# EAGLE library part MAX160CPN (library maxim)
ANALOG/DIGITAL CONVERTER

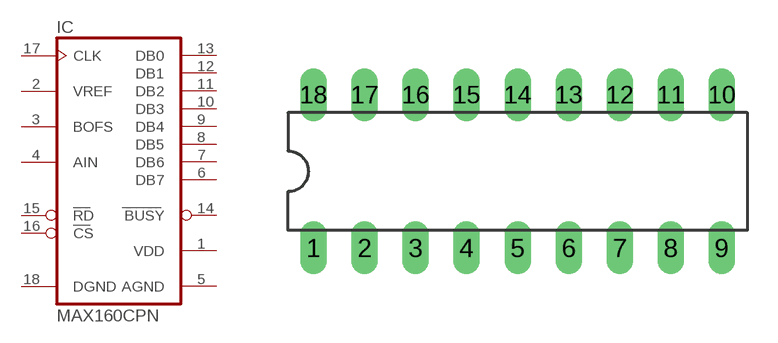
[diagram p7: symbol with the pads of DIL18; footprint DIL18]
Designator prefix IC

## MAX160CPN (MPN: MAX160CPN+; OC_FARNELL: unknown; OC_NEWARK: 99K3001)  [DIL18]
1  VDD  pwr
2  VREF  in
3  BOFS  in
4  AIN  in
5  AGND  pwr
6  DB7  hiz
7  DB6  hiz
8  DB5  hiz
9  DB4  hiz
10  DB3  hiz
11  DB2  hiz
12  DB1  hiz
13  DB0  hiz
14  BUSY  out
15  RD  in
16  CS  in
17  CLK  in
18  DGND  pwr

## Footprint DIL18 (pad centres in mm)
Dual In Line Package
drill 0.813 long: 1 -10.16,-3.81; 2 -7.62,-3.81; 3 -5.08,-3.81; 4 -2.54,-3.81; 5 0,-3.81; 6 2.54,-3.81; 7 5.08,-3.81; 8 7.62,-3.81; 9 10.16,-3.81; 10 10.16,3.81; 11 7.62,3.81; 12 5.08,3.81; 13 2.54,3.81; 14 0,3.81; 15 -2.54,3.81; 16 -5.08,3.81; 17 -7.62,3.81; 18 -10.16,3.81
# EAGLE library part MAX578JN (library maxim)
ANALOG/DIGITAL CONVERTER

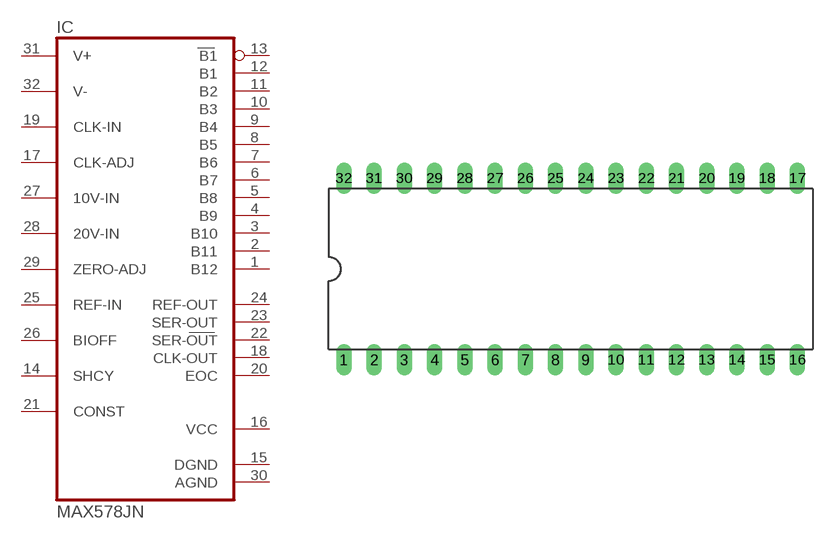
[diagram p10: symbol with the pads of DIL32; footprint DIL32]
Designator prefix IC

## MAX578JN (OC_FARNELL: unknown; OC_NEWARK: unknown)  [DIL32]
1  B12  hiz
2  B11  hiz
3  B10  hiz
4  B9  hiz
5  B8  hiz
6  B7  hiz
7  B6  hiz
8  B5  hiz
9  B4  hiz
10  B3  hiz
11  B2  hiz
12  B1  hiz
13  B1  hiz
14  SHCY  in
15  DGND  out
16  VCC  pwr
17  CLK-ADJ  in
18  CLK-OUT  out
19  CLK-IN  in
20  EOC  out
21  CONST  in
22  SER-OUT  out
23  SER-OUT  out
24  REF-OUT  out
25  REF-IN  in
26  BIOFF  in
27  10V-IN  in
28  20V-IN  in
29  ZERO-ADJ  in
30  AGND  pwr
31  V+  in
32  V-  in

## Footprint DIL32 (pad centres in mm)
Dual In Line Package
drill 0.813 long: 1 -19.05,-7.62; 2 -16.51,-7.62; 3 -13.97,-7.62; 4 -11.43,-7.62; 5 -8.89,-7.62; 6 -6.35,-7.62; 7 -3.81,-7.62; 8 -1.27,-7.62; 9 1.27,-7.62; 10 3.81,-7.62; 11 6.35,-7.62; 12 8.89,-7.62; 13 11.43,-7.62; 14 13.97,-7.62; 15 16.51,-7.62; 16 19.05,-7.62; 17 19.05,7.62; 18 16.51,7.62; 19 13.97,7.62; 20 11.43,7.62; 21 8.89,7.62; 22 6.35,7.62; 23 3.81,7.62; 24 1.27,7.62; 25 -1.27,7.62; 26 -3.81,7.62; 27 -6.35,7.62; 28 -8.89,7.62; 29 -11.43,7.62; 30 -13.97,7.62; 31 -16.51,7.62; 32 -19.05,7.62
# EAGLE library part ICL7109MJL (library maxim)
ANALOG/DIGITAL CONVERTER

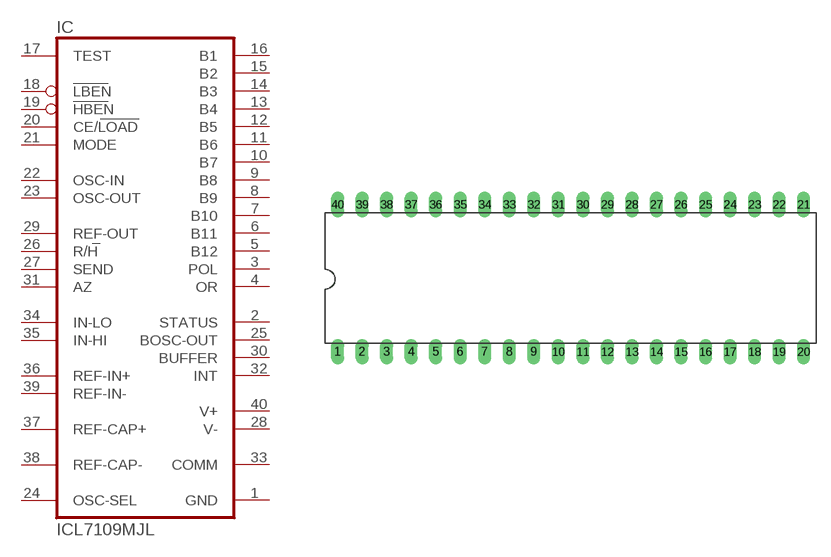
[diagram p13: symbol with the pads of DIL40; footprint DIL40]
Designator prefix IC

## ICL7109MJL (OC_FARNELL: unknown; OC_NEWARK: unknown)  [DIL40]
1  GND  pwr
2  STATUS  out
3  POL  out
4  OR  out
5  B12  hiz
6  B11  hiz
7  B10  hiz
8  B9  hiz
9  B8  hiz
10  B7  hiz
11  B6  hiz
12  B5  hiz
13  B4  hiz
14  B3  hiz
15  B2  hiz
16  B1  hiz
17  TEST  in
18  LBEN
19  HBEN
20  CE/LOAD
21  MODE  in
22  OSC-IN  in
23  OSC-OUT  out
24  OSC-SEL  in
25  BOSC-OUT  out
26  R/H  in
27  SEND  in
28  V-  pwr
29  REF-OUT  in
30  BUFFER  out
31  AZ  pas
32  INT  out
33  COMM  pwr
34  IN-LO  in
35  IN-HI  in
36  REF-IN+  in
37  REF-CAP+  pas
38  REF-CAP-  pas
39  REF-IN-  in
40  V+  pwr

## Footprint DIL40 (pad centres in mm)
Dual In Line Package
drill 0.813 long: 1 -24.13,-7.62; 2 -21.59,-7.62; 3 -19.05,-7.62; 4 -16.51,-7.62; 5 -13.97,-7.62; 6 -11.43,-7.62; 7 -8.89,-7.62; 8 -6.35,-7.62; 9 -3.81,-7.62; 10 -1.27,-7.62; 11 1.27,-7.62; 12 3.81,-7.62; 13 6.35,-7.62; 14 8.89,-7.62; 15 11.43,-7.62; 16 13.97,-7.62; 17 16.51,-7.62; 18 19.05,-7.62; 19 21.59,-7.62; 20 24.13,-7.62; 21 24.13,7.62; 22 21.59,7.62; 23 19.05,7.62; 24 16.51,7.62; 25 13.97,7.62; 26 11.43,7.62; 27 8.89,7.62; 28 6.35,7.62; 29 3.81,7.62; 30 1.27,7.62; 31 -1.27,7.62; 32 -3.81,7.62; 33 -6.35,7.62; 34 -8.89,7.62; 35 -11.43,7.62; 36 -13.97,7.62; 37 -16.51,7.62; 38 -19.05,7.62; 39 -21.59,7.62; 40 -24.13,7.62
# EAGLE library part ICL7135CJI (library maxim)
ANALOG/DIGITAL CONVERTER

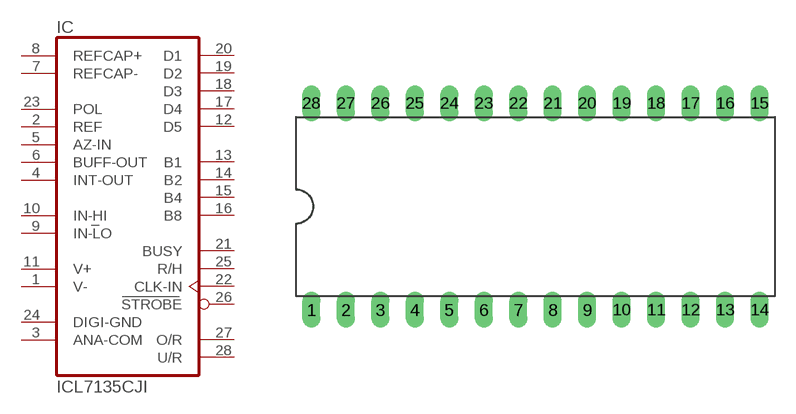
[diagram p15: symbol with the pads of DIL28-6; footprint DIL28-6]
Designator prefix IC

## ICL7135CJI (OC_FARNELL: unknown; OC_NEWARK: unknown)  [DIL28-6]
1  V-  pwr
2  REF  in
3  ANA-COM  pwr
4  INT-OUT  out
5  AZ-IN  in
6  BUFF-OUT  out
7  REFCAP-  pas
8  REFCAP+  pas
9  IN-LO  in
10  IN-HI  in
11  V+  pwr
12  D5  hiz
13  B1  out
14  B2  out
15  B4  out
16  B8  out
17  D4  hiz
18  D3  hiz
19  D2  hiz
20  D1  hiz
21  BUSY  out
22  CLK-IN  in
23  POL  in
24  DIGI-GND  pwr
25  R/H  in
26  STROBE  out
27  O/R  out
28  U/R  out

## Footprint DIL28-6 (pad centres in mm)
Dual In Line Package 0.6 inch
drill 0.813 long: 1 -16.51,-7.62; 2 -13.97,-7.62; 3 -11.43,-7.62; 4 -8.89,-7.62; 5 -6.35,-7.62; 6 -3.81,-7.62; 7 -1.27,-7.62; 8 1.27,-7.62; 9 3.81,-7.62; 10 6.35,-7.62; 11 8.89,-7.62; 12 11.43,-7.62; 13 13.97,-7.62; 14 16.51,-7.62; 15 16.51,7.62; 16 13.97,7.62; 17 11.43,7.62; 18 8.89,7.62; 19 6.35,7.62; 20 3.81,7.62; 21 1.27,7.62; 22 -1.27,7.62; 23 -3.81,7.62; 24 -6.35,7.62; 25 -8.89,7.62; 26 -11.43,7.62; 27 -13.97,7.62; 28 -16.51,7.62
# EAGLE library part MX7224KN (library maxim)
DIGITAL/ANALOG CONVERTER

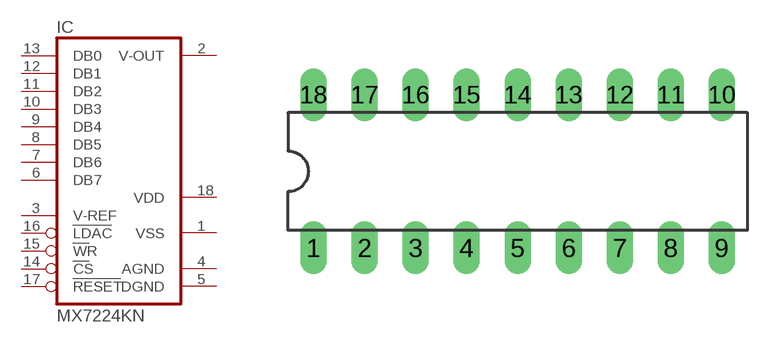
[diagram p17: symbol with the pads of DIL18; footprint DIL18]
Designator prefix IC

## MX7224KN (MPN: MX7224KN; OC_FARNELL: unknown; OC_NEWARK: 91C3202)  [DIL18]
1  VSS  pwr
2  V-OUT  out
3  V-REF  in
4  AGND  pwr
5  DGND  pwr
6  DB7  in
7  DB6  in
8  DB5  in
9  DB4  in
10  DB3  in
11  DB2  in
12  DB1  in
13  DB0  in
14  CS  in
15  WR  in
16  LDAC  in
17  RESET  in
18  VDD  pwr

## Footprint DIL18 (pad centres in mm)
Dual In Line Package
drill 0.813 long: 1 -10.16,-3.81; 2 -7.62,-3.81; 3 -5.08,-3.81; 4 -2.54,-3.81; 5 0,-3.81; 6 2.54,-3.81; 7 5.08,-3.81; 8 7.62,-3.81; 9 10.16,-3.81; 10 10.16,3.81; 11 7.62,3.81; 12 5.08,3.81; 13 2.54,3.81; 14 0,3.81; 15 -2.54,3.81; 16 -5.08,3.81; 17 -7.62,3.81; 18 -10.16,3.81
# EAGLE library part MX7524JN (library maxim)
DIGITAL/ANALOG CONVERTER

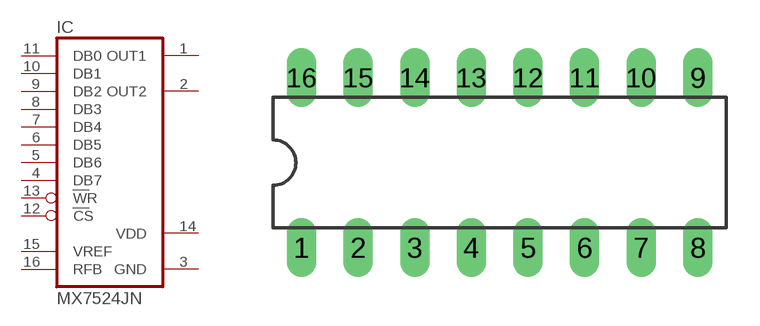
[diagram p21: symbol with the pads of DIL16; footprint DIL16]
Designator prefix IC

## MX7524JN (MPN: MX7524JN; OC_FARNELL: unknown; OC_NEWARK: 91C3294)  [DIL16]
1  OUT1  out
2  OUT2  out
3  GND  pwr
4  DB7  in
5  DB6  in
6  DB5  in
7  DB4  in
8  DB3  in
9  DB2  in
10  DB1  in
11  DB0  in
12  CS  in
13  WR  in
14  VDD  pwr
15  VREF  in
16  RFB  in

## Footprint DIL16 (pad centres in mm)
Dual In Line Package
drill 0.813 long: 1 -8.89,-3.81; 2 -6.35,-3.81; 3 -3.81,-3.81; 4 -1.27,-3.81; 5 1.27,-3.81; 6 3.81,-3.81; 7 6.35,-3.81; 8 8.89,-3.81; 9 8.89,3.81; 10 6.35,3.81; 11 3.81,3.81; 12 1.27,3.81; 13 -1.27,3.81; 14 -3.81,3.81; 15 -6.35,3.81; 16 -8.89,3.81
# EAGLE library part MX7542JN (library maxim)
DIGITAL/ANALOG CONVERTER

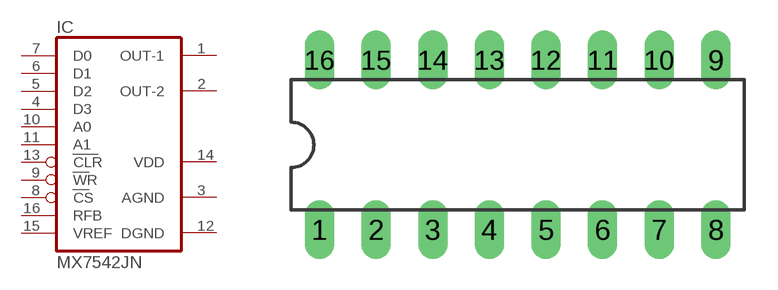
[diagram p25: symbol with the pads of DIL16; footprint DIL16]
Designator prefix IC

## MX7542JN (MPN: MX7542JN; OC_FARNELL: unknown; OC_NEWARK: 91C3501)  [DIL16]
1  OUT-1  out
2  OUT-2  out
3  AGND  pwr
4  D3  in
5  D2  in
6  D1  in
7  D0  in
8  CS  in
9  WR  in
10  A0  in
11  A1  in
12  DGND  in
13  CLR  in
14  VDD  pwr
15  VREF  in
16  RFB  in

## Footprint DIL16 (pad centres in mm)
Dual In Line Package
drill 0.813 long: 1 -8.89,-3.81; 2 -6.35,-3.81; 3 -3.81,-3.81; 4 -1.27,-3.81; 5 1.27,-3.81; 6 3.81,-3.81; 7 6.35,-3.81; 8 8.89,-3.81; 9 8.89,3.81; 10 6.35,3.81; 11 3.81,3.81; 12 1.27,3.81; 13 -1.27,3.81; 14 -3.81,3.81; 15 -6.35,3.81; 16 -8.89,3.81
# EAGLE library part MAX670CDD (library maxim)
VOLATAGE REFERENCE

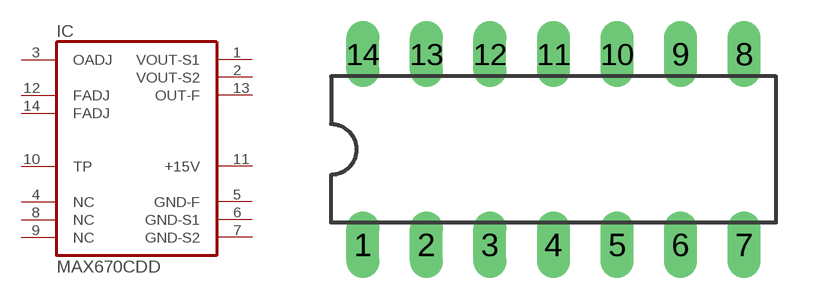
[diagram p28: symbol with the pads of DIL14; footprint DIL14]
Designator prefix IC

## MAX670CDD (OC_FARNELL: unknown; OC_NEWARK: unknown)  [DIL14]
1  VOUT-S1  out
2  VOUT-S2  out
3  OADJ  in
4  NC  nc
5  GND-F  pwr
6  GND-S1  pwr
7  GND-S2  pwr
8  NC  nc
9  NC  nc
10  TP  pas
11  +15V  pwr
12  FADJ  in
13  OUT-F  out
14  FADJ  in

## Footprint DIL14 (pad centres in mm)
Dual In Line Package
drill 0.813 long: 1 -7.62,-3.81; 2 -5.08,-3.81; 3 -2.54,-3.81; 4 0,-3.81; 5 2.54,-3.81; 6 5.08,-3.81; 7 7.62,-3.81; 8 7.62,3.81; 9 5.08,3.81; 10 2.54,3.81; 11 0,3.81; 12 -2.54,3.81; 13 -5.08,3.81; 14 -7.62,3.81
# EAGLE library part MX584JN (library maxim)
VOLTAGE REFERENCE

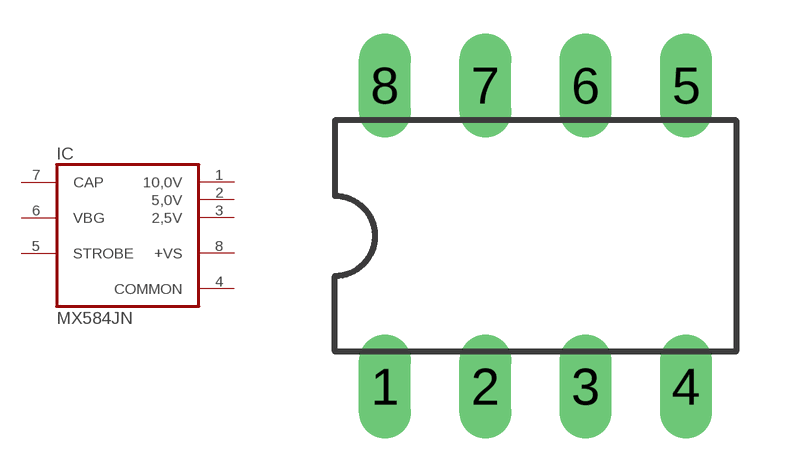
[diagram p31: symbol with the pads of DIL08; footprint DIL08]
Designator prefix IC

## MX584JN (OC_FARNELL: unknown; OC_NEWARK: unknown)  [DIL08]
1  10,0V  out
2  5,0V  out
3  2,5V  out
4  COMMON  pwr
5  STROBE  in
6  VBG  pas
7  CAP  pas
8  +VS  pwr

## Footprint DIL08 (pad centres in mm)
Dual In Line Package
drill 0.813 long: 1 -3.81,-3.81; 2 -1.27,-3.81; 3 1.27,-3.81; 4 3.81,-3.81; 5 3.81,3.81; 6 1.27,3.81; 7 -1.27,3.81; 8 -3.81,3.81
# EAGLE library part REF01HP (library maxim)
VOLTAGE REFERENCE

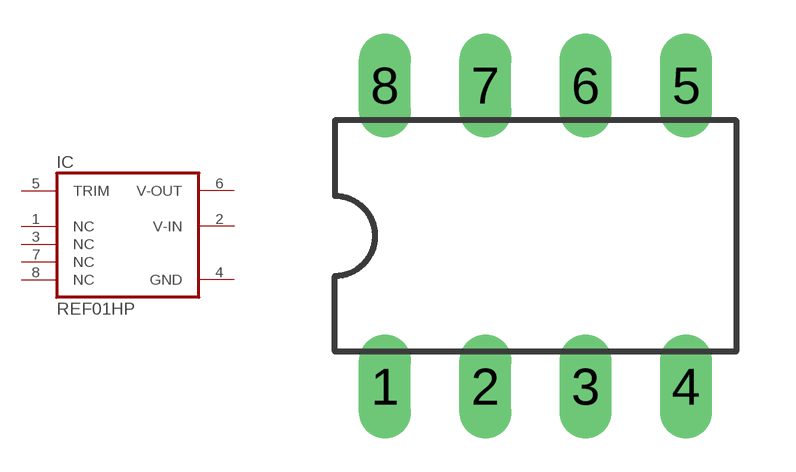
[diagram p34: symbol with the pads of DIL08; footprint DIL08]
Designator prefix IC

## REF01HP (MF: ALTERA CORPORATION; MPN: REF01HP; OC_FARNELL: 9605150; OC_NEWARK: 05F8981)  [DIL08]
1  NC  nc
2  V-IN  pwr
3  NC  nc
4  GND  pwr
5  TRIM  in
6  V-OUT  out
7  NC  nc
8  NC  nc

## Footprint DIL08 (pad centres in mm)
Dual In Line Package
drill 0.813 long: 1 -3.81,-3.81; 2 -1.27,-3.81; 3 1.27,-3.81; 4 3.81,-3.81; 5 3.81,3.81; 6 1.27,3.81; 7 -1.27,3.81; 8 -3.81,3.81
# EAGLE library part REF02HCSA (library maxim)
VOLTAGE REFERENCE

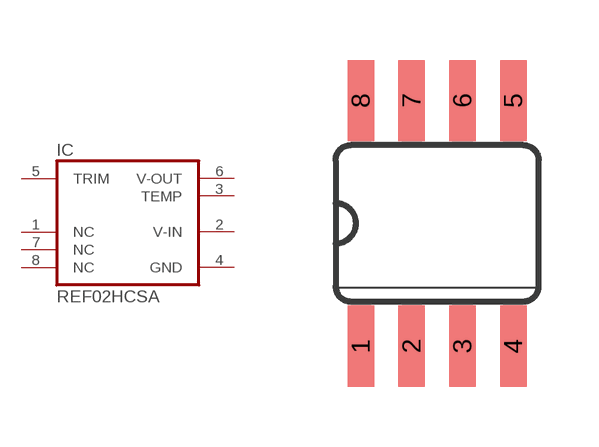
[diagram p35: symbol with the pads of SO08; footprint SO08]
Designator prefix IC

## REF02HCSA (OC_FARNELL: unknown; OC_NEWARK: unknown)  [SO08]
1  NC  nc
2  V-IN  pwr
3  TEMP  out
4  GND  pwr
5  TRIM  in
6  V-OUT  out
7  NC  nc
8  NC  nc

## Footprint SO08 (pad centres in mm)
Small Outline Package SOIC 150 mil
smd 0.66 x 2.032: 1 -1.905,-3.073; 2 -0.635,-3.073; 3 0.635,-3.073; 4 1.905,-3.073; 5 1.905,3.073; 6 0.635,3.073; 7 -0.635,3.073; 8 -1.905,3.073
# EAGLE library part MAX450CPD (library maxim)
VIDEO AMPLIFIER

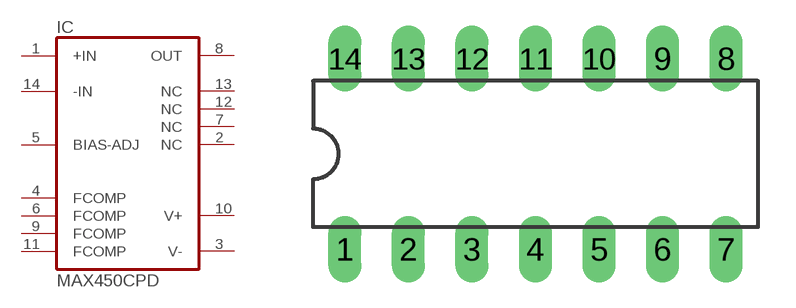
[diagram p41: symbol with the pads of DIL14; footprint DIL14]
Designator prefix IC

## MAX450CPD (OC_FARNELL: unknown; OC_NEWARK: unknown)  [DIL14]
1  +IN  in
2  NC  nc
3  V-  pwr
4  FCOMP  pas
5  BIAS-ADJ  in
6  FCOMP  pas
7  NC  nc
8  OUT  out
9  FCOMP  pas
10  V+  pwr
11  FCOMP  pas
12  NC  nc
13  NC  nc
14  -IN  in

## Footprint DIL14 (pad centres in mm)
Dual In Line Package
drill 0.813 long: 1 -7.62,-3.81; 2 -5.08,-3.81; 3 -2.54,-3.81; 4 0,-3.81; 5 2.54,-3.81; 6 5.08,-3.81; 7 7.62,-3.81; 8 7.62,3.81; 9 5.08,3.81; 10 2.54,3.81; 11 0,3.81; 12 -2.54,3.81; 13 -5.08,3.81; 14 -7.62,3.81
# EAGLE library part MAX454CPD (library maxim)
MULTIPLEXER

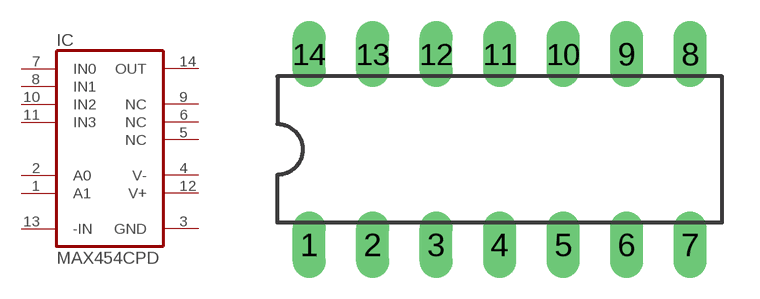
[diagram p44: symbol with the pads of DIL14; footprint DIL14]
Designator prefix IC

## MAX454CPD (MF: MAXIM; MPN: MAX454CPD+; OC_FARNELL: unknown; OC_NEWARK: 67K5326)  [DIL14]
1  A1  in
2  A0  in
3  GND  pwr
4  V-  pwr
5  NC  nc
6  NC  nc
7  IN0  in
8  IN1  in
9  NC  nc
10  IN2  in
11  IN3  in
12  V+  pwr
13  -IN  in
14  OUT  out

## Footprint DIL14 (pad centres in mm)
Dual In Line Package
drill 0.813 long: 1 -7.62,-3.81; 2 -5.08,-3.81; 3 -2.54,-3.81; 4 0,-3.81; 5 2.54,-3.81; 6 5.08,-3.81; 7 7.62,-3.81; 8 7.62,3.81; 9 5.08,3.81; 10 2.54,3.81; 11 0,3.81; 12 -2.54,3.81; 13 -5.08,3.81; 14 -7.62,3.81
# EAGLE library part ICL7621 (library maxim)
Dual Operational Amplifiers Source: http://datasheets.maxim-ic.com/en/ds/ICL7612-ICL764X.pdf

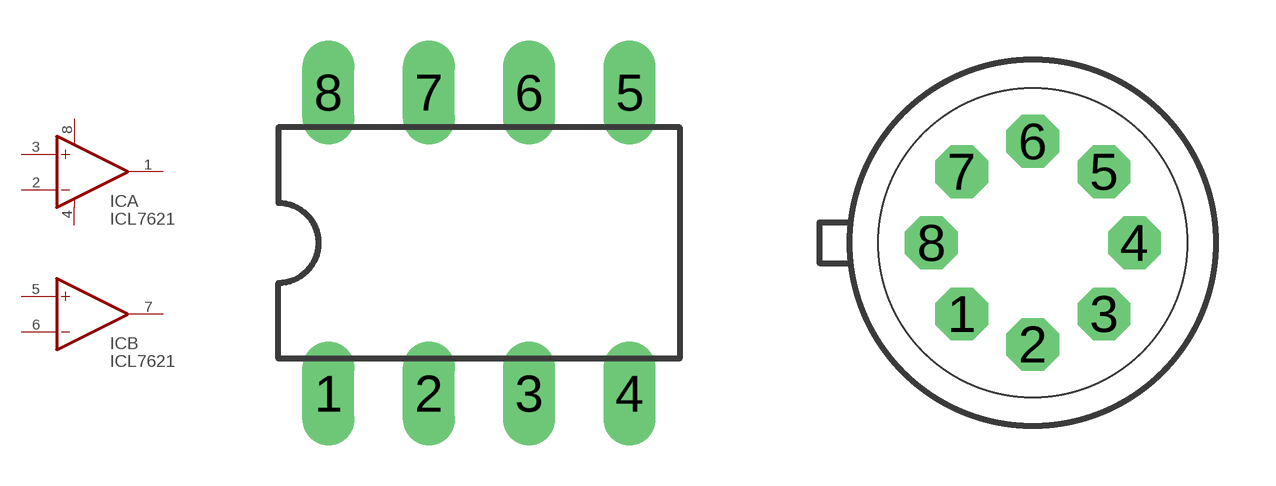
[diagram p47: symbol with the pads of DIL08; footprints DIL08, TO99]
Designator prefix IC; gates A=OPAMP+- B=OPAMP

## ICL7621PA (OC_FARNELL: unknown; OC_NEWARK: unknown)  [DIL08]
1  A:OUT  out
2  A:-IN  in
3  A:+IN  in
4  A:V-  pwr
5  B:+IN  in
6  B:-IN  in
7  B:OUT  out
8  A:V+  pwr

## ICL7621TV (OC_FARNELL: unknown; OC_NEWARK: unknown)  [TO99]
Pads as for DIL08

## ICL7621SA (OC_FARNELL: unknown; OC_NEWARK: unknown)  [SO08]
Pads as for DIL08

## Footprint DIL08 (pad centres in mm)
Dual In Line Package
drill 0.813 long: 1 -3.81,-3.81; 2 -1.27,-3.81; 3 1.27,-3.81; 4 3.81,-3.81; 5 3.81,3.81; 6 1.27,3.81; 7 -1.27,3.81; 8 -3.81,3.81

## Footprint TO99 (pad centres in mm)
TO-99
drill 0.813 octagon: 1 -1.778,-1.778; 2 0,-2.54; 3 1.778,-1.778; 4 2.54,0; 5 1.778,1.778; 6 0,2.54; 7 -1.778,1.778; 8 -2.54,0

## Footprint SO08 (pad centres in mm)
Small Outline Package SOIC 150 mil
smd 0.66 x 2.032: 1 -1.905,-3.073; 2 -0.635,-3.073; 3 0.635,-3.073; 4 1.905,-3.073; 5 1.905,3.073; 6 0.635,3.073; 7 -0.635,3.073; 8 -1.905,3.073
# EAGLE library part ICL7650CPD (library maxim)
OP AMP

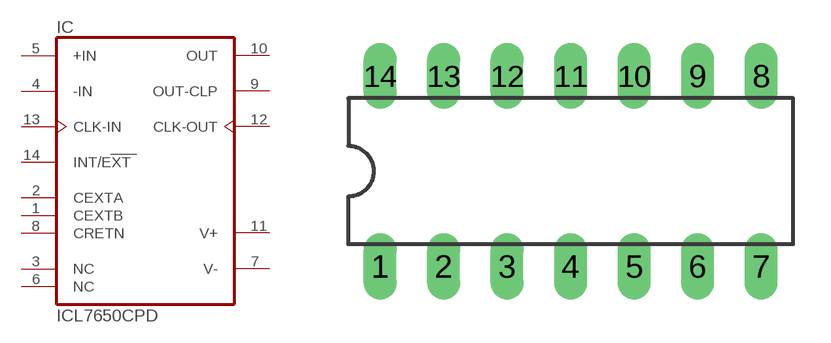
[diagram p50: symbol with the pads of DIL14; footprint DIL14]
Designator prefix IC

## ICL7650CPD (MPN: ICL7650CPD; OC_FARNELL: unknown; OC_NEWARK: 06F7425)  [DIL14]
1  CEXTB  pas
2  CEXTA  pas
3  NC  nc
4  -IN  in
5  +IN  in
6  NC  nc
7  V-  pwr
8  CRETN  pas
9  OUT-CLP  out
10  OUT  out
11  V+  pwr
12  CLK-OUT  out
13  CLK-IN  in
14  INT/EXT  in

## Footprint DIL14 (pad centres in mm)
Dual In Line Package
drill 0.813 long: 1 -7.62,-3.81; 2 -5.08,-3.81; 3 -2.54,-3.81; 4 0,-3.81; 5 2.54,-3.81; 6 5.08,-3.81; 7 7.62,-3.81; 8 7.62,3.81; 9 5.08,3.81; 10 2.54,3.81; 11 0,3.81; 12 -2.54,3.81; 13 -5.08,3.81; 14 -7.62,3.81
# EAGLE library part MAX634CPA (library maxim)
SWITCHING REGULATOR

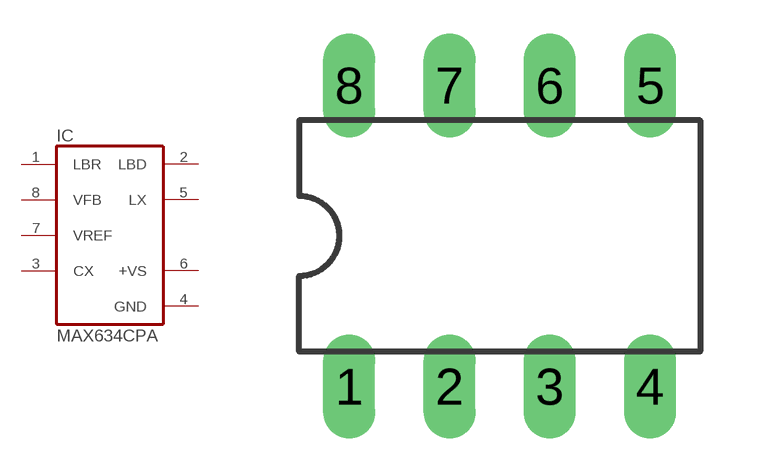
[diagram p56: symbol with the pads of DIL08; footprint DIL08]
Designator prefix IC

## MAX634CPA (MPN: MAX634CPA; OC_FARNELL: unknown; OC_NEWARK: 78C4814)  [DIL08]
1  LBR  in
2  LBD  out
3  CX  pas
4  GND  pwr
5  LX  out
6  +VS  pwr
7  VREF  in
8  VFB  in

## Footprint DIL08 (pad centres in mm)
Dual In Line Package
drill 0.813 long: 1 -3.81,-3.81; 2 -1.27,-3.81; 3 1.27,-3.81; 4 3.81,-3.81; 5 3.81,3.81; 6 1.27,3.81; 7 -1.27,3.81; 8 -3.81,3.81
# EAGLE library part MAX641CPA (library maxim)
Step-up SWITCHING REGULATOR CONTROLLER

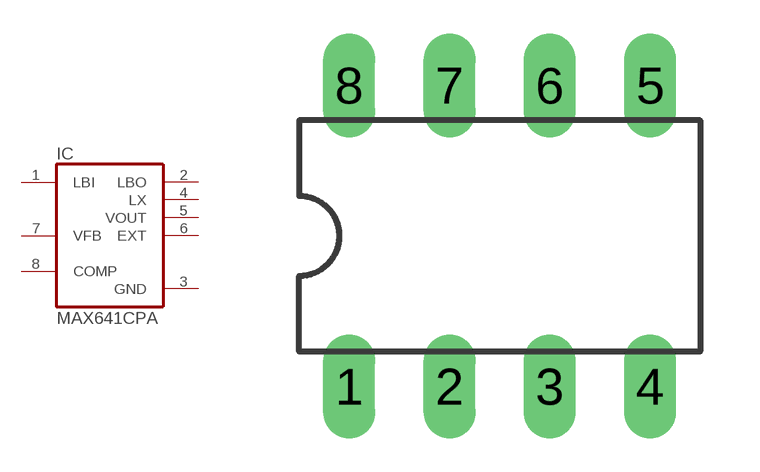
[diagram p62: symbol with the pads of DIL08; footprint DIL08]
Designator prefix IC

## MAX641CPA (OC_FARNELL: unknown; OC_NEWARK: unknown)  [DIL08]
1  LBI  in
2  LBO  out
3  GND  pwr
4  LX  out
5  VOUT  out
6  EXT  out
7  VFB  in
8  COMP  in

## Footprint DIL08 (pad centres in mm)
Dual In Line Package
drill 0.813 long: 1 -3.81,-3.81; 2 -1.27,-3.81; 3 1.27,-3.81; 4 3.81,-3.81; 5 3.81,3.81; 6 1.27,3.81; 7 -1.27,3.81; 8 -3.81,3.81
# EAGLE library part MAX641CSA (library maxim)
Step-up SWITCHING REGULATOR CONTROLLER

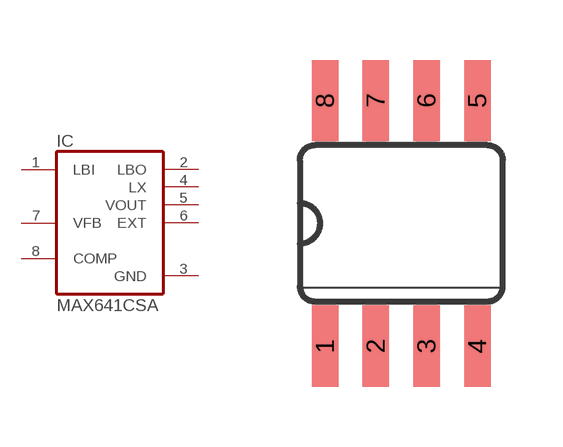
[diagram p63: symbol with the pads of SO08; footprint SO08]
Designator prefix IC

## MAX641CSA (OC_FARNELL: unknown; OC_NEWARK: unknown)  [SO08]
1  LBI  in
2  LBO  out
3  GND  pwr
4  LX  out
5  VOUT  out
6  EXT  out
7  VFB  in
8  COMP  in

## Footprint SO08 (pad centres in mm)
Small Outline Package SOIC 150 mil
smd 0.66 x 2.032: 1 -1.905,-3.073; 2 -0.635,-3.073; 3 0.635,-3.073; 4 1.905,-3.073; 5 1.905,3.073; 6 0.635,3.073; 7 -0.635,3.073; 8 -1.905,3.073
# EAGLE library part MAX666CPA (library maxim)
Positive VOLTAGE REGULATOR

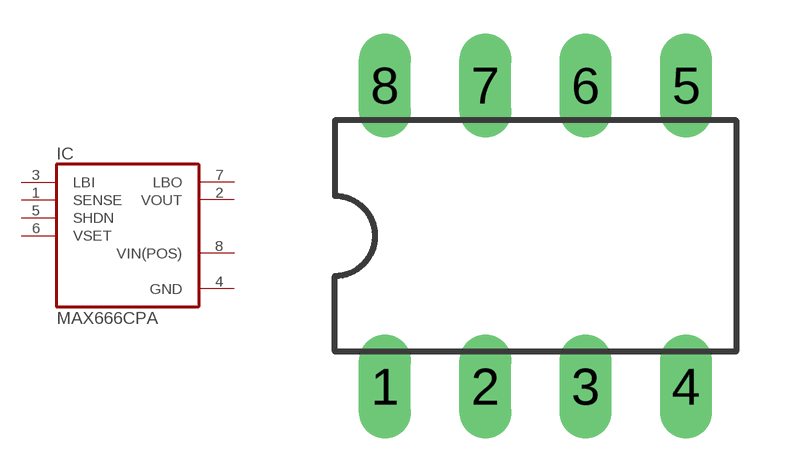
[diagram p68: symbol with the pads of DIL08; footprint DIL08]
Designator prefix IC

## MAX666CPA (MF: MAXIM; MPN: MAX666CPA; OC_FARNELL: 205280; OC_NEWARK: 34C3970)  [DIL08]
1  SENSE  in
2  VOUT  out
3  LBI  in
4  GND  pwr
5  SHDN  in
6  VSET  in
7  LBO  out
8  VIN(POS)  pwr

## Footprint DIL08 (pad centres in mm)
Dual In Line Package
drill 0.813 long: 1 -3.81,-3.81; 2 -1.27,-3.81; 3 1.27,-3.81; 4 3.81,-3.81; 5 3.81,3.81; 6 1.27,3.81; 7 -1.27,3.81; 8 -3.81,3.81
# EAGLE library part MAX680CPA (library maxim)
Switched-capcitor VOLTAGE CONVERTER

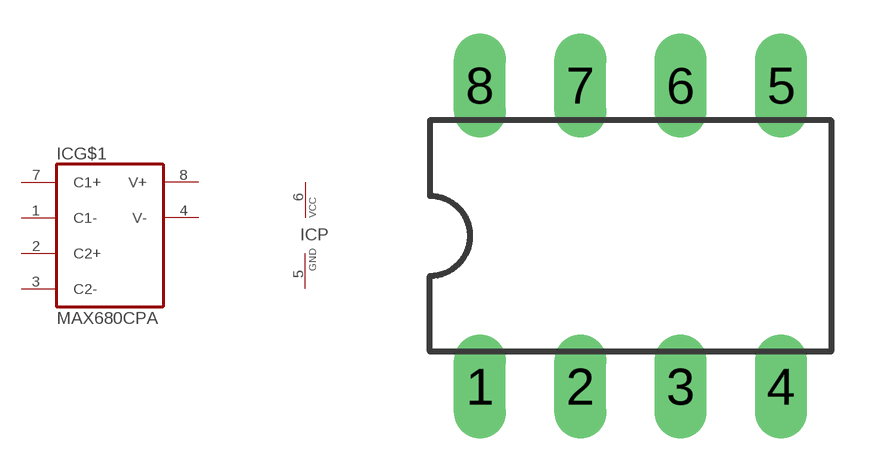
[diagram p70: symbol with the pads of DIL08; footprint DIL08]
Designator prefix IC; gates G$1=MAX680 P=VCC-GND

## MAX680CPA (MPN: MAX680CPA; OC_FARNELL: 1187929; OC_NEWARK: 34C3974)  [DIL08]
1  G$1:C1-  pas
2  G$1:C2+  pas
3  G$1:C2-  pas
4  G$1:V-  out
5  P:GND  pwr
6  P:VCC  pwr
7  G$1:C1+  pas
8  G$1:V+  out

## Footprint DIL08 (pad centres in mm)
Dual In Line Package
drill 0.813 long: 1 -3.81,-3.81; 2 -1.27,-3.81; 3 1.27,-3.81; 4 3.81,-3.81; 5 3.81,3.81; 6 1.27,3.81; 7 -1.27,3.81; 8 -3.81,3.81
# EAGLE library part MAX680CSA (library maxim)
Switched-capcitor VOLTAGE CONVERTER

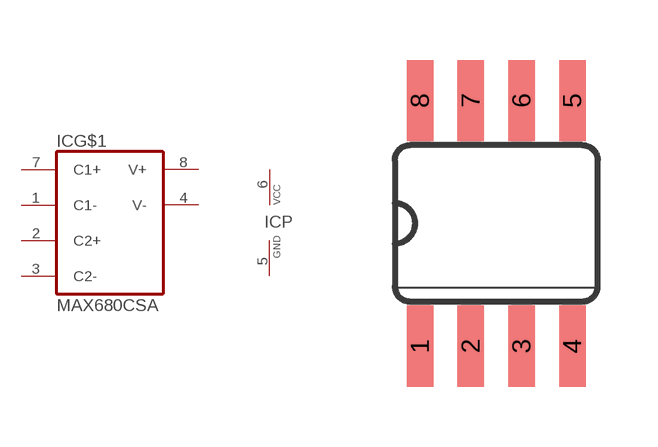
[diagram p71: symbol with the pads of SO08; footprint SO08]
Designator prefix IC; gates G$1=MAX680 P=VCC-GND

## MAX680CSA (MF: MAXIM; MPN: MAX680CSA; OC_FARNELL: 9725717; OC_NEWARK: 34C3975)  [SO08]
1  G$1:C1-  pas
2  G$1:C2+  pas
3  G$1:C2-  pas
4  G$1:V-  out
5  P:GND  pwr
6  P:VCC  pwr
7  G$1:C1+  pas
8  G$1:V+  out

## Footprint SO08 (pad centres in mm)
Small Outline Package SOIC 150 mil
smd 0.66 x 2.032: 1 -1.905,-3.073; 2 -0.635,-3.073; 3 0.635,-3.073; 4 1.905,-3.073; 5 1.905,3.073; 6 0.635,3.073; 7 -0.635,3.073; 8 -1.905,3.073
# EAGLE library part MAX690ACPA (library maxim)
WATCHDOG

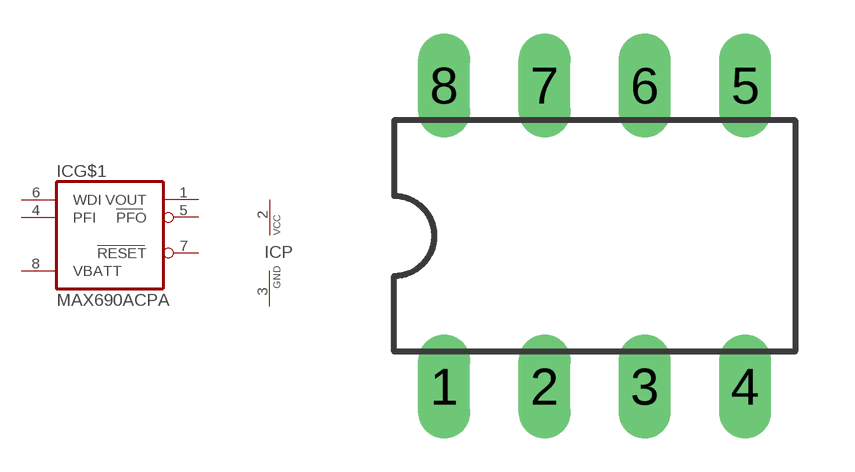
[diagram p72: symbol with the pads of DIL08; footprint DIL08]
Designator prefix IC; gates G$1=MAX690 P=VCC-GND

## MAX690ACPA (MF: MAXIM; MPN: MAX690ACPA+; OC_FARNELL: 9723781; OC_NEWARK: 28K3550)  [DIL08]
1  G$1:VOUT  out
2  P:VCC  pwr
3  P:GND  pwr
4  G$1:PFI  in
5  G$1:PFO  out
6  G$1:WDI  in
7  G$1:RESET  out
8  G$1:VBATT  in

## Footprint DIL08 (pad centres in mm)
Dual In Line Package
drill 0.813 long: 1 -3.81,-3.81; 2 -1.27,-3.81; 3 1.27,-3.81; 4 3.81,-3.81; 5 3.81,3.81; 6 1.27,3.81; 7 -1.27,3.81; 8 -3.81,3.81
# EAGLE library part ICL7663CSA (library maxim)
Positive VOLTAGE REGULATOR

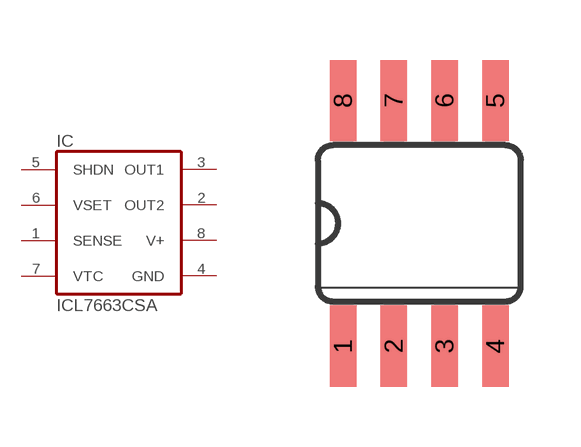
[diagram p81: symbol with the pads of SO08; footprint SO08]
Designator prefix IC

## ICL7663CSA (OC_FARNELL: unknown; OC_NEWARK: unknown)  [SO08]
1  SENSE  in
2  OUT2  out
3  OUT1  out
4  GND  pwr
5  SHDN  in
6  VSET  in
7  VTC  pas
8  V+  pwr

## Footprint SO08 (pad centres in mm)
Small Outline Package SOIC 150 mil
smd 0.66 x 2.032: 1 -1.905,-3.073; 2 -0.635,-3.073; 3 0.635,-3.073; 4 1.905,-3.073; 5 1.905,3.073; 6 0.635,3.073; 7 -0.635,3.073; 8 -1.905,3.073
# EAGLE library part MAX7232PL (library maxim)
LCD DISPLAY DRIVER

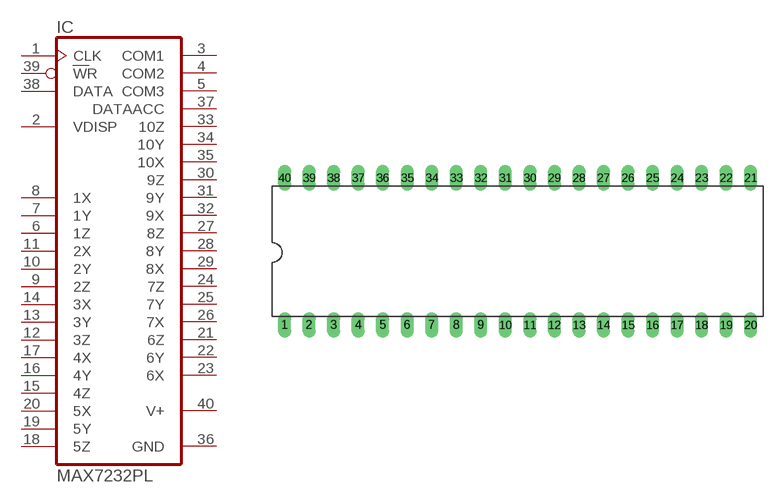
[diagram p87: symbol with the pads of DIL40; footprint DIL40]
Designator prefix IC

## MAX7232PL (OC_FARNELL: unknown; OC_NEWARK: unknown)  [DIL40]
1  CLK  in
2  VDISP  in
3  COM1  out
4  COM2  out
5  COM3  out
6  1Z  out
7  1Y  out
8  1X  out
9  2Z  out
10  2Y  out
11  2X  out
12  3Z  out
13  3Y  out
14  3X  out
15  4Z  out
16  4Y  out
17  4X  out
18  5Z  out
19  5Y  out
20  5X  out
21  6Z  out
22  6Y  out
23  6X  out
24  7Z  out
25  7Y  out
26  7X  out
27  8Z  out
28  8Y  out
29  8X  out
30  9Z  out
31  9Y  out
32  9X  out
33  10Z  out
34  10Y  out
35  10X  out
36  GND  pwr
37  DATAACC  out
38  DATA  in
39  WR  in
40  V+  pwr

## Footprint DIL40 (pad centres in mm)
Dual In Line Package
drill 0.813 long: 1 -24.13,-7.62; 2 -21.59,-7.62; 3 -19.05,-7.62; 4 -16.51,-7.62; 5 -13.97,-7.62; 6 -11.43,-7.62; 7 -8.89,-7.62; 8 -6.35,-7.62; 9 -3.81,-7.62; 10 -1.27,-7.62; 11 1.27,-7.62; 12 3.81,-7.62; 13 6.35,-7.62; 14 8.89,-7.62; 15 11.43,-7.62; 16 13.97,-7.62; 17 16.51,-7.62; 18 19.05,-7.62; 19 21.59,-7.62; 20 24.13,-7.62; 21 24.13,7.62; 22 21.59,7.62; 23 19.05,7.62; 24 16.51,7.62; 25 13.97,7.62; 26 11.43,7.62; 27 8.89,7.62; 28 6.35,7.62; 29 3.81,7.62; 30 1.27,7.62; 31 -1.27,7.62; 32 -3.81,7.62; 33 -6.35,7.62; 34 -8.89,7.62; 35 -11.43,7.62; 36 -13.97,7.62; 37 -16.51,7.62; 38 -19.05,7.62; 39 -21.59,7.62; 40 -24.13,7.62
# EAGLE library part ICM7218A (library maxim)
LED DECODER DRIVER

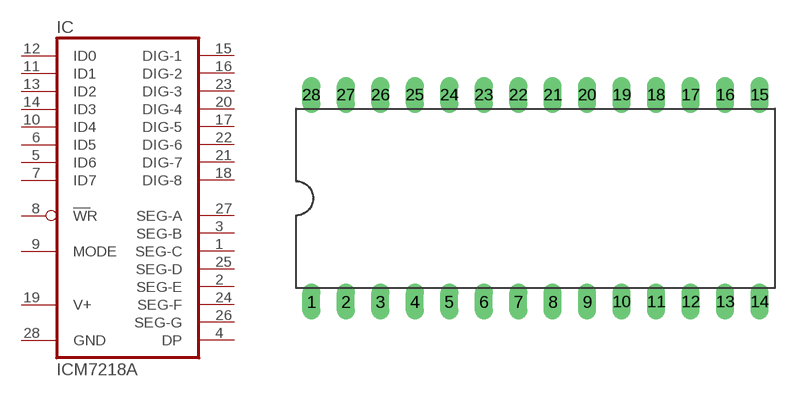
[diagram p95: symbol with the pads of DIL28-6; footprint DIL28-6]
Designator prefix IC

## ICM7218A (MF: INTERSIL; MPN: ICM7218AIJI; OC_FARNELL: 405991; OC_NEWARK: 06F7544)  [DIL28-6]
1  SEG-C  out
2  SEG-E  out
3  SEG-B  out
4  DP  out
5  ID6  in
6  ID5  in
7  ID7  in
8  WR  in
9  MODE  in
10  ID4  in
11  ID1  in
12  ID0  in
13  ID2  in
14  ID3  in
15  DIG-1  out
16  DIG-2  out
17  DIG-5  out
18  DIG-8  out
19  V+  pwr
20  DIG-4  out
21  DIG-7  out
22  DIG-6  out
23  DIG-3  out
24  SEG-F  out
25  SEG-D  out
26  SEG-G  out
27  SEG-A  out
28  GND  pwr

## Footprint DIL28-6 (pad centres in mm)
Dual In Line Package 0.6 inch
drill 0.813 long: 1 -16.51,-7.62; 2 -13.97,-7.62; 3 -11.43,-7.62; 4 -8.89,-7.62; 5 -6.35,-7.62; 6 -3.81,-7.62; 7 -1.27,-7.62; 8 1.27,-7.62; 9 3.81,-7.62; 10 6.35,-7.62; 11 8.89,-7.62; 12 11.43,-7.62; 13 13.97,-7.62; 14 16.51,-7.62; 15 16.51,7.62; 16 13.97,7.62; 17 11.43,7.62; 18 8.89,7.62; 19 6.35,7.62; 20 3.81,7.62; 21 1.27,7.62; 22 -1.27,7.62; 23 -3.81,7.62; 24 -6.35,7.62; 25 -8.89,7.62; 26 -11.43,7.62; 27 -13.97,7.62; 28 -16.51,7.62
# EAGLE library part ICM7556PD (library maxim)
TIMER

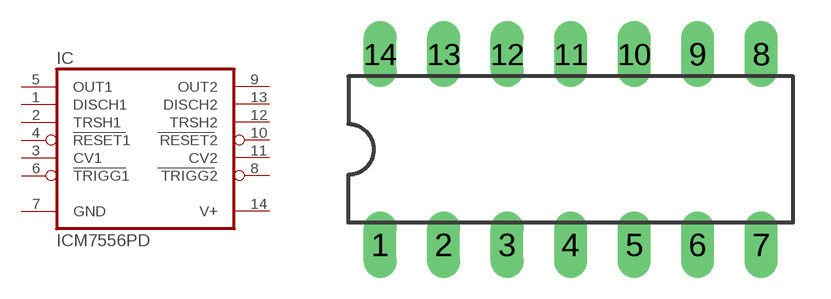
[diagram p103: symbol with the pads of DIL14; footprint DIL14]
Designator prefix IC

## ICM7556PD (OC_FARNELL: unknown; OC_NEWARK: unknown)  [DIL14]
1  DISCH1  in
2  TRSH1  in
3  CV1  pas
4  RESET1  in
5  OUT1  out
6  TRIGG1
7  GND  pwr
8  TRIGG2
9  OUT2  out
10  RESET2  in
11  CV2  pas
12  TRSH2  in
13  DISCH2  in
14  V+  pwr

## Footprint DIL14 (pad centres in mm)
Dual In Line Package
drill 0.813 long: 1 -7.62,-3.81; 2 -5.08,-3.81; 3 -2.54,-3.81; 4 0,-3.81; 5 2.54,-3.81; 6 5.08,-3.81; 7 7.62,-3.81; 8 7.62,3.81; 9 5.08,3.81; 10 2.54,3.81; 11 0,3.81; 12 -2.54,3.81; 13 -5.08,3.81; 14 -7.62,3.81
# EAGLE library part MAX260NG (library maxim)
Switched-capacitor FILTER

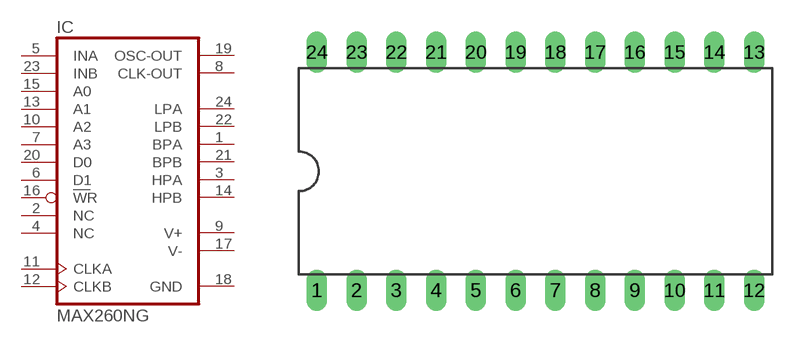
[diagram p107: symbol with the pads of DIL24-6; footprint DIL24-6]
Designator prefix IC

## MAX260NG (OC_FARNELL: unknown; OC_NEWARK: unknown)  [DIL24-6]
1  BPA  out
2  NC  nc
3  HPA  out
4  NC  nc
5  INA  in
6  D1  in
7  A3  in
8  CLK-OUT  out
9  V+  pwr
10  A2  in
11  CLKA  in
12  CLKB  in
13  A1  in
14  HPB  out
15  A0  in
16  WR  in
17  V-  pwr
18  GND  pwr
19  OSC-OUT  in
20  D0  in
21  BPB  out
22  LPB  out
23  INB  in
24  LPA  out

## Footprint DIL24-6 (pad centres in mm)
Dual In Line Package 0.6 inch
drill 0.813 long: 1 -13.97,-7.62; 2 -11.43,-7.62; 3 -8.89,-7.62; 4 -6.35,-7.62; 5 -3.81,-7.62; 6 -1.27,-7.62; 7 1.27,-7.62; 8 3.81,-7.62; 9 6.35,-7.62; 10 8.89,-7.62; 11 11.43,-7.62; 12 13.97,-7.62; 13 13.97,7.62; 14 11.43,7.62; 15 8.89,7.62; 16 6.35,7.62; 17 3.81,7.62; 18 1.27,7.62; 19 -1.27,7.62; 20 -3.81,7.62; 21 -6.35,7.62; 22 -8.89,7.62; 23 -11.43,7.62; 24 -13.97,7.62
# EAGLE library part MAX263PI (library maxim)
Switched-capacitor FILTER

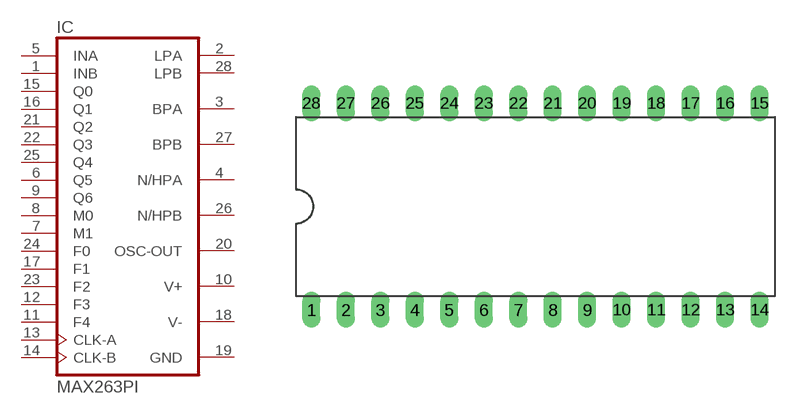
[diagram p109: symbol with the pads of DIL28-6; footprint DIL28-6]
Designator prefix IC

## MAX263PI (OC_FARNELL: unknown; OC_NEWARK: unknown)  [DIL28-6]
1  INB  in
2  LPA  out
3  BPA  out
4  N/HPA  out
5  INA  in
6  Q5  in
7  M1  in
8  M0  in
9  Q6  in
10  V+  pwr
11  F4  in
12  F3  in
13  CLK-A  in
14  CLK-B  in
15  Q0  in
16  Q1  in
17  F1  in
18  V-  pwr
19  GND  pwr
20  OSC-OUT  out
21  Q2  in
22  Q3  in
23  F2  in
24  F0  in
25  Q4  in
26  N/HPB  out
27  BPB  out
28  LPB  out

## Footprint DIL28-6 (pad centres in mm)
Dual In Line Package 0.6 inch
drill 0.813 long: 1 -16.51,-7.62; 2 -13.97,-7.62; 3 -11.43,-7.62; 4 -8.89,-7.62; 5 -6.35,-7.62; 6 -3.81,-7.62; 7 -1.27,-7.62; 8 1.27,-7.62; 9 3.81,-7.62; 10 6.35,-7.62; 11 8.89,-7.62; 12 11.43,-7.62; 13 13.97,-7.62; 14 16.51,-7.62; 15 16.51,7.62; 16 13.97,7.62; 17 11.43,7.62; 18 8.89,7.62; 19 6.35,7.62; 20 3.81,7.62; 21 1.27,7.62; 22 -1.27,7.62; 23 -3.81,7.62; 24 -6.35,7.62; 25 -8.89,7.62; 26 -11.43,7.62; 27 -13.97,7.62; 28 -16.51,7.62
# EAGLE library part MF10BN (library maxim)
FILTER

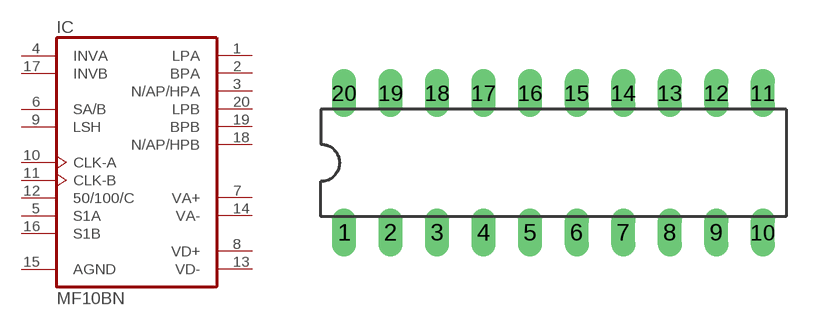
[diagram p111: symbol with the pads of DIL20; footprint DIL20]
Designator prefix IC

## MF10BN (OC_FARNELL: unknown; OC_NEWARK: unknown)  [DIL20]
1  LPA  out
2  BPA  out
3  N/AP/HPA  out
4  INVA  in
5  S1A  in
6  SA/B  in
7  VA+  pwr
8  VD+  pwr
9  LSH  in
10  CLK-A  in
11  CLK-B  in
12  50/100/C  in
13  VD-  pwr
14  VA-  pwr
15  AGND  pwr
16  S1B  in
17  INVB  in
18  N/AP/HPB  out
19  BPB  out
20  LPB  out

## Footprint DIL20 (pad centres in mm)
Dual In Line Package
drill 0.813 long: 1 -11.43,-3.81; 2 -8.89,-3.81; 3 -6.35,-3.81; 4 -3.81,-3.81; 5 -1.27,-3.81; 6 1.27,-3.81; 7 3.81,-3.81; 8 6.35,-3.81; 9 8.89,-3.81; 10 11.43,-3.81; 11 11.43,3.81; 12 8.89,3.81; 13 6.35,3.81; 14 3.81,3.81; 15 1.27,3.81; 16 -1.27,3.81; 17 -3.81,3.81; 18 -6.35,3.81; 19 -8.89,3.81; 20 -11.43,3.81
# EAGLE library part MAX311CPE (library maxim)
MULTIPLEXER

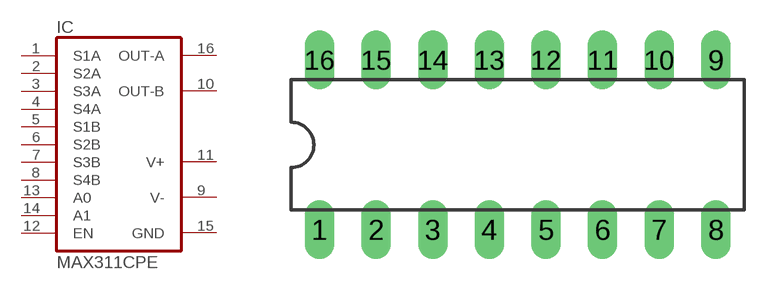
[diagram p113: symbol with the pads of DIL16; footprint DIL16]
Designator prefix IC

## MAX311CPE (MPN: MAX311CPE+; OC_FARNELL: unknown; OC_NEWARK: 05M8520)  [DIL16]
1  S1A  pas
2  S2A  pas
3  S3A  pas
4  S4A  pas
5  S1B  pas
6  S2B  pas
7  S3B  pas
8  S4B  pas
9  V-  pwr
10  OUT-B  pas
11  V+  pwr
12  EN  in
13  A0  in
14  A1  in
15  GND  pwr
16  OUT-A  pas

## Footprint DIL16 (pad centres in mm)
Dual In Line Package
drill 0.813 long: 1 -8.89,-3.81; 2 -6.35,-3.81; 3 -3.81,-3.81; 4 -1.27,-3.81; 5 1.27,-3.81; 6 3.81,-3.81; 7 6.35,-3.81; 8 8.89,-3.81; 9 8.89,3.81; 10 6.35,3.81; 11 3.81,3.81; 12 1.27,3.81; 13 -1.27,3.81; 14 -3.81,3.81; 15 -6.35,3.81; 16 -8.89,3.81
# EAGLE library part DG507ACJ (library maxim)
MULTIPLEXER

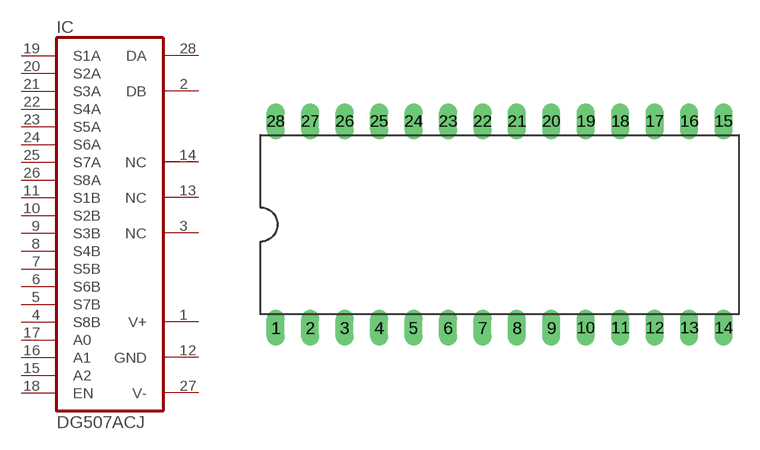
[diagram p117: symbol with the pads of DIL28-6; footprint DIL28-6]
Designator prefix IC

## DG507ACJ (MPN: DG507ACJ+; OC_FARNELL: 1077079; OC_NEWARK: 18M9071)  [DIL28-6]
1  V+  pwr
2  DB  pas
3  NC  nc
4  S8B  pas
5  S7B  pas
6  S6B  pas
7  S5B  pas
8  S4B  pas
9  S3B  pas
10  S2B  pas
11  S1B  pas
12  GND  pwr
13  NC  nc
14  NC  nc
15  A2  in
16  A1  in
17  A0  in
18  EN  in
19  S1A  pas
20  S2A  pas
21  S3A  pas
22  S4A  pas
23  S5A  pas
24  S6A  pas
25  S7A  pas
26  S8A  pas
27  V-  pwr
28  DA  pas

## Footprint DIL28-6 (pad centres in mm)
Dual In Line Package 0.6 inch
drill 0.813 long: 1 -16.51,-7.62; 2 -13.97,-7.62; 3 -11.43,-7.62; 4 -8.89,-7.62; 5 -6.35,-7.62; 6 -3.81,-7.62; 7 -1.27,-7.62; 8 1.27,-7.62; 9 3.81,-7.62; 10 6.35,-7.62; 11 8.89,-7.62; 12 11.43,-7.62; 13 13.97,-7.62; 14 16.51,-7.62; 15 16.51,7.62; 16 13.97,7.62; 17 11.43,7.62; 18 8.89,7.62; 19 6.35,7.62; 20 3.81,7.62; 21 1.27,7.62; 22 -1.27,7.62; 23 -3.81,7.62; 24 -6.35,7.62; 25 -8.89,7.62; 26 -11.43,7.62; 27 -13.97,7.62; 28 -16.51,7.62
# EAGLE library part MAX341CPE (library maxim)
ANALOG SWITCH

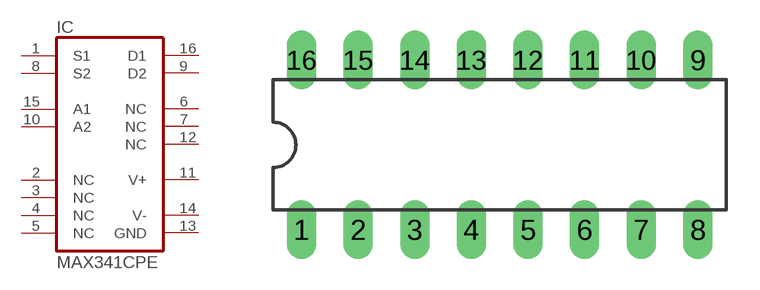
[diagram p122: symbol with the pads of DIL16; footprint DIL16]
Designator prefix IC

## MAX341CPE (OC_FARNELL: unknown; OC_NEWARK: unknown)  [DIL16]
1  S1  pas
2  NC  nc
3  NC  nc
4  NC  nc
5  NC  nc
6  NC  nc
7  NC  nc
8  S2  pas
9  D2  pas
10  A2  in
11  V+  pwr
12  NC  nc
13  GND  pwr
14  V-  pwr
15  A1  in
16  D1  pas

## Footprint DIL16 (pad centres in mm)
Dual In Line Package
drill 0.813 long: 1 -8.89,-3.81; 2 -6.35,-3.81; 3 -3.81,-3.81; 4 -1.27,-3.81; 5 1.27,-3.81; 6 3.81,-3.81; 7 6.35,-3.81; 8 8.89,-3.81; 9 8.89,3.81; 10 6.35,3.81; 11 3.81,3.81; 12 1.27,3.81; 13 -1.27,3.81; 14 -3.81,3.81; 15 -6.35,3.81; 16 -8.89,3.81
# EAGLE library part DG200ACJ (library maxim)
ANALOG SWITCH

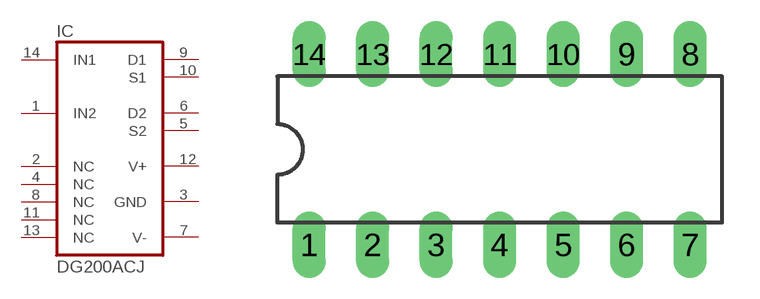
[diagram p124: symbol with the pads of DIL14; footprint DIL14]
Designator prefix IC

## DG200ACJ (OC_FARNELL: unknown; OC_NEWARK: 77C6395)  [DIL14]
1  IN2  in
2  NC  nc
3  GND  pwr
4  NC  nc
5  S2  pas
6  D2  pas
7  V-  pwr
8  NC  nc
9  D1  pas
10  S1  pas
11  NC  nc
12  V+  pwr
13  NC  nc
14  IN1  in

## Footprint DIL14 (pad centres in mm)
Dual In Line Package
drill 0.813 long: 1 -7.62,-3.81; 2 -5.08,-3.81; 3 -2.54,-3.81; 4 0,-3.81; 5 2.54,-3.81; 6 5.08,-3.81; 7 7.62,-3.81; 8 7.62,3.81; 9 5.08,3.81; 10 2.54,3.81; 11 0,3.81; 12 -2.54,3.81; 13 -5.08,3.81; 14 -7.62,3.81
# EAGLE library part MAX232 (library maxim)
RS232 TRANSCEIVER

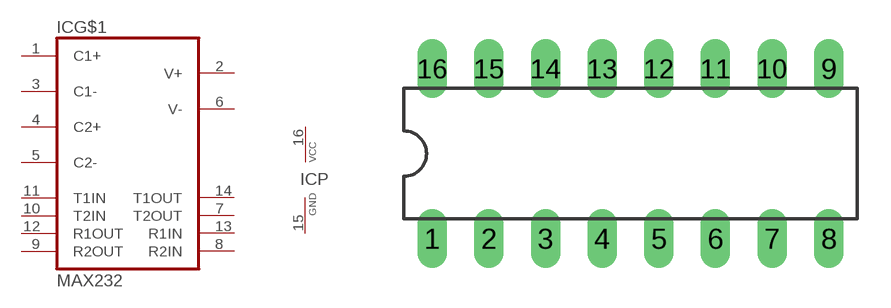
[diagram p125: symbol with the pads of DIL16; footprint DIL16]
Designator prefix IC; gates G$1=MAX232 P=VCC-GND

## MAX232 (MF: MAXIM; MPN: MAX232ACPE+; OC_FARNELL: 9723773; OC_NEWARK: 68K4544)  [DIL16]
1  G$1:C1+
2  G$1:V+
3  G$1:C1-
4  G$1:C2+
5  G$1:C2-
6  G$1:V-
7  G$1:T2OUT  out
8  G$1:R2IN  in
9  G$1:R2OUT  out
10  G$1:T2IN  in
11  G$1:T1IN  in
12  G$1:R1OUT  out
13  G$1:R1IN  in
14  G$1:T1OUT  out
15  P:GND  pwr
16  P:VCC  pwr

## Footprint DIL16 (pad centres in mm)
Dual In Line Package
drill 0.813 long: 1 -8.89,-3.81; 2 -6.35,-3.81; 3 -3.81,-3.81; 4 -1.27,-3.81; 5 1.27,-3.81; 6 3.81,-3.81; 7 6.35,-3.81; 8 8.89,-3.81; 9 8.89,3.81; 10 6.35,3.81; 11 3.81,3.81; 12 1.27,3.81; 13 -1.27,3.81; 14 -3.81,3.81; 15 -6.35,3.81; 16 -8.89,3.81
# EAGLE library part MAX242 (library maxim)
RS232 TRANSCEIVER

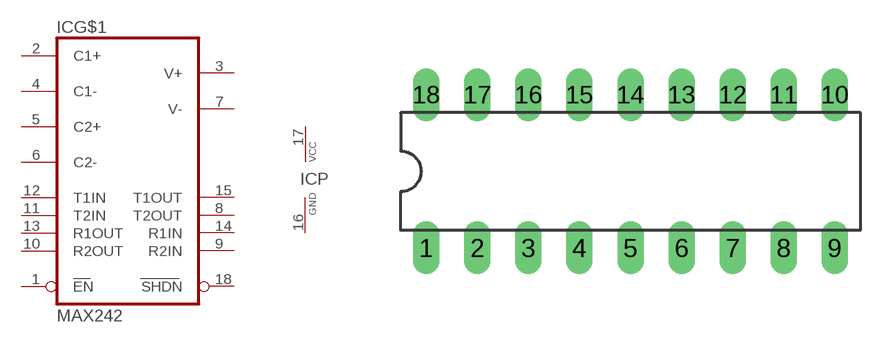
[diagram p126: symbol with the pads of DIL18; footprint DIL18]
Designator prefix IC; gates G$1=MAX242 P=VCC-GND

## MAX242 (MPN: MAX242CPN+; OC_FARNELL: unknown; OC_NEWARK: 99K3109)  [DIL18]
1  G$1:EN  pas
2  G$1:C1+
3  G$1:V+
4  G$1:C1-
5  G$1:C2+
6  G$1:C2-
7  G$1:V-
8  G$1:T2OUT  out
9  G$1:R2IN  in
10  G$1:R2OUT  out
11  G$1:T2IN  in
12  G$1:T1IN  in
13  G$1:R1OUT  out
14  G$1:R1IN  in
15  G$1:T1OUT  out
16  P:GND  pwr
17  P:VCC  pwr
18  G$1:SHDN  pas

## Footprint DIL18 (pad centres in mm)
Dual In Line Package
drill 0.813 long: 1 -10.16,-3.81; 2 -7.62,-3.81; 3 -5.08,-3.81; 4 -2.54,-3.81; 5 0,-3.81; 6 2.54,-3.81; 7 5.08,-3.81; 8 7.62,-3.81; 9 10.16,-3.81; 10 10.16,3.81; 11 7.62,3.81; 12 5.08,3.81; 13 2.54,3.81; 14 0,3.81; 15 -2.54,3.81; 16 -5.08,3.81; 17 -7.62,3.81; 18 -10.16,3.81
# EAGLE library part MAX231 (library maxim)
RS232 TRANSCEIVER

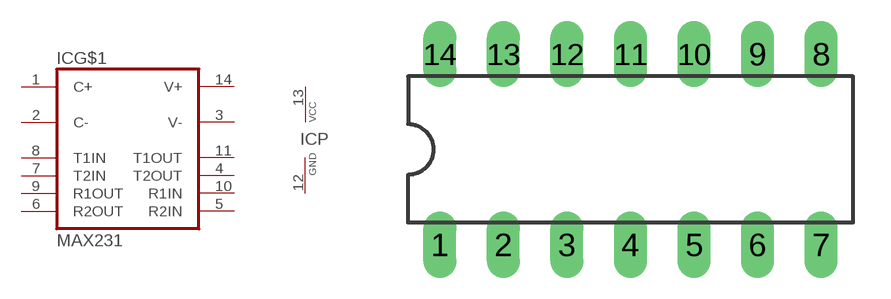
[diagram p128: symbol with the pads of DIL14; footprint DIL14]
Designator prefix IC; gates G$1=MAX231 P=VCC-GND

## MAX231 (MF: MAXIM; MPN: MAX231CPD+; OC_FARNELL: 9725164; OC_NEWARK: 28K3272)  [DIL14]
1  G$1:C+
2  G$1:C-
3  G$1:V-
4  G$1:T2OUT  out
5  G$1:R2IN  in
6  G$1:R2OUT  out
7  G$1:T2IN  in
8  G$1:T1IN  in
9  G$1:R1OUT  out
10  G$1:R1IN  in
11  G$1:T1OUT  out
12  P:GND  pwr
13  P:VCC  pwr
14  G$1:V+

## Footprint DIL14 (pad centres in mm)
Dual In Line Package
drill 0.813 long: 1 -7.62,-3.81; 2 -5.08,-3.81; 3 -2.54,-3.81; 4 0,-3.81; 5 2.54,-3.81; 6 5.08,-3.81; 7 7.62,-3.81; 8 7.62,3.81; 9 5.08,3.81; 10 2.54,3.81; 11 0,3.81; 12 -2.54,3.81; 13 -5.08,3.81; 14 -7.62,3.81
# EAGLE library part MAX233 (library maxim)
RS232 TRANSCEIVER

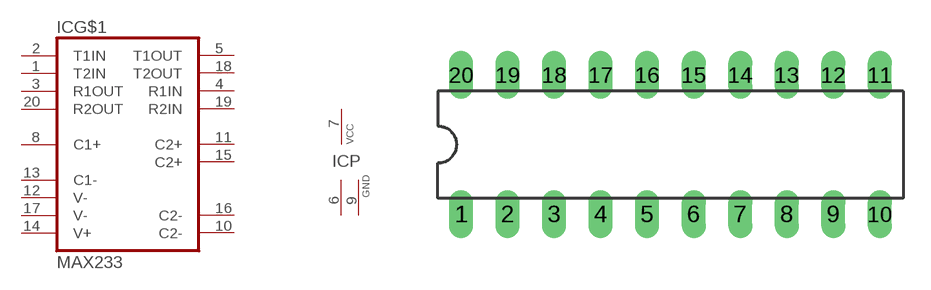
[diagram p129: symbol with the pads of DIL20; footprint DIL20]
Designator prefix IC; gates G$1=MAX233 P=PWR2GND

## MAX233 (MPN: MAX233ACPP+G36; OC_FARNELL: 1593332; OC_NEWARK: 89K3459)  [DIL20]
1  G$1:T2IN  in
2  G$1:T1IN  in
3  G$1:R1OUT  out
4  G$1:R1IN  in
5  G$1:T1OUT  out
6  P:GND  pwr
7  P:VCC  pwr
8  G$1:C1+
9  P:GND  pwr
10  G$1:C2-
11  G$1:C2+
12  G$1:V-
13  G$1:C1-
14  G$1:V+
15  G$1:C2+
16  G$1:C2-
17  G$1:V-
18  G$1:T2OUT  out
19  G$1:R2IN  in
20  G$1:R2OUT  out

## Footprint DIL20 (pad centres in mm)
Dual In Line Package
drill 0.813 long: 1 -11.43,-3.81; 2 -8.89,-3.81; 3 -6.35,-3.81; 4 -3.81,-3.81; 5 -1.27,-3.81; 6 1.27,-3.81; 7 3.81,-3.81; 8 6.35,-3.81; 9 8.89,-3.81; 10 11.43,-3.81; 11 11.43,3.81; 12 8.89,3.81; 13 6.35,3.81; 14 3.81,3.81; 15 1.27,3.81; 16 -1.27,3.81; 17 -3.81,3.81; 18 -6.35,3.81; 19 -8.89,3.81; 20 -11.43,3.81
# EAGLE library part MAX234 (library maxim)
RS232 TRANSMITTER

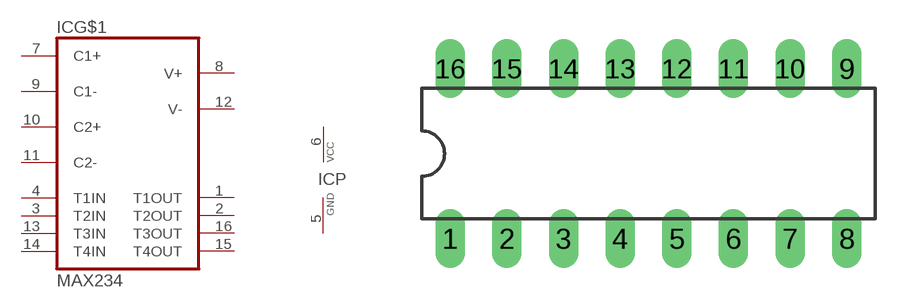
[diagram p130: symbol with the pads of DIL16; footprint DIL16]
Designator prefix IC; gates G$1=MAX234 P=VCC-GND

## MAX234 (MPN: MAX234CPE+; OC_FARNELL: 1187976; OC_NEWARK: 65K6773)  [DIL16]
1  G$1:T1OUT  out
2  G$1:T2OUT  out
3  G$1:T2IN  in
4  G$1:T1IN  in
5  P:GND  pwr
6  P:VCC  pwr
7  G$1:C1+
8  G$1:V+
9  G$1:C1-
10  G$1:C2+
11  G$1:C2-
12  G$1:V-
13  G$1:T3IN  in
14  G$1:T4IN  in
15  G$1:T4OUT  out
16  G$1:T3OUT  out

## Footprint DIL16 (pad centres in mm)
Dual In Line Package
drill 0.813 long: 1 -8.89,-3.81; 2 -6.35,-3.81; 3 -3.81,-3.81; 4 -1.27,-3.81; 5 1.27,-3.81; 6 3.81,-3.81; 7 6.35,-3.81; 8 8.89,-3.81; 9 8.89,3.81; 10 6.35,3.81; 11 3.81,3.81; 12 1.27,3.81; 13 -1.27,3.81; 14 -3.81,3.81; 15 -6.35,3.81; 16 -8.89,3.81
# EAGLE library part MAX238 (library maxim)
RS232 TRANSCEIVER

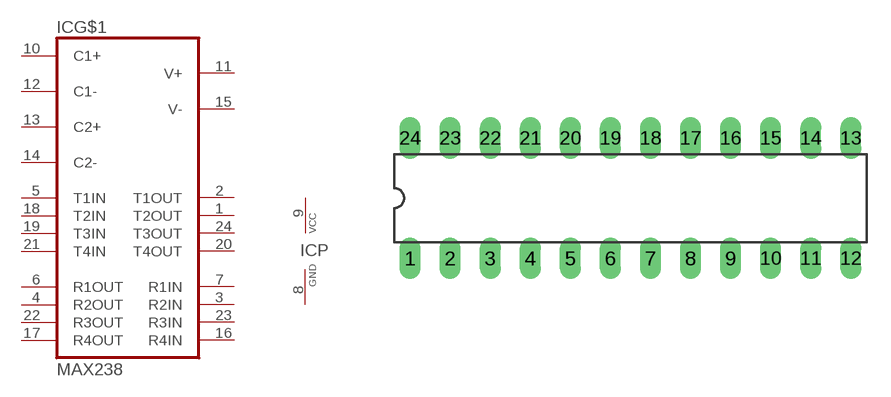
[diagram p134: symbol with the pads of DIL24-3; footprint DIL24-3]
Designator prefix IC; gates G$1=MAX238 P=VCC-GND

## MAX238 (OC_FARNELL: 9725180; OC_NEWARK: unknown)  [DIL24-3]
1  G$1:T2OUT  out
2  G$1:T1OUT  out
3  G$1:R2IN  in
4  G$1:R2OUT  out
5  G$1:T1IN  in
6  G$1:R1OUT  out
7  G$1:R1IN  in
8  P:GND  pwr
9  P:VCC  pwr
10  G$1:C1+
11  G$1:V+
12  G$1:C1-
13  G$1:C2+
14  G$1:C2-
15  G$1:V-
16  G$1:R4IN  in
17  G$1:R4OUT  out
18  G$1:T2IN  in
19  G$1:T3IN  in
20  G$1:T4OUT  out
21  G$1:T4IN  in
22  G$1:R3OUT  out
23  G$1:R3IN  in
24  G$1:T3OUT  out

## Footprint DIL24-3 (pad centres in mm)
Dual In Line Package 0.3 inch
drill 0.813 long: 1 -13.97,-3.81; 2 -11.43,-3.81; 3 -8.89,-3.81; 4 -6.35,-3.81; 5 -3.81,-3.81; 6 -1.27,-3.81; 7 1.27,-3.81; 8 3.81,-3.81; 9 6.35,-3.81; 10 8.89,-3.81; 11 11.43,-3.81; 12 13.97,-3.81; 13 13.97,3.81; 14 11.43,3.81; 15 8.89,3.81; 16 6.35,3.81; 17 3.81,3.81; 18 1.27,3.81; 19 -1.27,3.81; 20 -3.81,3.81; 21 -6.35,3.81; 22 -8.89,3.81; 23 -11.43,3.81; 24 -13.97,3.81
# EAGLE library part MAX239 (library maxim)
RS232 TRANSCEIVER

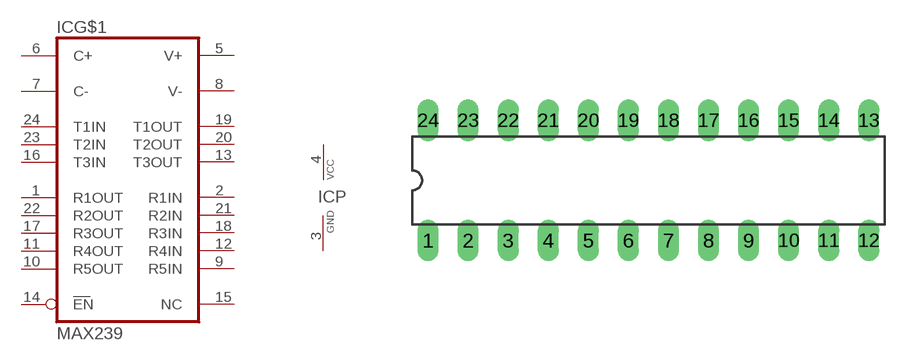
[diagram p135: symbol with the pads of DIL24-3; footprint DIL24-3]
Designator prefix IC; gates P=VCC-GND G$1=MAX239

## MAX239 (MF: MAXIM; MPN: MAX239CNG+; OC_FARNELL: unknown; OC_NEWARK: 37K7894)  [DIL24-3]
1  G$1:R1OUT  out
2  G$1:R1IN  in
3  P:GND  pwr
4  P:VCC  pwr
5  G$1:V+  pas
6  G$1:C+
7  G$1:C-
8  G$1:V-
9  G$1:R5IN  in
10  G$1:R5OUT  out
11  G$1:R4OUT  out
12  G$1:R4IN  in
13  G$1:T3OUT  out
14  G$1:EN  pas
15  G$1:NC  nc
16  G$1:T3IN  in
17  G$1:R3OUT  out
18  G$1:R3IN  in
19  G$1:T1OUT  out
20  G$1:T2OUT  out
21  G$1:R2IN  in
22  G$1:R2OUT  out
23  G$1:T2IN  in
24  G$1:T1IN  in

## Footprint DIL24-3 (pad centres in mm)
Dual In Line Package 0.3 inch
drill 0.813 long: 1 -13.97,-3.81; 2 -11.43,-3.81; 3 -8.89,-3.81; 4 -6.35,-3.81; 5 -3.81,-3.81; 6 -1.27,-3.81; 7 1.27,-3.81; 8 3.81,-3.81; 9 6.35,-3.81; 10 8.89,-3.81; 11 11.43,-3.81; 12 13.97,-3.81; 13 13.97,3.81; 14 11.43,3.81; 15 8.89,3.81; 16 6.35,3.81; 17 3.81,3.81; 18 1.27,3.81; 19 -1.27,3.81; 20 -3.81,3.81; 21 -6.35,3.81; 22 -8.89,3.81; 23 -11.43,3.81; 24 -13.97,3.81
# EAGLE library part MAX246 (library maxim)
RS232 TRANSCEIVER

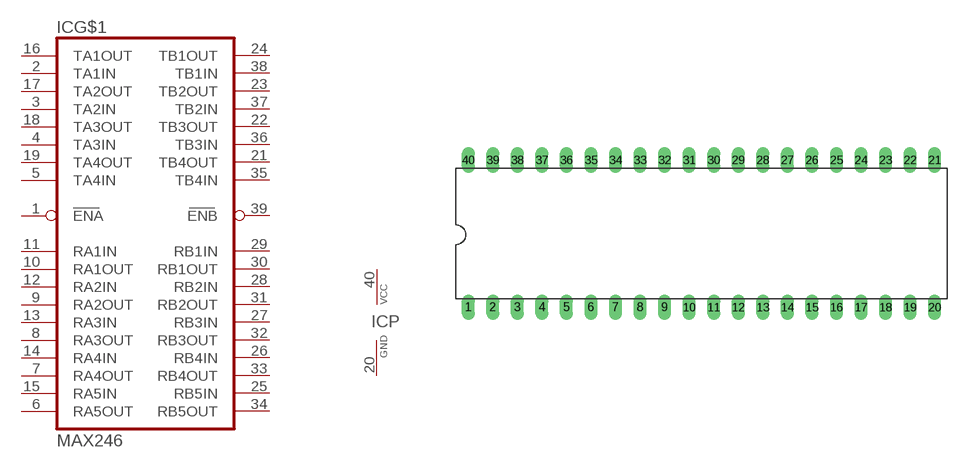
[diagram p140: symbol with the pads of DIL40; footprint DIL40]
Designator prefix IC; gates G$1=MAX246 P=VCC-GND

## MAX246 (OC_FARNELL: unknown; OC_NEWARK: unknown)  [DIL40]
1  G$1:ENA  pas
2  G$1:TA1IN  in
3  G$1:TA2IN  in
4  G$1:TA3IN  in
5  G$1:TA4IN  in
6  G$1:RA5OUT  out
7  G$1:RA4OUT  out
8  G$1:RA3OUT  out
9  G$1:RA2OUT  out
10  G$1:RA1OUT  out
11  G$1:RA1IN  in
12  G$1:RA2IN  in
13  G$1:RA3IN  in
14  G$1:RA4IN  in
15  G$1:RA5IN  in
16  G$1:TA1OUT  out
17  G$1:TA2OUT  out
18  G$1:TA3OUT  out
19  G$1:TA4OUT  out
20  P:GND  pwr
21  G$1:TB4OUT  out
22  G$1:TB3OUT  out
23  G$1:TB2OUT  out
24  G$1:TB1OUT  out
25  G$1:RB5IN  in
26  G$1:RB4IN  in
27  G$1:RB3IN  in
28  G$1:RB2IN  in
29  G$1:RB1IN  in
30  G$1:RB1OUT  out
31  G$1:RB2OUT  out
32  G$1:RB3OUT  out
33  G$1:RB4OUT  out
34  G$1:RB5OUT  out
35  G$1:TB4IN  in
36  G$1:TB3IN  in
37  G$1:TB2IN  in
38  G$1:TB1IN  in
39  G$1:ENB  pas
40  P:VCC  pwr

## Footprint DIL40 (pad centres in mm)
Dual In Line Package
drill 0.813 long: 1 -24.13,-7.62; 2 -21.59,-7.62; 3 -19.05,-7.62; 4 -16.51,-7.62; 5 -13.97,-7.62; 6 -11.43,-7.62; 7 -8.89,-7.62; 8 -6.35,-7.62; 9 -3.81,-7.62; 10 -1.27,-7.62; 11 1.27,-7.62; 12 3.81,-7.62; 13 6.35,-7.62; 14 8.89,-7.62; 15 11.43,-7.62; 16 13.97,-7.62; 17 16.51,-7.62; 18 19.05,-7.62; 19 21.59,-7.62; 20 24.13,-7.62; 21 24.13,7.62; 22 21.59,7.62; 23 19.05,7.62; 24 16.51,7.62; 25 13.97,7.62; 26 11.43,7.62; 27 8.89,7.62; 28 6.35,7.62; 29 3.81,7.62; 30 1.27,7.62; 31 -1.27,7.62; 32 -3.81,7.62; 33 -6.35,7.62; 34 -8.89,7.62; 35 -11.43,7.62; 36 -13.97,7.62; 37 -16.51,7.62; 38 -19.05,7.62; 39 -21.59,7.62; 40 -24.13,7.62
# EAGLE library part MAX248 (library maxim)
RS232 TRANSCEIVER

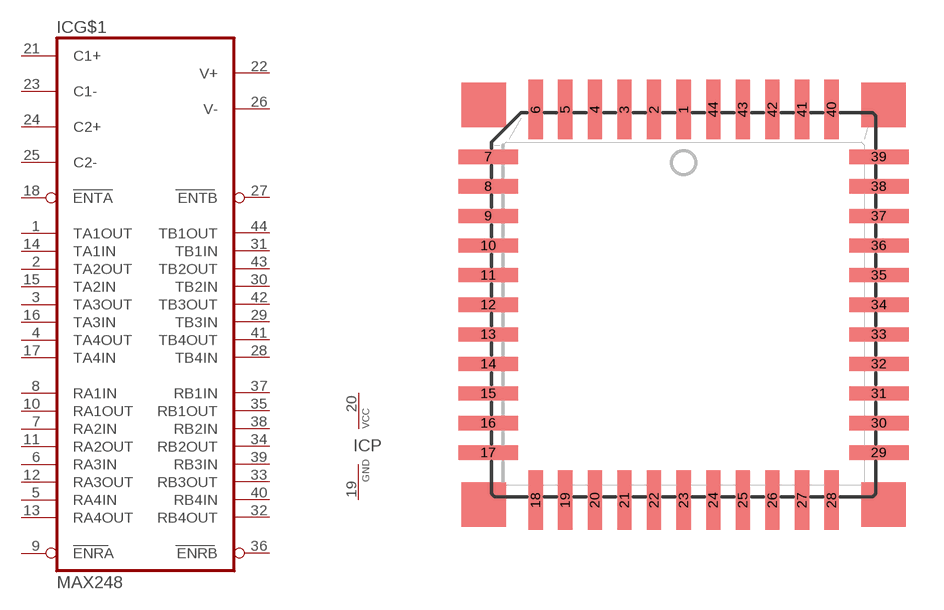
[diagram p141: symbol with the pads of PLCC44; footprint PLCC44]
Designator prefix IC; gates G$1=MAX248 P=VCC-GND

## MAX248 (MPN: MAX248CQH+D; OC_FARNELL: unknown; OC_NEWARK: 73K8523)  [PLCC44]
1  G$1:TA1OUT  out
2  G$1:TA2OUT  out
3  G$1:TA3OUT  out
4  G$1:TA4OUT  out
5  G$1:RA4IN  in
6  G$1:RA3IN  in
7  G$1:RA2IN  in
8  G$1:RA1IN  in
9  G$1:ENRA  pas
10  G$1:RA1OUT  out
11  G$1:RA2OUT  out
12  G$1:RA3OUT  out
13  G$1:RA4OUT  out
14  G$1:TA1IN  in
15  G$1:TA2IN  in
16  G$1:TA3IN  in
17  G$1:TA4IN  in
18  G$1:ENTA  pas
19  P:GND  pwr
20  P:VCC  pwr
21  G$1:C1+
22  G$1:V+
23  G$1:C1-
24  G$1:C2+
25  G$1:C2-
26  G$1:V-
27  G$1:ENTB  pas
28  G$1:TB4IN  in
29  G$1:TB3IN  in
30  G$1:TB2IN  in
31  G$1:TB1IN  in
32  G$1:RB4OUT  out
33  G$1:RB3OUT  out
34  G$1:RB2OUT  out
35  G$1:RB1OUT  out
36  G$1:ENRB  pas
37  G$1:RB1IN  in
38  G$1:RB2IN  in
39  G$1:RB3IN  in
40  G$1:RB4IN  in
41  G$1:TB4OUT  out
42  G$1:TB3OUT  out
43  G$1:TB2OUT  out
44  G$1:TB1OUT  out

## Footprint PLCC44 (pad centres in mm)
PLASTIC LEADED CHIP CARRIER square
smd 0.61 x 2.54: 1 0,8.382; 2 -1.27,8.382; 3 -2.54,8.382; 4 -3.81,8.382; 5 -5.08,8.382; 6 -6.35,8.382; 18 -6.35,-8.382; 19 -5.08,-8.382; 20 -3.81,-8.382; 21 -2.54,-8.382; 22 -1.27,-8.382; 23 0,-8.382; 24 1.27,-8.382; 25 2.54,-8.382; 26 3.81,-8.382; 27 5.08,-8.382; 28 6.35,-8.382; 40 6.35,8.382; 41 5.08,8.382; 42 3.81,8.382; 43 2.54,8.382; 44 1.27,8.382
smd 2.54 x 0.61: 7 -8.382,6.35; 8 -8.382,5.08; 9 -8.382,3.81; 10 -8.382,2.54; 11 -8.382,1.27; 12 -8.382,0; 13 -8.382,-1.27; 14 -8.382,-2.54; 15 -8.382,-3.81; 16 -8.382,-5.08; 17 -8.382,-6.35; 29 8.382,-6.35; 30 8.382,-5.08; 31 8.382,-3.81; 32 8.382,-2.54; 33 8.382,-1.27; 34 8.382,0; 35 8.382,1.27; 36 8.382,2.54; 37 8.382,3.81; 38 8.382,5.08; 39 8.382,6.35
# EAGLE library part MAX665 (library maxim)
Switched-capcitor VOLTAGE CONVERTER

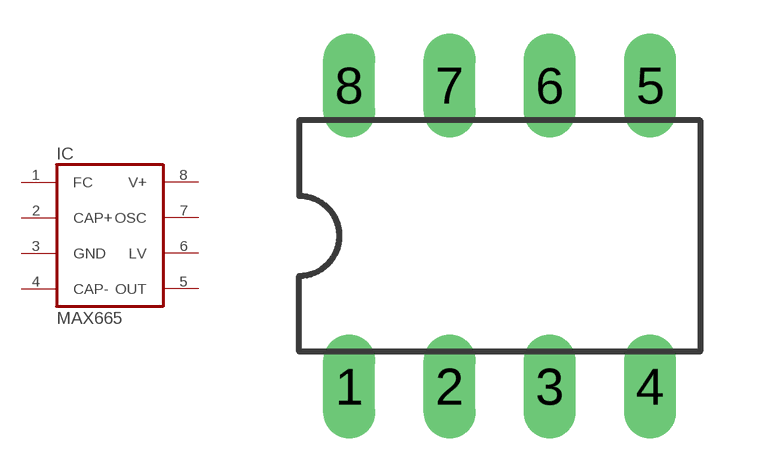
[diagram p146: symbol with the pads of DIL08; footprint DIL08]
Designator prefix IC

## MAX665 (MPN: MAX665CPA+; OC_FARNELL: 1673209; OC_NEWARK: 99K3600)  [DIL08]
1  FC  pas
2  CAP+
3  GND  pwr
4  CAP-
5  OUT  out
6  LV  pas
7  OSC  out
8  V+  pwr

## Footprint DIL08 (pad centres in mm)
Dual In Line Package
drill 0.813 long: 1 -3.81,-3.81; 2 -1.27,-3.81; 3 1.27,-3.81; 4 3.81,-3.81; 5 3.81,3.81; 6 1.27,3.81; 7 -1.27,3.81; 8 -3.81,3.81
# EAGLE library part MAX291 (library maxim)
DIGITAL FILTER

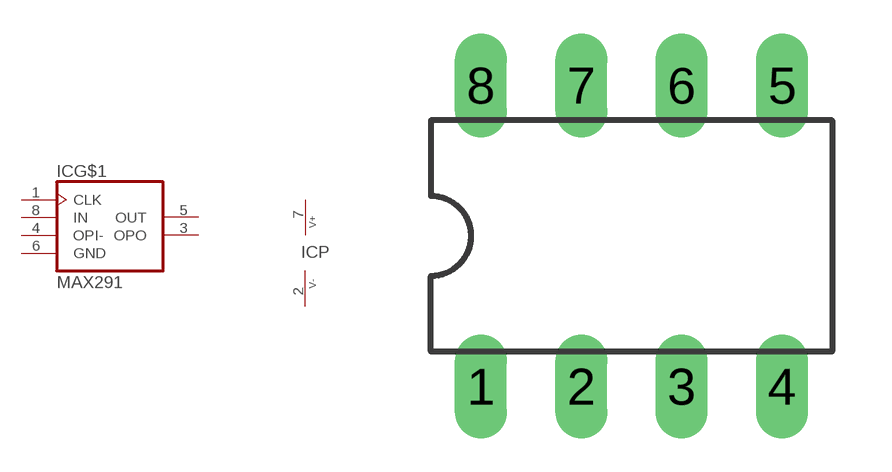
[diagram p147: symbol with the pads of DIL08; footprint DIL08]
Designator prefix IC; gates G$1=MAX291 P=PWR+-

## MAX291 (MPN: MAX291CPA+; OC_FARNELL: unknown; OC_NEWARK: 67K4526)  [DIL08]
1  G$1:CLK  in
2  P:V-  pwr
3  G$1:OPO  out
4  G$1:OPI-  in
5  G$1:OUT  out
6  G$1:GND  pwr
7  P:V+  pwr
8  G$1:IN  in

## Footprint DIL08 (pad centres in mm)
Dual In Line Package
drill 0.813 long: 1 -3.81,-3.81; 2 -1.27,-3.81; 3 1.27,-3.81; 4 3.81,-3.81; 5 3.81,3.81; 6 1.27,3.81; 7 -1.27,3.81; 8 -3.81,3.81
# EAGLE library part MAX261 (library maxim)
Switched-capacitor FILTER

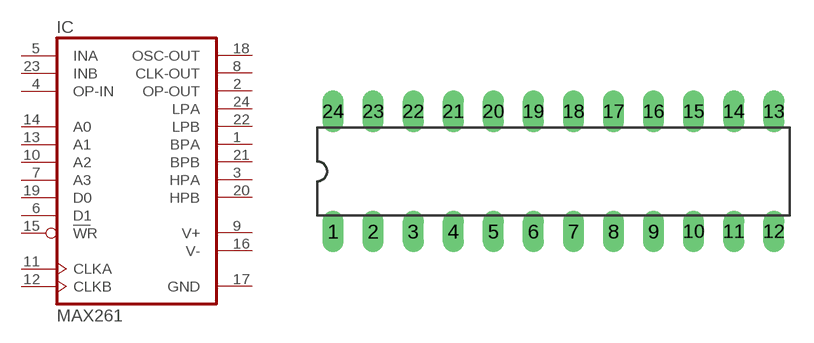
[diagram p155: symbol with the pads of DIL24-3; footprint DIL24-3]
Designator prefix IC

## MAX261 (MPN: MAX261BCNG+; OC_FARNELL: unknown; OC_NEWARK: 89K3470)  [DIL24-3]
1  BPA  out
2  OP-OUT  out
3  HPA  out
4  OP-IN  in
5  INA  in
6  D1  in
7  A3  in
8  CLK-OUT  out
9  V+  pwr
10  A2  in
11  CLKA  in
12  CLKB  in
13  A1  in
14  A0  in
15  WR  in
16  V-  pwr
17  GND  pwr
18  OSC-OUT  in
19  D0  in
20  HPB  out
21  BPB  out
22  LPB  out
23  INB  in
24  LPA  out

## Footprint DIL24-3 (pad centres in mm)
Dual In Line Package 0.3 inch
drill 0.813 long: 1 -13.97,-3.81; 2 -11.43,-3.81; 3 -8.89,-3.81; 4 -6.35,-3.81; 5 -3.81,-3.81; 6 -1.27,-3.81; 7 1.27,-3.81; 8 3.81,-3.81; 9 6.35,-3.81; 10 8.89,-3.81; 11 11.43,-3.81; 12 13.97,-3.81; 13 13.97,3.81; 14 11.43,3.81; 15 8.89,3.81; 16 6.35,3.81; 17 3.81,3.81; 18 1.27,3.81; 19 -1.27,3.81; 20 -3.81,3.81; 21 -6.35,3.81; 22 -8.89,3.81; 23 -11.43,3.81; 24 -13.97,3.81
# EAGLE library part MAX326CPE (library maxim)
ANALOG SWITCH

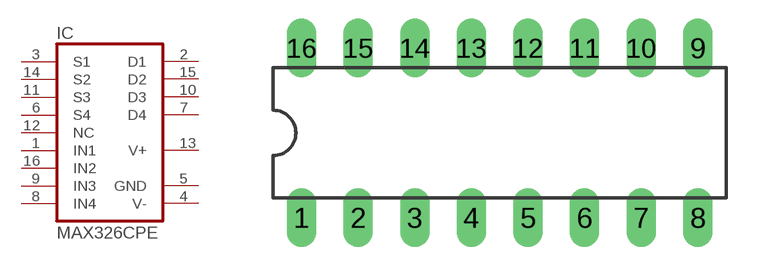
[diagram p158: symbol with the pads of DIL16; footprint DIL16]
Designator prefix IC

## MAX326CPE (MF: MAXIM; MPN: MAX326CPE+; OC_FARNELL: unknown; OC_NEWARK: 67K4921)  [DIL16]
1  IN1  in
2  D1  pas
3  S1  pas
4  V-  pwr
5  GND  pwr
6  S4  pas
7  D4  pas
8  IN4  in
9  IN3  in
10  D3  pas
11  S3  pas
12  NC  nc
13  V+  pwr
14  S2  pas
15  D2  pas
16  IN2  in

## Footprint DIL16 (pad centres in mm)
Dual In Line Package
drill 0.813 long: 1 -8.89,-3.81; 2 -6.35,-3.81; 3 -3.81,-3.81; 4 -1.27,-3.81; 5 1.27,-3.81; 6 3.81,-3.81; 7 6.35,-3.81; 8 8.89,-3.81; 9 8.89,3.81; 10 6.35,3.81; 11 3.81,3.81; 12 1.27,3.81; 13 -1.27,3.81; 14 -3.81,3.81; 15 -6.35,3.81; 16 -8.89,3.81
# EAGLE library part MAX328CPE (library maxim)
MULTIPLEXER

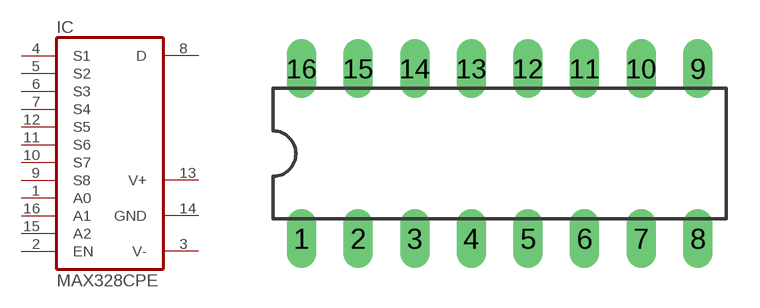
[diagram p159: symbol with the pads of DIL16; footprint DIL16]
Designator prefix IC

## MAX328CPE (MF: MAXIM; MPN: MAX328CPE; OC_FARNELL: unknown; OC_NEWARK: 34C3876)  [DIL16]
1  A0  in
2  EN  in
3  V-  pwr
4  S1  pas
5  S2  pas
6  S3  pas
7  S4  pas
8  D  pas
9  S8  pas
10  S7  pas
11  S6  pas
12  S5  pas
13  V+  pwr
14  GND  pwr
15  A2  in
16  A1  in

## Footprint DIL16 (pad centres in mm)
Dual In Line Package
drill 0.813 long: 1 -8.89,-3.81; 2 -6.35,-3.81; 3 -3.81,-3.81; 4 -1.27,-3.81; 5 1.27,-3.81; 6 3.81,-3.81; 7 6.35,-3.81; 8 8.89,-3.81; 9 8.89,3.81; 10 6.35,3.81; 11 3.81,3.81; 12 1.27,3.81; 13 -1.27,3.81; 14 -3.81,3.81; 15 -6.35,3.81; 16 -8.89,3.81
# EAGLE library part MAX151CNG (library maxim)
ANALOG/DIGITAL CONVERTER

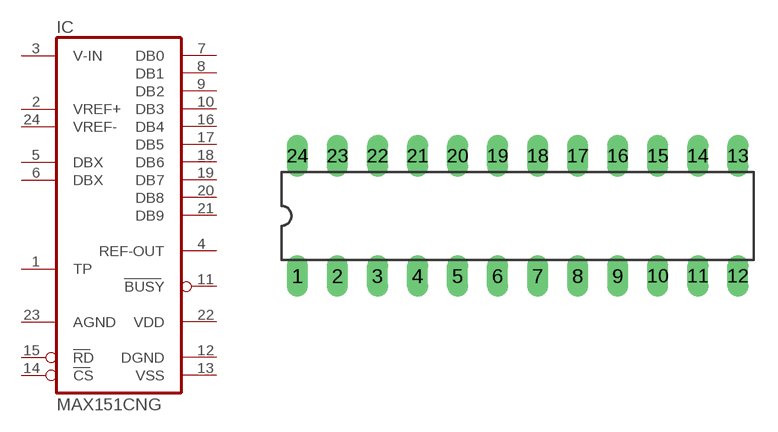
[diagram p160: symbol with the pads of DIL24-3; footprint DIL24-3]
Designator prefix IC

## MAX151CNG (OC_FARNELL: unknown; OC_NEWARK: unknown)  [DIL24-3]
1  TP  in
2  VREF+  in
3  V-IN  in
4  REF-OUT  out
5  DBX  pas
6  DBX  pas
7  DB0  hiz
8  DB1  hiz
9  DB2  hiz
10  DB3  hiz
11  BUSY  out
12  DGND  pwr
13  VSS  pwr
14  CS  in
15  RD  in
16  DB4  hiz
17  DB5  hiz
18  DB6  hiz
19  DB7  hiz
20  DB8  hiz
21  DB9  hiz
22  VDD  pwr
23  AGND  pwr
24  VREF-  in

## Footprint DIL24-3 (pad centres in mm)
Dual In Line Package 0.3 inch
drill 0.813 long: 1 -13.97,-3.81; 2 -11.43,-3.81; 3 -8.89,-3.81; 4 -6.35,-3.81; 5 -3.81,-3.81; 6 -1.27,-3.81; 7 1.27,-3.81; 8 3.81,-3.81; 9 6.35,-3.81; 10 8.89,-3.81; 11 11.43,-3.81; 12 13.97,-3.81; 13 13.97,3.81; 14 11.43,3.81; 15 8.89,3.81; 16 6.35,3.81; 17 3.81,3.81; 18 1.27,3.81; 19 -1.27,3.81; 20 -3.81,3.81; 21 -6.35,3.81; 22 -8.89,3.81; 23 -11.43,3.81; 24 -13.97,3.81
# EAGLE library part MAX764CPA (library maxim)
DC-DC CONVERTER

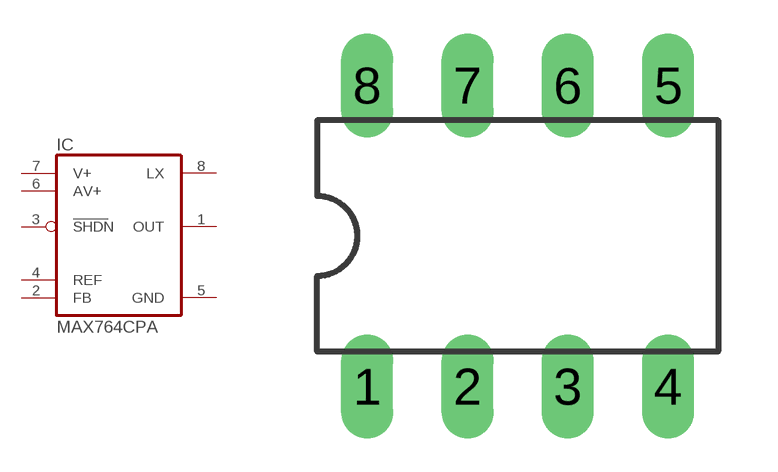
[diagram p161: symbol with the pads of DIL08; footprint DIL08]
Designator prefix IC

## MAX764CPA (MPN: MAX764CPA+; OC_FARNELL: 1422353; OC_NEWARK: 89K6221)  [DIL08]
1  OUT  sup
2  FB  in
3  SHDN  in
4  REF  in
5  GND  pwr
6  AV+  pwr
7  V+  pwr
8  LX  out

## Footprint DIL08 (pad centres in mm)
Dual In Line Package
drill 0.813 long: 1 -3.81,-3.81; 2 -1.27,-3.81; 3 1.27,-3.81; 4 3.81,-3.81; 5 3.81,3.81; 6 1.27,3.81; 7 -1.27,3.81; 8 -3.81,3.81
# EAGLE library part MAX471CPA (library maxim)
OP AMP

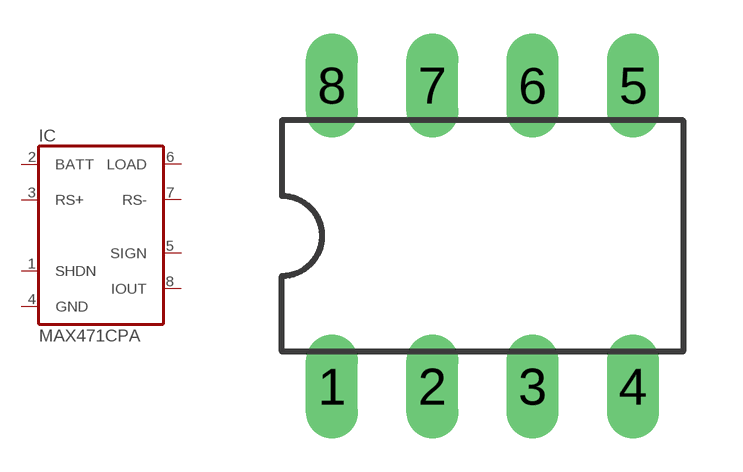
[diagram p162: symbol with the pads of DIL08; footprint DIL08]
Designator prefix IC

## MAX471CPA (OC_FARNELL: unknown; OC_NEWARK: unknown)  [DIL08]
1  SHDN  in
2  BATT  in
3  RS+  in
4  GND  pwr
5  SIGN  oc
6  LOAD  out
7  RS-  in
8  IOUT  out

## Footprint DIL08 (pad centres in mm)
Dual In Line Package
drill 0.813 long: 1 -3.81,-3.81; 2 -1.27,-3.81; 3 1.27,-3.81; 4 3.81,-3.81; 5 3.81,3.81; 6 1.27,3.81; 7 -1.27,3.81; 8 -3.81,3.81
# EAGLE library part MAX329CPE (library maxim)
MULTIPLEXER

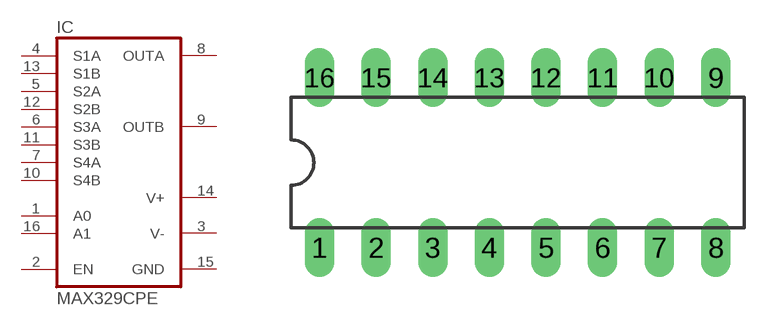
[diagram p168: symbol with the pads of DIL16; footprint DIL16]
Designator prefix IC

## MAX329CPE (MPN: MAX329CPE+; OC_FARNELL: unknown; OC_NEWARK: 99K3260)  [DIL16]
1  A0  in
2  EN  in
3  V-  pwr
4  S1A  pas
5  S2A  pas
6  S3A  pas
7  S4A  pas
8  OUTA  pas
9  OUTB  pas
10  S4B  pas
11  S3B  pas
12  S2B  pas
13  S1B  pas
14  V+  pwr
15  GND  pwr
16  A1  in

## Footprint DIL16 (pad centres in mm)
Dual In Line Package
drill 0.813 long: 1 -8.89,-3.81; 2 -6.35,-3.81; 3 -3.81,-3.81; 4 -1.27,-3.81; 5 1.27,-3.81; 6 3.81,-3.81; 7 6.35,-3.81; 8 8.89,-3.81; 9 8.89,3.81; 10 6.35,3.81; 11 3.81,3.81; 12 1.27,3.81; 13 -1.27,3.81; 14 -3.81,3.81; 15 -6.35,3.81; 16 -8.89,3.81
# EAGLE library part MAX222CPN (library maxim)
RS232 TRANSCEIVER

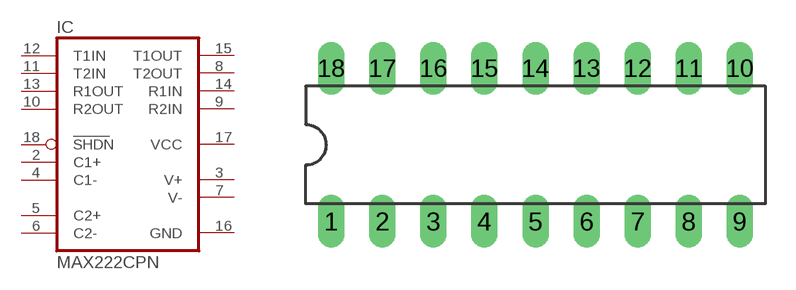
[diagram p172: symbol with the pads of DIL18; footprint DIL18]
Designator prefix IC

## MAX222CPN (MPN: MAX222CPN+; OC_FARNELL: 1187926; OC_NEWARK: 76K6649)  [DIL18]
2  C1+  pas
3  V+  sup
4  C1-  pas
5  C2+  pas
6  C2-  pas
7  V-  sup
8  T2OUT  out
9  R2IN  in
10  R2OUT  out
11  T2IN  in
12  T1IN  in
13  R1OUT  out
14  R1IN  in
15  T1OUT  out
16  GND  pwr
17  VCC  pwr
18  SHDN  in

## Footprint DIL18 (pad centres in mm)
Dual In Line Package
drill 0.813 long: 1 -10.16,-3.81; 2 -7.62,-3.81; 3 -5.08,-3.81; 4 -2.54,-3.81; 5 0,-3.81; 6 2.54,-3.81; 7 5.08,-3.81; 8 7.62,-3.81; 9 10.16,-3.81; 10 10.16,3.81; 11 7.62,3.81; 12 5.08,3.81; 13 2.54,3.81; 14 0,3.81; 15 -2.54,3.81; 16 -5.08,3.81; 17 -7.62,3.81; 18 -10.16,3.81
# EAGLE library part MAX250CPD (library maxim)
RS232 TRANSCEIVER

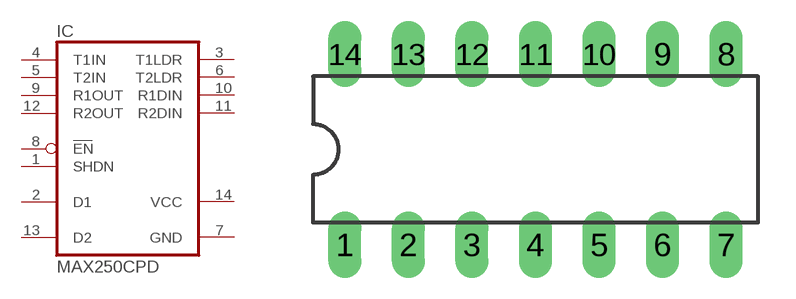
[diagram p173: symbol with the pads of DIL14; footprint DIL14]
Designator prefix IC

## MAX250CPD (MF: MAXIM; MPN: MAX250CPD+; OC_FARNELL: 9724540; OC_NEWARK: 67K4495)  [DIL14]
1  SHDN  in
2  D1  pas
3  T1LDR  out
4  T1IN  in
5  T2IN  in
6  T2LDR  out
7  GND  pwr
8  EN  in
9  R1OUT  out
10  R1DIN  in
11  R2DIN  in
12  R2OUT  out
13  D2  pas
14  VCC  pwr

## Footprint DIL14 (pad centres in mm)
Dual In Line Package
drill 0.813 long: 1 -7.62,-3.81; 2 -5.08,-3.81; 3 -2.54,-3.81; 4 0,-3.81; 5 2.54,-3.81; 6 5.08,-3.81; 7 7.62,-3.81; 8 7.62,3.81; 9 5.08,3.81; 10 2.54,3.81; 11 0,3.81; 12 -2.54,3.81; 13 -5.08,3.81; 14 -7.62,3.81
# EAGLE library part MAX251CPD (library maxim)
RS232 TRANSCEIVER

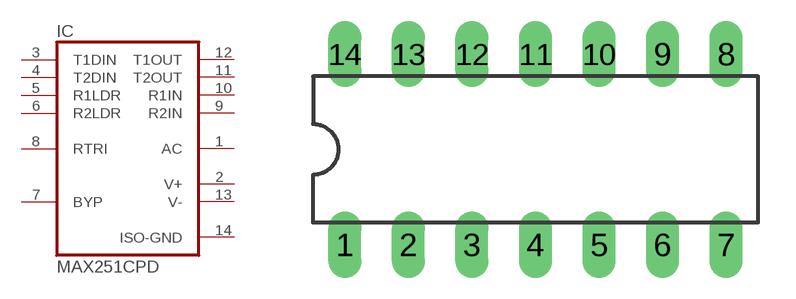
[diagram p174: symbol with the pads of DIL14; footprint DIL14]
Designator prefix IC

## MAX251CPD (MF: MAXIM; MPN: MAX251CPD+; OC_FARNELL: 9724931; OC_NEWARK: 68K4563)  [DIL14]
1  AC  pas
2  V+  sup
3  T1DIN  in
4  T2DIN  in
5  R1LDR  out
6  R2LDR  out
7  BYP  pas
8  RTRI  in
9  R2IN  in
10  R1IN  in
11  T2OUT  out
12  T1OUT  out
13  V-  sup
14  ISO-GND  pas

## Footprint DIL14 (pad centres in mm)
Dual In Line Package
drill 0.813 long: 1 -7.62,-3.81; 2 -5.08,-3.81; 3 -2.54,-3.81; 4 0,-3.81; 5 2.54,-3.81; 6 5.08,-3.81; 7 7.62,-3.81; 8 7.62,3.81; 9 5.08,3.81; 10 2.54,3.81; 11 0,3.81; 12 -2.54,3.81; 13 -5.08,3.81; 14 -7.62,3.81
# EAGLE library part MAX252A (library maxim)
RS232 TRANSCEIVER

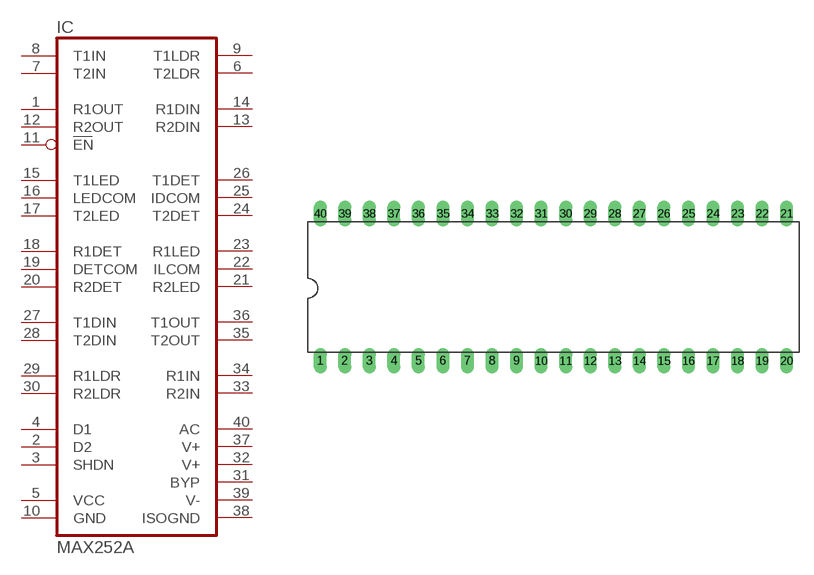
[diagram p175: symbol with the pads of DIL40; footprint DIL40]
Designator prefix IC

## MAX252A (OC_FARNELL: unknown; OC_NEWARK: unknown)  [DIL40]
1  R1OUT  out
2  D2  pas
3  SHDN  in
4  D1  pas
5  VCC  pwr
6  T2LDR  out
7  T2IN  in
8  T1IN  in
9  T1LDR  out
10  GND  pwr
11  EN  in
12  R2OUT  out
13  R2DIN  in
14  R1DIN  in
15  T1LED  pas
16  LEDCOM  pas
17  T2LED  pas
18  R1DET  pas
19  DETCOM  pas
20  R2DET  pas
21  R2LED  pas
22  ILCOM  pas
23  R1LED  pas
24  T2DET  pas
25  IDCOM  pas
26  T1DET  pas
27  T1DIN  in
28  T2DIN  in
29  R1LDR  out
30  R2LDR  out
31  BYP  pas
32  V+  sup
33  R2IN  in
34  R1IN  in
35  T2OUT  out
36  T1OUT  out
37  V+  sup
38  ISOGND  pwr
39  V-  sup
40  AC  pas

## Footprint DIL40 (pad centres in mm)
Dual In Line Package
drill 0.813 long: 1 -24.13,-7.62; 2 -21.59,-7.62; 3 -19.05,-7.62; 4 -16.51,-7.62; 5 -13.97,-7.62; 6 -11.43,-7.62; 7 -8.89,-7.62; 8 -6.35,-7.62; 9 -3.81,-7.62; 10 -1.27,-7.62; 11 1.27,-7.62; 12 3.81,-7.62; 13 6.35,-7.62; 14 8.89,-7.62; 15 11.43,-7.62; 16 13.97,-7.62; 17 16.51,-7.62; 18 19.05,-7.62; 19 21.59,-7.62; 20 24.13,-7.62; 21 24.13,7.62; 22 21.59,7.62; 23 19.05,7.62; 24 16.51,7.62; 25 13.97,7.62; 26 11.43,7.62; 27 8.89,7.62; 28 6.35,7.62; 29 3.81,7.62; 30 1.27,7.62; 31 -1.27,7.62; 32 -3.81,7.62; 33 -6.35,7.62; 34 -8.89,7.62; 35 -11.43,7.62; 36 -13.97,7.62; 37 -16.51,7.62; 38 -19.05,7.62; 39 -21.59,7.62; 40 -24.13,7.62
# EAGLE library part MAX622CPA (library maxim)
POWER SUPPLY

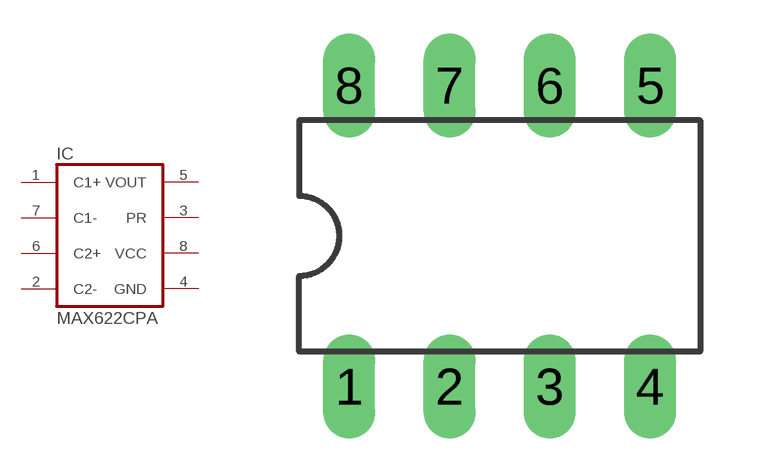
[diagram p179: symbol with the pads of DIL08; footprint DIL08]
Designator prefix IC

## MAX622CPA (OC_FARNELL: unknown; OC_NEWARK: unknown)  [DIL08]
1  C1+  pas
2  C2-  pas
3  PR  out
4  GND  pwr
5  VOUT  out
6  C2+  pas
7  C1-  pas
8  VCC  pwr

## Footprint DIL08 (pad centres in mm)
Dual In Line Package
drill 0.813 long: 1 -3.81,-3.81; 2 -1.27,-3.81; 3 1.27,-3.81; 4 3.81,-3.81; 5 3.81,3.81; 6 1.27,3.81; 7 -1.27,3.81; 8 -3.81,3.81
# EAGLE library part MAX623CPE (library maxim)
POWER SUPPLY

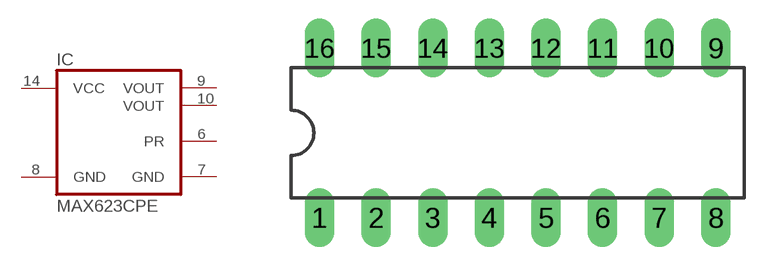
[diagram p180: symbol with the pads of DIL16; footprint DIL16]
Designator prefix IC

## MAX623CPE (OC_FARNELL: unknown; OC_NEWARK: unknown)  [DIL16]
6  PR  out
7  GND  pwr
8  GND  pwr
9  VOUT  out
10  VOUT  out
14  VCC  pwr

## Footprint DIL16 (pad centres in mm)
Dual In Line Package
drill 0.813 long: 1 -8.89,-3.81; 2 -6.35,-3.81; 3 -3.81,-3.81; 4 -1.27,-3.81; 5 1.27,-3.81; 6 3.81,-3.81; 7 6.35,-3.81; 8 8.89,-3.81; 9 8.89,3.81; 10 6.35,3.81; 11 3.81,3.81; 12 1.27,3.81; 13 -1.27,3.81; 14 -3.81,3.81; 15 -6.35,3.81; 16 -8.89,3.81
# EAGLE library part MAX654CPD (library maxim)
Step-up DC-DC CONVERTER

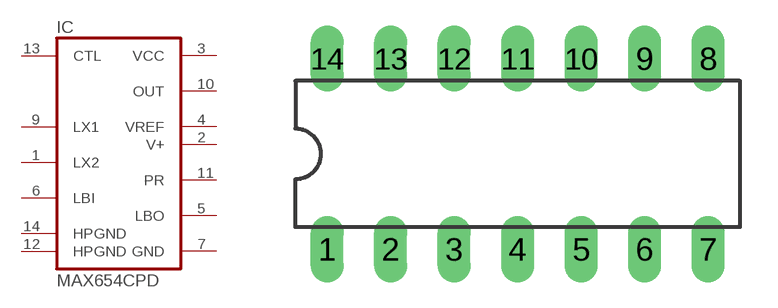
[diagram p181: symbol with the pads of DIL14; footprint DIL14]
Designator prefix IC

## MAX654CPD (OC_FARNELL: unknown; OC_NEWARK: unknown)  [DIL14]
1  LX2  pas
2  V+  sup
3  VCC  pwr
4  VREF  sup
5  LBO  out
6  LBI  in
7  GND  pwr
9  LX1  pas
10  OUT  sup
11  PR  out
12  HPGND  pas
13  CTL  in
14  HPGND  pas

## Footprint DIL14 (pad centres in mm)
Dual In Line Package
drill 0.813 long: 1 -7.62,-3.81; 2 -5.08,-3.81; 3 -2.54,-3.81; 4 0,-3.81; 5 2.54,-3.81; 6 5.08,-3.81; 7 7.62,-3.81; 8 7.62,3.81; 9 5.08,3.81; 10 2.54,3.81; 11 0,3.81; 12 -2.54,3.81; 13 -5.08,3.81; 14 -7.62,3.81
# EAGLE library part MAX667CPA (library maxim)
Positive VOLTAGE REGULATOR

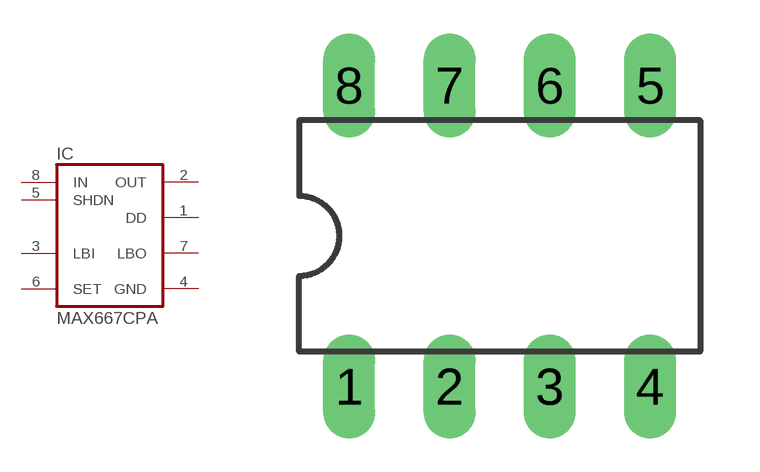
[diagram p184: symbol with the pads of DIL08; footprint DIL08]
Designator prefix IC

## MAX667CPA (MF: MAXIM; MPN: MAX667CPA; OC_FARNELL: 1187967; OC_NEWARK: 34C3972)  [DIL08]
1  DD  pas
2  OUT  sup
3  LBI  in
4  GND  pwr
5  SHDN  in
6  SET  in
7  LBO  pas
8  IN  in

## Footprint DIL08 (pad centres in mm)
Dual In Line Package
drill 0.813 long: 1 -3.81,-3.81; 2 -1.27,-3.81; 3 1.27,-3.81; 4 3.81,-3.81; 5 3.81,3.81; 6 1.27,3.81; 7 -1.27,3.81; 8 -3.81,3.81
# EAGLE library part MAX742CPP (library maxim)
PWM SWITCH-MODE REGULATOR

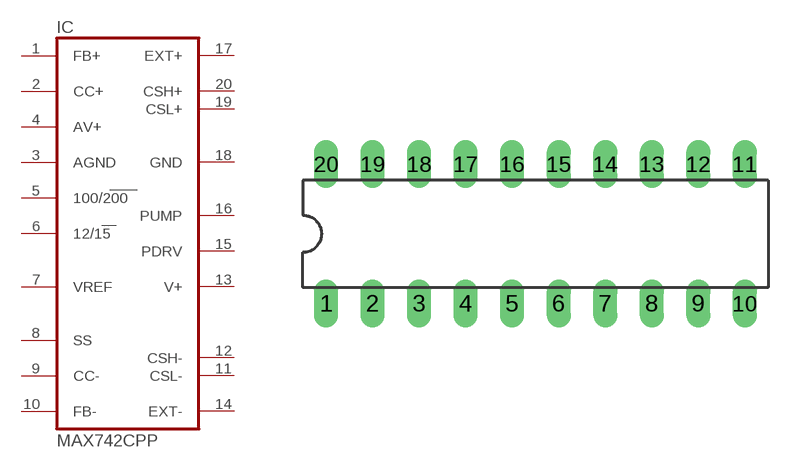
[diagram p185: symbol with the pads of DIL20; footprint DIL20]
Designator prefix IC

## MAX742CPP (MF: MAXIM; MPN: MAX742CPP; OC_FARNELL: unknown; OC_NEWARK: 79C2211)  [DIL20]
1  FB+  in
2  CC+  pas
3  AGND  pwr
4  AV+  in
5  100/200  in
6  12/15  in
7  VREF  sup
8  SS  pas
9  CC-  pas
10  FB-  in
11  CSL-  in
12  CSH-  in
13  V+  in
14  EXT-  hiz
15  PDRV  in
16  PUMP  out
17  EXT+  hiz
18  GND  pwr
19  CSL+  in
20  CSH+  in

## Footprint DIL20 (pad centres in mm)
Dual In Line Package
drill 0.813 long: 1 -11.43,-3.81; 2 -8.89,-3.81; 3 -6.35,-3.81; 4 -3.81,-3.81; 5 -1.27,-3.81; 6 1.27,-3.81; 7 3.81,-3.81; 8 6.35,-3.81; 9 8.89,-3.81; 10 11.43,-3.81; 11 11.43,3.81; 12 8.89,3.81; 13 6.35,3.81; 14 3.81,3.81; 15 1.27,3.81; 16 -1.27,3.81; 17 -3.81,3.81; 18 -6.35,3.81; 19 -8.89,3.81; 20 -11.43,3.81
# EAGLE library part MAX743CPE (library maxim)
PWM SWITCH-MODE REGULATORr

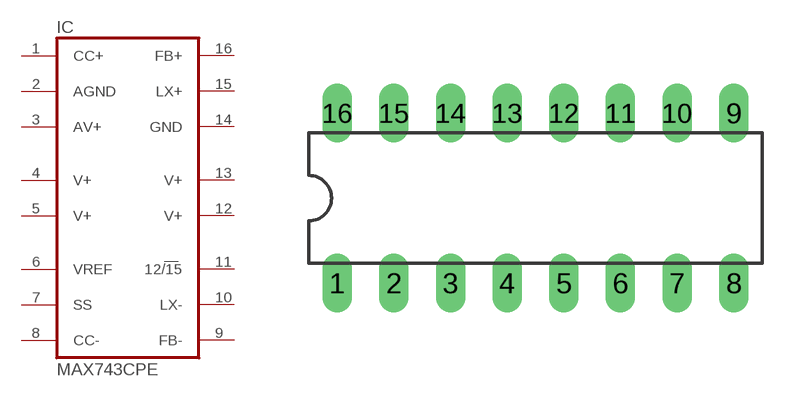
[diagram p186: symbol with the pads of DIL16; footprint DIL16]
Designator prefix IC

## MAX743CPE (MF: MAXIM; MPN: MAX743CPE; OC_FARNELL: 1187931; OC_NEWARK: 79C2246)  [DIL16]
1  CC+  pas
2  AGND  pwr
3  AV+  in
4  V+  in
5  V+  in
6  VREF  sup
7  SS  pas
8  CC-  pas
9  FB-  in
10  LX-  pas
11  12/15  in
12  V+  in
13  V+  in
14  GND  pwr
15  LX+  pas
16  FB+  in

## Footprint DIL16 (pad centres in mm)
Dual In Line Package
drill 0.813 long: 1 -8.89,-3.81; 2 -6.35,-3.81; 3 -3.81,-3.81; 4 -1.27,-3.81; 5 1.27,-3.81; 6 3.81,-3.81; 7 6.35,-3.81; 8 8.89,-3.81; 9 8.89,3.81; 10 6.35,3.81; 11 3.81,3.81; 12 1.27,3.81; 13 -1.27,3.81; 14 -3.81,3.81; 15 -6.35,3.81; 16 -8.89,3.81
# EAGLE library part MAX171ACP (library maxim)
ANALOG/DIGITAL CONVERTER

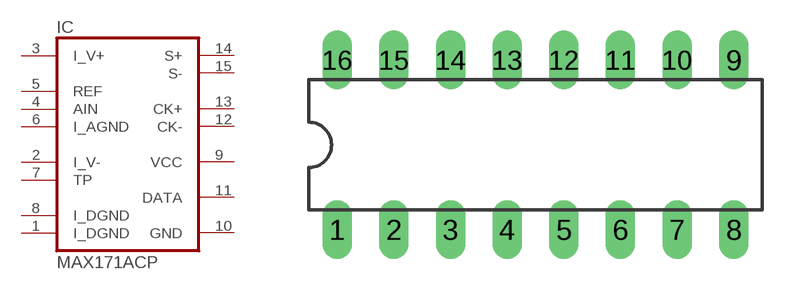
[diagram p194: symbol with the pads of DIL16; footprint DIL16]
Designator prefix IC

## MAX171ACP (OC_FARNELL: unknown; OC_NEWARK: unknown)  [DIL16]
1  I_DGND  pas
2  I_V-  in
3  I_V+  in
4  AIN  in
5  REF  sup
6  I_AGND  pas
7  TP  in
8  I_DGND  pas
9  VCC  pwr
10  GND  pwr
11  DATA  out
12  CK-  pas
13  CK+  pas
14  S+  pas
15  S-  pas

## Footprint DIL16 (pad centres in mm)
Dual In Line Package
drill 0.813 long: 1 -8.89,-3.81; 2 -6.35,-3.81; 3 -3.81,-3.81; 4 -1.27,-3.81; 5 1.27,-3.81; 6 3.81,-3.81; 7 6.35,-3.81; 8 8.89,-3.81; 9 8.89,3.81; 10 6.35,3.81; 11 3.81,3.81; 12 1.27,3.81; 13 -1.27,3.81; 14 -3.81,3.81; 15 -6.35,3.81; 16 -8.89,3.81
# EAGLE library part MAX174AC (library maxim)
ANALOG/DIGITAL CONVERTER

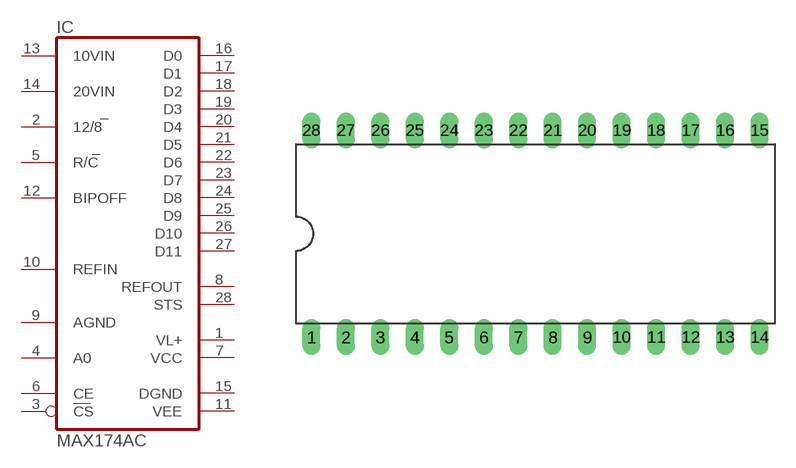
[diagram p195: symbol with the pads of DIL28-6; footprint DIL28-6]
Designator prefix IC

## MAX174AC (MPN: MAX174ACPI+; OC_FARNELL: unknown; OC_NEWARK: 89K3260)  [DIL28-6]
1  VL+  pwr
2  12/8  in
3  CS  in
4  A0  in
5  R/C  in
6  CE  in
7  VCC  pwr
8  REFOUT  sup
9  AGND  pwr
10  REFIN  in
11  VEE  pwr
12  BIPOFF  in
13  10VIN  in
14  20VIN  in
15  DGND  pwr
16  D0  hiz
17  D1  hiz
18  D2  hiz
19  D3  hiz
20  D4  hiz
21  D5  hiz
22  D6  hiz
23  D7  hiz
24  D8  hiz
25  D9  hiz
26  D10  hiz
27  D11  hiz
28  STS  out

## Footprint DIL28-6 (pad centres in mm)
Dual In Line Package 0.6 inch
drill 0.813 long: 1 -16.51,-7.62; 2 -13.97,-7.62; 3 -11.43,-7.62; 4 -8.89,-7.62; 5 -6.35,-7.62; 6 -3.81,-7.62; 7 -1.27,-7.62; 8 1.27,-7.62; 9 3.81,-7.62; 10 6.35,-7.62; 11 8.89,-7.62; 12 11.43,-7.62; 13 13.97,-7.62; 14 16.51,-7.62; 15 16.51,7.62; 16 13.97,7.62; 17 11.43,7.62; 18 8.89,7.62; 19 6.35,7.62; 20 3.81,7.62; 21 1.27,7.62; 22 -1.27,7.62; 23 -3.81,7.62; 24 -6.35,7.62; 25 -8.89,7.62; 26 -11.43,7.62; 27 -13.97,7.62; 28 -16.51,7.62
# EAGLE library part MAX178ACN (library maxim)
ANALOG/DIGITAL CONVERTER

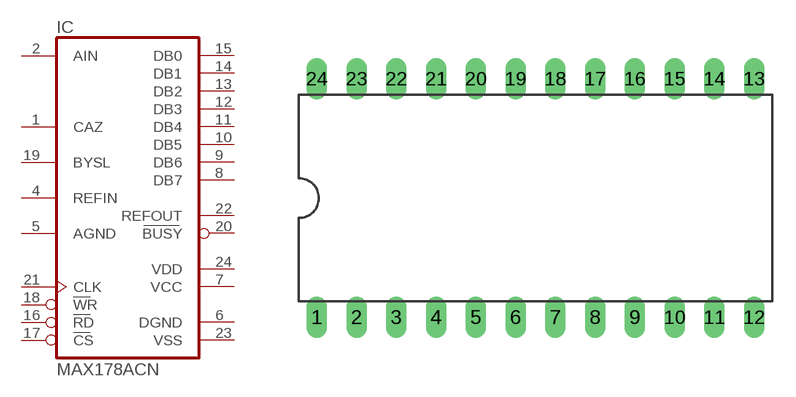
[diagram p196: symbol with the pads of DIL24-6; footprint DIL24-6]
Designator prefix IC

## MAX178ACN (MPN: MAX178ACNG+; OC_FARNELL: unknown; OC_NEWARK: 89K3281)  [DIL24-6]
1  CAZ  in
2  AIN  in
4  REFIN  in
5  AGND  pwr
6  DGND  pwr
7  VCC  pwr
8  DB7  hiz
9  DB6  hiz
10  DB5  hiz
11  DB4  hiz
12  DB3  hiz
13  DB2  hiz
14  DB1  hiz
15  DB0  hiz
16  RD  in
17  CS  in
18  WR  in
19  BYSL  in
20  BUSY  out
21  CLK  in
22  REFOUT  sup
23  VSS  pwr
24  VDD  pwr

## Footprint DIL24-6 (pad centres in mm)
Dual In Line Package 0.6 inch
drill 0.813 long: 1 -13.97,-7.62; 2 -11.43,-7.62; 3 -8.89,-7.62; 4 -6.35,-7.62; 5 -3.81,-7.62; 6 -1.27,-7.62; 7 1.27,-7.62; 8 3.81,-7.62; 9 6.35,-7.62; 10 8.89,-7.62; 11 11.43,-7.62; 12 13.97,-7.62; 13 13.97,7.62; 14 11.43,7.62; 15 8.89,7.62; 16 6.35,7.62; 17 3.81,7.62; 18 1.27,7.62; 19 -1.27,7.62; 20 -3.81,7.62; 21 -6.35,7.62; 22 -8.89,7.62; 23 -11.43,7.62; 24 -13.97,7.62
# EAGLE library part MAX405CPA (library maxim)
OP AMP

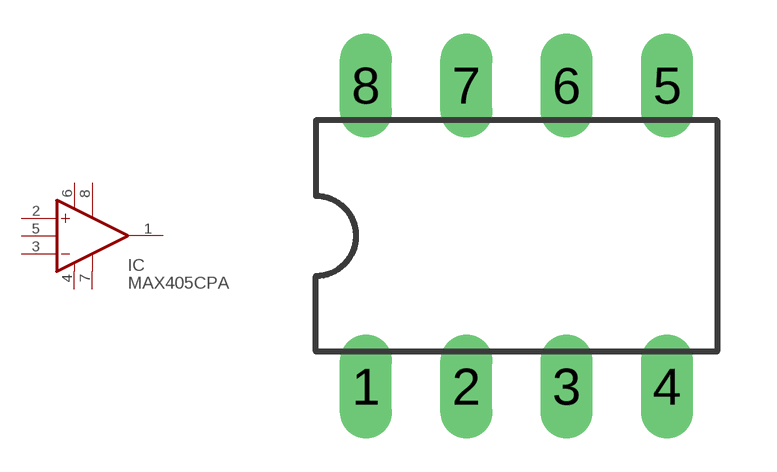
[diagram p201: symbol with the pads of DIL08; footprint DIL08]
Designator prefix IC

## MAX405CPA (OC_FARNELL: unknown; OC_NEWARK: unknown)  [DIL08]
1  OUT  out
2  +IN  in
3  -IN  in
4  V-  pwr
5  NULL  pas
6  V+  pwr
7  VC-  pas
8  VC+  pas

## Footprint DIL08 (pad centres in mm)
Dual In Line Package
drill 0.813 long: 1 -3.81,-3.81; 2 -1.27,-3.81; 3 1.27,-3.81; 4 3.81,-3.81; 5 3.81,3.81; 6 1.27,3.81; 7 -1.27,3.81; 8 -3.81,3.81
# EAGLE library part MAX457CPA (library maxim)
VIDEO AMPLIFIER

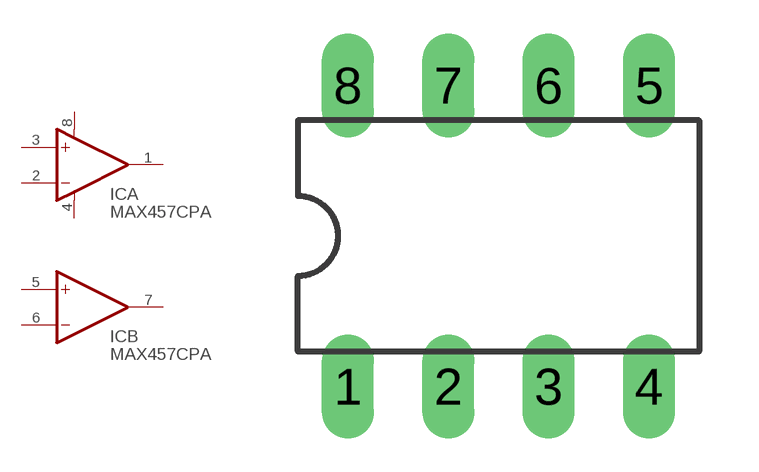
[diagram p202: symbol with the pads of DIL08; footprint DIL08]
Designator prefix IC; gates A=OPUB B=OP

## MAX457CPA (MPN: MAX457CPA+; OC_FARNELL: 1188058; OC_NEWARK: 73K8613)  [DIL08]
1  A:OUT  out
2  A:-IN  in
3  A:+IN  in
4  A:V-  pwr
5  B:+IN  in
6  B:-IN  in
7  B:OUT  out
8  A:V+  pwr

## Footprint DIL08 (pad centres in mm)
Dual In Line Package
drill 0.813 long: 1 -3.81,-3.81; 2 -1.27,-3.81; 3 1.27,-3.81; 4 3.81,-3.81; 5 3.81,3.81; 6 1.27,3.81; 7 -1.27,3.81; 8 -3.81,3.81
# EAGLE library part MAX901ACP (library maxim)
VOLTAGE COMPARATOR

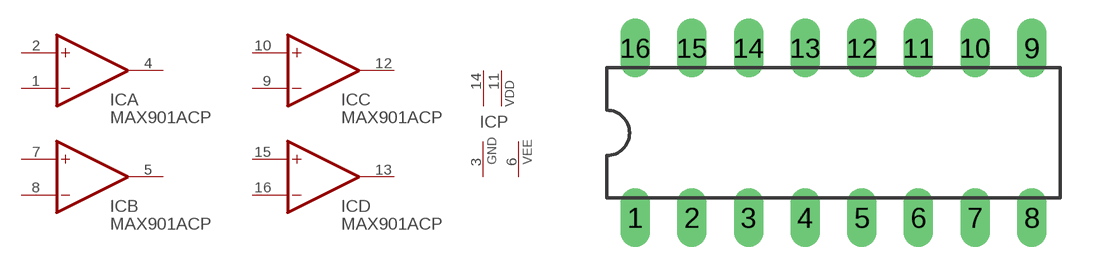
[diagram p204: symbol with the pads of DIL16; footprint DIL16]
Designator prefix IC; gates A=OP B=OP C=OP D=OP P=PWR1

## MAX901ACP (MF: MAXIM; MPN: MAX901ACPE; OC_FARNELL: unknown; OC_NEWARK: 91C2935)  [DIL16]
1  A:-IN  in
2  A:+IN  in
3  P:GND  pwr
4  A:OUT  out
5  B:OUT  out
6  P:VEE  pwr
7  B:+IN  in
8  B:-IN  in
9  C:-IN  in
10  C:+IN  in
11  P:VDD  pwr
12  C:OUT  out
13  D:OUT  out
14  P:VCC  pwr
15  D:+IN  in
16  D:-IN  in

## Footprint DIL16 (pad centres in mm)
Dual In Line Package
drill 0.813 long: 1 -8.89,-3.81; 2 -6.35,-3.81; 3 -3.81,-3.81; 4 -1.27,-3.81; 5 1.27,-3.81; 6 3.81,-3.81; 7 6.35,-3.81; 8 8.89,-3.81; 9 8.89,3.81; 10 6.35,3.81; 11 3.81,3.81; 12 1.27,3.81; 13 -1.27,3.81; 14 -3.81,3.81; 15 -6.35,3.81; 16 -8.89,3.81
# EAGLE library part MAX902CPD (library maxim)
VOLTAGE COMPARATOR

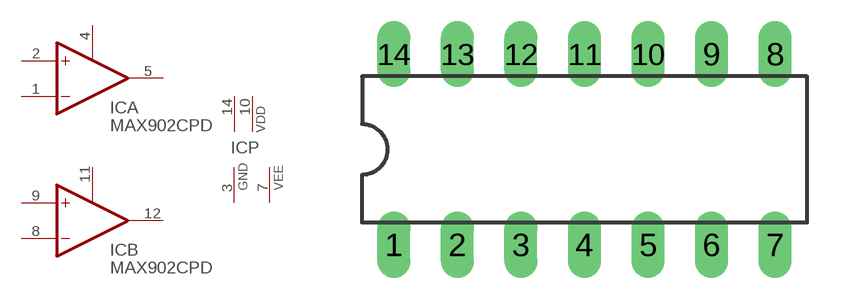
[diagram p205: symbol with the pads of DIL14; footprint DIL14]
Designator prefix IC; gates A=MAX900 B=MAX900 P=PWR1

## MAX902CPD (MF: MAXIM; MPN: MAX902CPD; OC_FARNELL: unknown; OC_NEWARK: 91C2947)  [DIL14]
1  A:-IN  in
2  A:+IN  in
3  P:GND  pwr
4  A:LATCH  pas
5  A:OUT  out
7  P:VEE  pwr
8  B:-IN  in
9  B:+IN  in
10  P:VDD  pwr
11  B:LATCH  pas
12  B:OUT  out
14  P:VCC  pwr

## Footprint DIL14 (pad centres in mm)
Dual In Line Package
drill 0.813 long: 1 -7.62,-3.81; 2 -5.08,-3.81; 3 -2.54,-3.81; 4 0,-3.81; 5 2.54,-3.81; 6 5.08,-3.81; 7 7.62,-3.81; 8 7.62,3.81; 9 5.08,3.81; 10 2.54,3.81; 11 0,3.81; 12 -2.54,3.81; 13 -5.08,3.81; 14 -7.62,3.81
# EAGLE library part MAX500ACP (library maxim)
DIGITAL/ANALOG CONVERTER

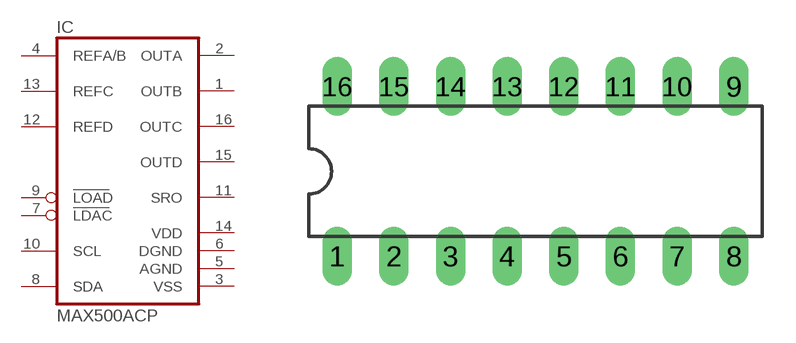
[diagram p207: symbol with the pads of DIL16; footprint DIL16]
Designator prefix IC

## MAX500ACP (MF: MAXIM; MPN: MAX500ACPE+; OC_FARNELL: 9726373; OC_NEWARK: 33K2077)  [DIL16]
1  OUTB  sup
2  OUTA  sup
3  VSS  pwr
4  REFA/B  in
5  AGND  pwr
6  DGND  pwr
7  LDAC  in
8  SDA  in
9  LOAD  in
10  SCL  in
11  SRO  out
12  REFD  in
13  REFC  in
14  VDD  pwr
15  OUTD  sup
16  OUTC  sup

## Footprint DIL16 (pad centres in mm)
Dual In Line Package
drill 0.813 long: 1 -8.89,-3.81; 2 -6.35,-3.81; 3 -3.81,-3.81; 4 -1.27,-3.81; 5 1.27,-3.81; 6 3.81,-3.81; 7 6.35,-3.81; 8 8.89,-3.81; 9 8.89,3.81; 10 6.35,3.81; 11 3.81,3.81; 12 1.27,3.81; 13 -1.27,3.81; 14 -3.81,3.81; 15 -6.35,3.81; 16 -8.89,3.81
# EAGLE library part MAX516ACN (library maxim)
COMPARATOR

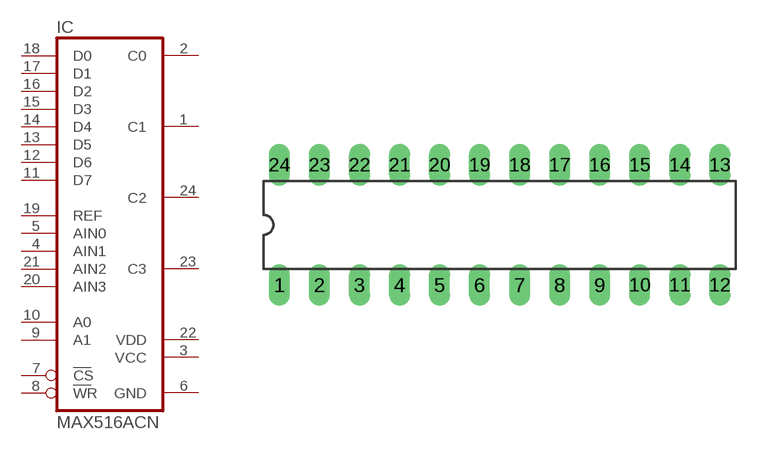
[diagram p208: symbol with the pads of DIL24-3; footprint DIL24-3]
Designator prefix IC

## MAX516ACN (MF: MAXIM; MPN: MAX516ACNG+; OC_FARNELL: unknown; OC_NEWARK: 61K0519)  [DIL24-3]
1  C1  out
2  C0  out
3  VCC  pwr
4  AIN1  in
5  AIN0  in
6  GND  pwr
7  CS  in
8  WR  in
9  A1  in
10  A0  in
11  D7  in
12  D6  in
13  D5  in
14  D4  in
15  D3  in
16  D2  in
17  D1  in
18  D0  in
19  REF  in
20  AIN3  in
21  AIN2  in
22  VDD  pwr
23  C3  out
24  C2  out

## Footprint DIL24-3 (pad centres in mm)
Dual In Line Package 0.3 inch
drill 0.813 long: 1 -13.97,-3.81; 2 -11.43,-3.81; 3 -8.89,-3.81; 4 -6.35,-3.81; 5 -3.81,-3.81; 6 -1.27,-3.81; 7 1.27,-3.81; 8 3.81,-3.81; 9 6.35,-3.81; 10 8.89,-3.81; 11 11.43,-3.81; 12 13.97,-3.81; 13 13.97,3.81; 14 11.43,3.81; 15 8.89,3.81; 16 6.35,3.81; 17 3.81,3.81; 18 1.27,3.81; 19 -1.27,3.81; 20 -3.81,3.81; 21 -6.35,3.81; 22 -8.89,3.81; 23 -11.43,3.81; 24 -13.97,3.81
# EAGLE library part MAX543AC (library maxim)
DIGITAL/ANALOG CONVERTER

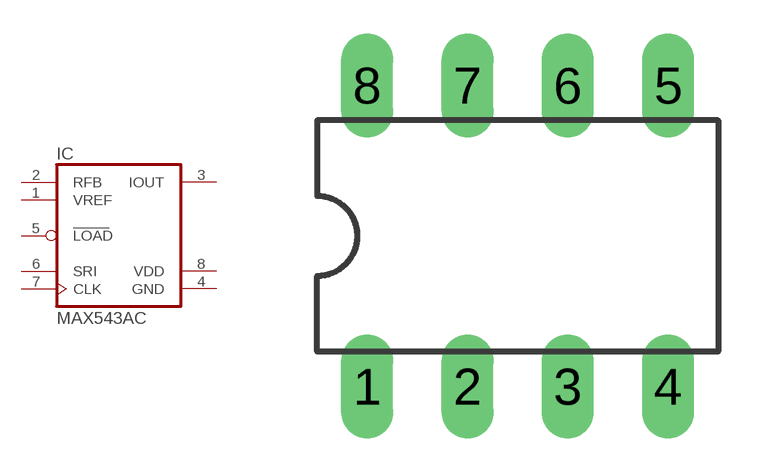
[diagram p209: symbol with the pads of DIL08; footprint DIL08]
Designator prefix IC

## MAX543ACP (MPN: MAX543ACPA+; OC_FARNELL: unknown; OC_NEWARK: 67K5720)  [DIL08]
1  VREF  in
2  RFB  in
3  IOUT  out
4  GND  pwr
5  LOAD  in
6  SRI  in
7  CLK  in
8  VDD  pwr

## Footprint DIL08 (pad centres in mm)
Dual In Line Package
drill 0.813 long: 1 -3.81,-3.81; 2 -1.27,-3.81; 3 1.27,-3.81; 4 3.81,-3.81; 5 3.81,3.81; 6 1.27,3.81; 7 -1.27,3.81; 8 -3.81,3.81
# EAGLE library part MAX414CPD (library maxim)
OP AMP

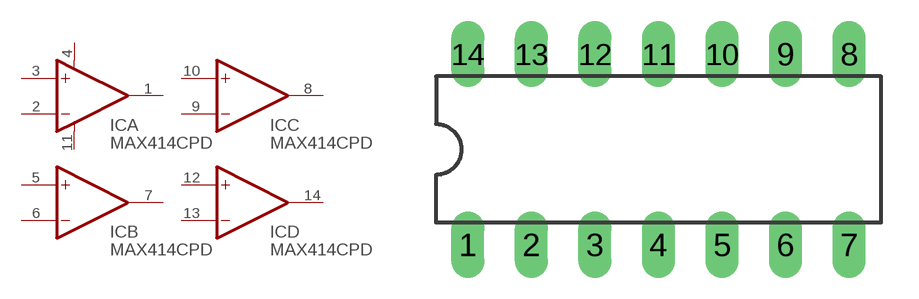
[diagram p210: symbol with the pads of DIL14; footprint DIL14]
Designator prefix IC; gates A=OPUB B=OP C=OP D=OP

## MAX414CPD (MPN: MAX414CPD+; OC_FARNELL: unknown; OC_NEWARK: 18M7422)  [DIL14]
1  A:OUT  out
2  A:-IN  in
3  A:+IN  in
4  A:V+  pwr
5  B:+IN  in
6  B:-IN  in
7  B:OUT  out
8  C:OUT  out
9  C:-IN  in
10  C:+IN  in
11  A:V-  pwr
12  D:+IN  in
13  D:-IN  in
14  D:OUT  out

## Footprint DIL14 (pad centres in mm)
Dual In Line Package
drill 0.813 long: 1 -7.62,-3.81; 2 -5.08,-3.81; 3 -2.54,-3.81; 4 0,-3.81; 5 2.54,-3.81; 6 5.08,-3.81; 7 7.62,-3.81; 8 7.62,3.81; 9 5.08,3.81; 10 2.54,3.81; 11 0,3.81; 12 -2.54,3.81; 13 -5.08,3.81; 14 -7.62,3.81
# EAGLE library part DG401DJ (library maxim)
ANALOG SWITCH

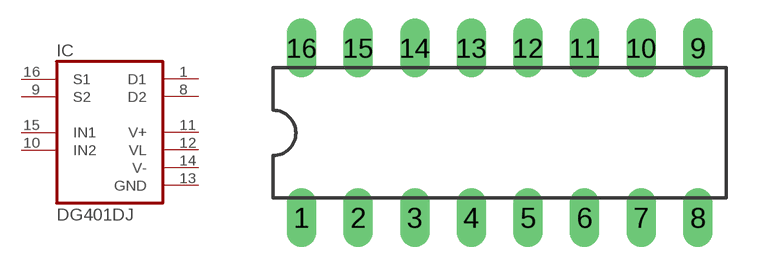
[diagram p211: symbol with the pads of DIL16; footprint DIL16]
Designator prefix IC

## DG401DJ (MPN: DG401DJ; OC_FARNELL: 1421843; OC_NEWARK: 06F3955)  [DIL16]
1  D1  pas
8  D2  pas
9  S2  pas
10  IN2  in
11  V+  pwr
12  VL  pwr
13  GND  pwr
14  V-  pwr
15  IN1  in
16  S1  pas

## Footprint DIL16 (pad centres in mm)
Dual In Line Package
drill 0.813 long: 1 -8.89,-3.81; 2 -6.35,-3.81; 3 -3.81,-3.81; 4 -1.27,-3.81; 5 1.27,-3.81; 6 3.81,-3.81; 7 6.35,-3.81; 8 8.89,-3.81; 9 8.89,3.81; 10 6.35,3.81; 11 3.81,3.81; 12 1.27,3.81; 13 -1.27,3.81; 14 -3.81,3.81; 15 -6.35,3.81; 16 -8.89,3.81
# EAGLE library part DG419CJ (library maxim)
ANALOG SWITCH

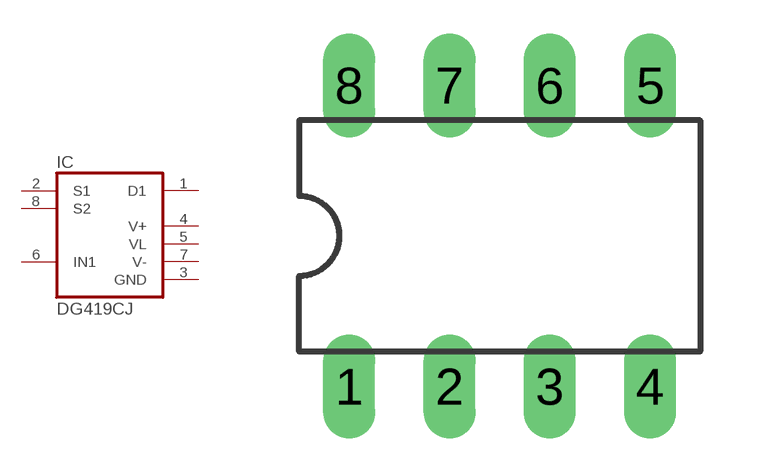
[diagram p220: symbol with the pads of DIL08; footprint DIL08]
Designator prefix IC

## DG419CJ (MF: MAXIM; MPN: DG419CJ; OC_FARNELL: unknown; OC_NEWARK: 77C6520)  [DIL08]
1  D1  pas
2  S1  pas
3  GND  pwr
4  V+  pwr
5  VL  pwr
6  IN1  in
7  V-  pwr
8  S2  pas

## Footprint DIL08 (pad centres in mm)
Dual In Line Package
drill 0.813 long: 1 -3.81,-3.81; 2 -1.27,-3.81; 3 1.27,-3.81; 4 3.81,-3.81; 5 3.81,3.81; 6 1.27,3.81; 7 -1.27,3.81; 8 -3.81,3.81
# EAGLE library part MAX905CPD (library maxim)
VOLTAGE COMPARATOR

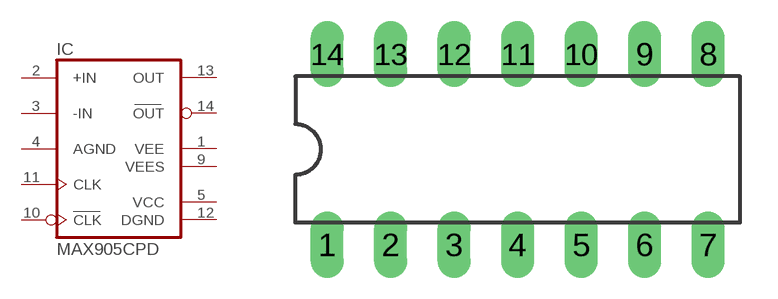
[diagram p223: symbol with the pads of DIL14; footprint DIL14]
Designator prefix IC

## MAX905CPD (OC_FARNELL: unknown; OC_NEWARK: unknown)  [DIL14]
1  VEE  pwr
2  +IN  in
3  -IN  in
4  AGND  pwr
5  VCC  pwr
9  VEES  pwr
10  CLK  in
11  CLK  in
12  DGND  pwr
13  OUT  out
14  OUT  out

## Footprint DIL14 (pad centres in mm)
Dual In Line Package
drill 0.813 long: 1 -7.62,-3.81; 2 -5.08,-3.81; 3 -2.54,-3.81; 4 0,-3.81; 5 2.54,-3.81; 6 5.08,-3.81; 7 7.62,-3.81; 8 7.62,3.81; 9 5.08,3.81; 10 2.54,3.81; 11 0,3.81; 12 -2.54,3.81; 13 -5.08,3.81; 14 -7.62,3.81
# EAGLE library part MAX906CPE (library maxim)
VOLTAGE COMPARATOR

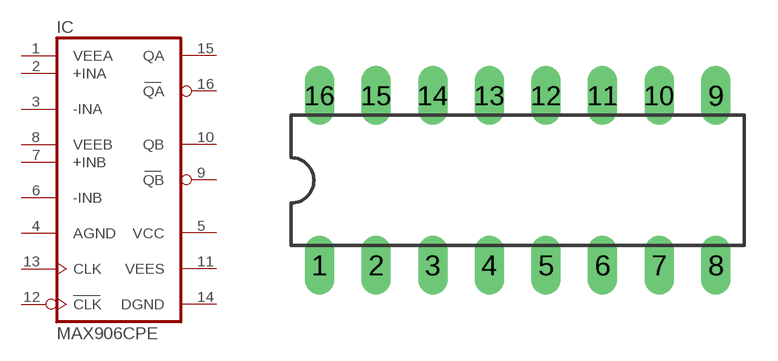
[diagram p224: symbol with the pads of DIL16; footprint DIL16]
Designator prefix IC

## MAX906CPE (OC_FARNELL: unknown; OC_NEWARK: unknown)  [DIL16]
1  VEEA  pwr
2  +INA  in
3  -INA  in
4  AGND  pwr
5  VCC  pwr
6  -INB  in
7  +INB  in
8  VEEB  pwr
9  QB  out
10  QB  out
11  VEES  pwr
12  CLK  in
13  CLK  in
14  DGND  pwr
15  QA  out
16  QA  out

## Footprint DIL16 (pad centres in mm)
Dual In Line Package
drill 0.813 long: 1 -8.89,-3.81; 2 -6.35,-3.81; 3 -3.81,-3.81; 4 -1.27,-3.81; 5 1.27,-3.81; 6 3.81,-3.81; 7 6.35,-3.81; 8 8.89,-3.81; 9 8.89,3.81; 10 6.35,3.81; 11 3.81,3.81; 12 1.27,3.81; 13 -1.27,3.81; 14 -3.81,3.81; 15 -6.35,3.81; 16 -8.89,3.81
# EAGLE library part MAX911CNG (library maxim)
VOLTAGE COMPARATOR

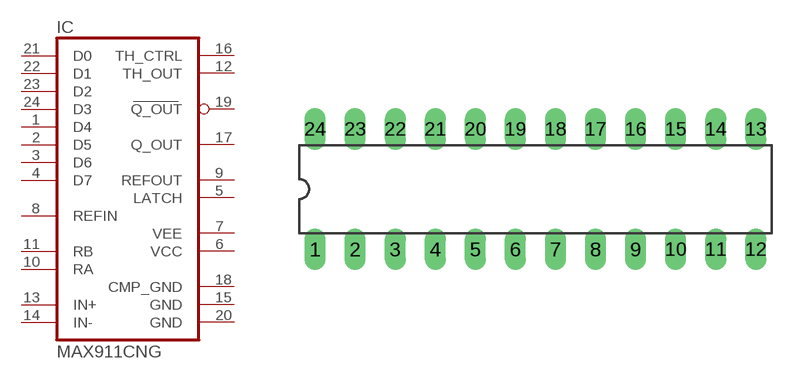
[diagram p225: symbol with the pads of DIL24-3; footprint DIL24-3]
Designator prefix IC

## MAX911CNG (OC_FARNELL: unknown; OC_NEWARK: unknown)  [DIL24-3]
1  D4  in
2  D5  in
3  D6  in
4  D7  in
5  LATCH  pas
6  VCC  pwr
7  VEE  pwr
8  REFIN  in
9  REFOUT  out
10  RA  pas
11  RB  pas
12  TH_OUT  out
13  IN+  in
14  IN-  in
15  GND  pwr
16  TH_CTRL  in
17  Q_OUT  out
18  CMP_GND  pwr
19  Q_OUT  out
20  GND  pwr
21  D0  in
22  D1  in
23  D2  in
24  D3  in

## Footprint DIL24-3 (pad centres in mm)
Dual In Line Package 0.3 inch
drill 0.813 long: 1 -13.97,-3.81; 2 -11.43,-3.81; 3 -8.89,-3.81; 4 -6.35,-3.81; 5 -3.81,-3.81; 6 -1.27,-3.81; 7 1.27,-3.81; 8 3.81,-3.81; 9 6.35,-3.81; 10 8.89,-3.81; 11 11.43,-3.81; 12 13.97,-3.81; 13 13.97,3.81; 14 11.43,3.81; 15 8.89,3.81; 16 6.35,3.81; 17 3.81,3.81; 18 1.27,3.81; 19 -1.27,3.81; 20 -3.81,3.81; 21 -6.35,3.81; 22 -8.89,3.81; 23 -11.43,3.81; 24 -13.97,3.81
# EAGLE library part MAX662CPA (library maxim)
SUPPLY CHARGE PUMP

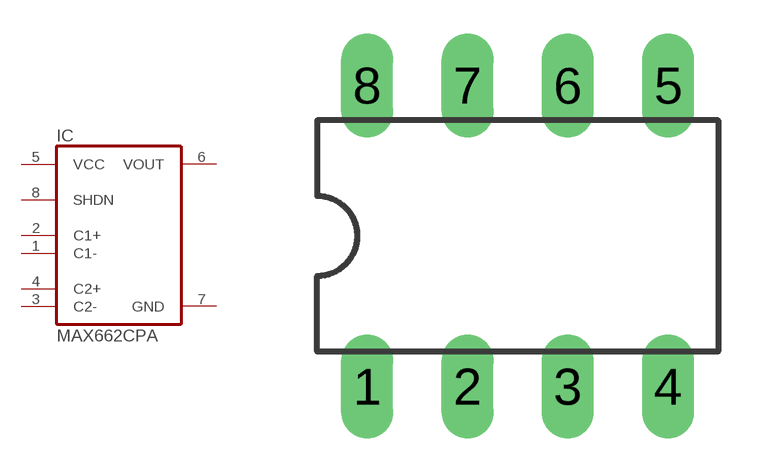
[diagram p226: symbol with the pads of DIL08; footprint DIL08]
Designator prefix IC

## MAX662CPA (OC_FARNELL: unknown; OC_NEWARK: unknown)  [DIL08]
1  C1-  pas
2  C1+  pas
3  C2-  pas
4  C2+  pas
5  VCC  pwr
6  VOUT  sup
7  GND  pwr
8  SHDN  in

## Footprint DIL08 (pad centres in mm)
Dual In Line Package
drill 0.813 long: 1 -3.81,-3.81; 2 -1.27,-3.81; 3 1.27,-3.81; 4 3.81,-3.81; 5 3.81,3.81; 6 1.27,3.81; 7 -1.27,3.81; 8 -3.81,3.81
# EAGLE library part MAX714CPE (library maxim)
WATCHDOG

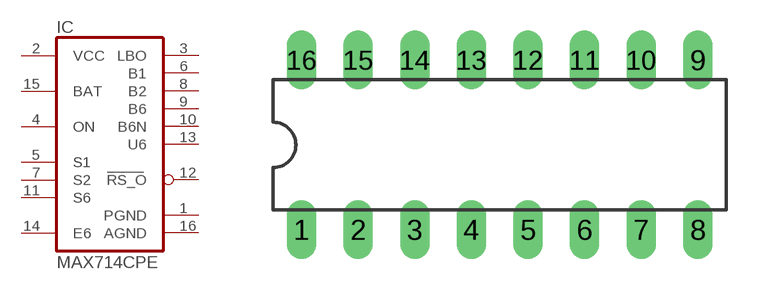
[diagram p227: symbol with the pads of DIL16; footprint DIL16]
Designator prefix IC

## MAX714CPE (OC_FARNELL: unknown; OC_NEWARK: unknown)  [DIL16]
1  PGND  pwr
2  VCC  pwr
3  LBO  out
4  ON  pas
5  S1  in
6  B1  out
7  S2  in
8  B2  out
9  B6  out
10  B6N  out
11  S6  in
12  RS_O  out
13  U6  out
14  E6  pas
15  BAT  in
16  AGND  pwr

## Footprint DIL16 (pad centres in mm)
Dual In Line Package
drill 0.813 long: 1 -8.89,-3.81; 2 -6.35,-3.81; 3 -3.81,-3.81; 4 -1.27,-3.81; 5 1.27,-3.81; 6 3.81,-3.81; 7 6.35,-3.81; 8 8.89,-3.81; 9 8.89,3.81; 10 6.35,3.81; 11 3.81,3.81; 12 1.27,3.81; 13 -1.27,3.81; 14 -3.81,3.81; 15 -6.35,3.81; 16 -8.89,3.81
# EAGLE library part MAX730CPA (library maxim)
DC/DC CONVERTER

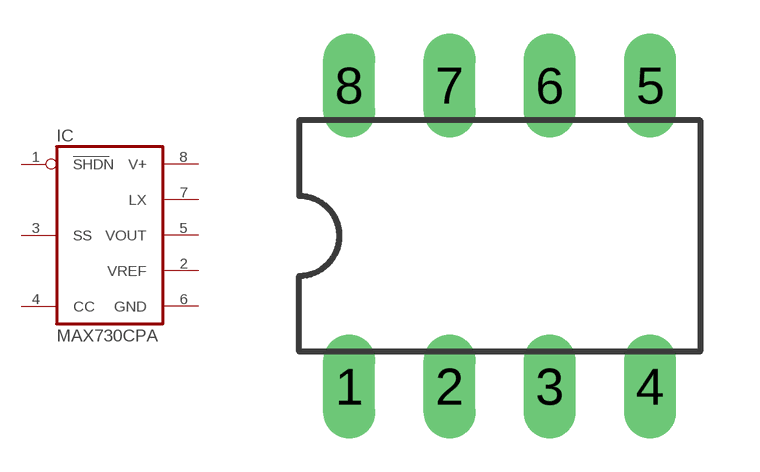
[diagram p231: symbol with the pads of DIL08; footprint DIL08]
Designator prefix IC

## MAX730CPA (OC_FARNELL: unknown; OC_NEWARK: unknown)  [DIL08]
1  SHDN  in
2  VREF  out
3  SS  in
4  CC  in
5  VOUT  out
6  GND  pwr
7  LX  out
8  V+  pwr

## Footprint DIL08 (pad centres in mm)
Dual In Line Package
drill 0.813 long: 1 -3.81,-3.81; 2 -1.27,-3.81; 3 1.27,-3.81; 4 3.81,-3.81; 5 3.81,3.81; 6 1.27,3.81; 7 -1.27,3.81; 8 -3.81,3.81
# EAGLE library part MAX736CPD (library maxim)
DC/DC CONVERTER

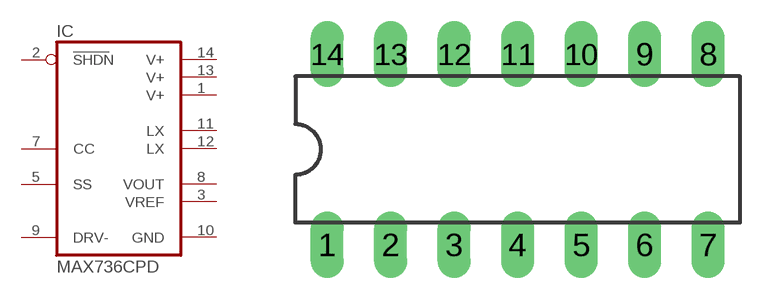
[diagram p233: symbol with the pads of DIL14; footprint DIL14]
Designator prefix IC

## MAX736CPD (MPN: MAX736CPD+; OC_FARNELL: unknown; OC_NEWARK: 13M2409)  [DIL14]
1  V+  pwr
2  SHDN  in
3  VREF  out
5  SS  in
7  CC  in
8  VOUT  out
9  DRV-  in
10  GND  pwr
11  LX  out
12  LX  out
13  V+  pwr
14  V+  pwr

## Footprint DIL14 (pad centres in mm)
Dual In Line Package
drill 0.813 long: 1 -7.62,-3.81; 2 -5.08,-3.81; 3 -2.54,-3.81; 4 0,-3.81; 5 2.54,-3.81; 6 5.08,-3.81; 7 7.62,-3.81; 8 7.62,3.81; 9 5.08,3.81; 10 2.54,3.81; 11 0,3.81; 12 -2.54,3.81; 13 -5.08,3.81; 14 -7.62,3.81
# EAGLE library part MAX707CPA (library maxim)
WATCHDOG

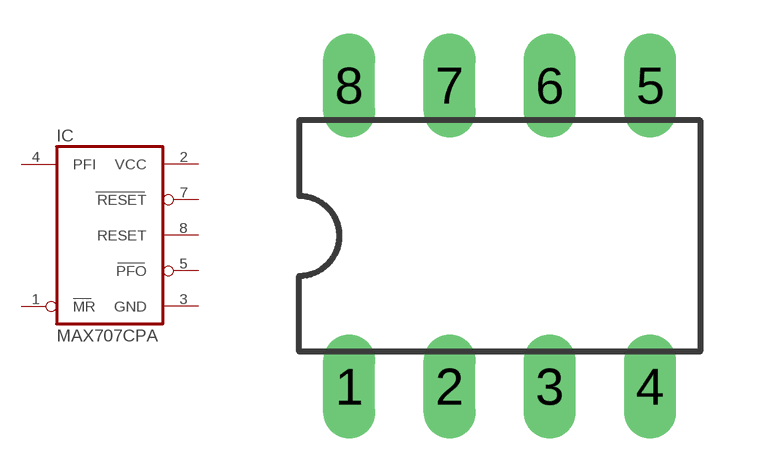
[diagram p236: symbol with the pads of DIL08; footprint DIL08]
Designator prefix IC

## MAX707CPA (MPN: MAX707CPA; OC_FARNELL: 1188005; OC_NEWARK: 34C4006)  [DIL08]
1  MR  in
2  VCC  pwr
3  GND  pwr
4  PFI  in
5  PFO  out
7  RESET  out
8  RESET  out

## Footprint DIL08 (pad centres in mm)
Dual In Line Package
drill 0.813 long: 1 -3.81,-3.81; 2 -1.27,-3.81; 3 1.27,-3.81; 4 3.81,-3.81; 5 3.81,3.81; 6 1.27,3.81; 7 -1.27,3.81; 8 -3.81,3.81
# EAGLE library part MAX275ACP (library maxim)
ANALOG FILTER

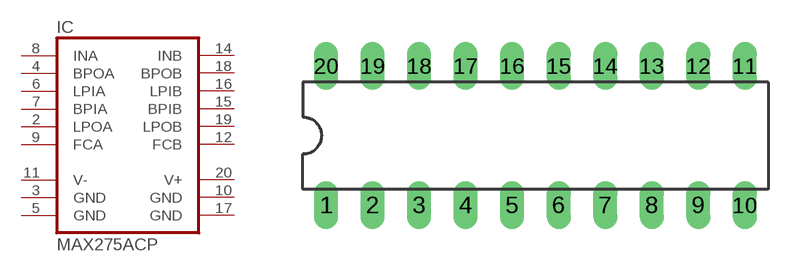
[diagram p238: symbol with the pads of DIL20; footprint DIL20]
Designator prefix IC

## MAX275ACP (MPN: MAX275ACPP+; OC_FARNELL: unknown; OC_NEWARK: 99K3137)  [DIL20]
2  LPOA  out
3  GND  pwr
4  BPOA  out
5  GND  pwr
6  LPIA  in
7  BPIA  in
8  INA  in
9  FCA  pas
10  GND  pwr
11  V-  pwr
12  FCB  pas
14  INB  in
15  BPIB  in
16  LPIB  in
17  GND  pwr
18  BPOB  out
19  LPOB  out
20  V+  pwr

## Footprint DIL20 (pad centres in mm)
Dual In Line Package
drill 0.813 long: 1 -11.43,-3.81; 2 -8.89,-3.81; 3 -6.35,-3.81; 4 -3.81,-3.81; 5 -1.27,-3.81; 6 1.27,-3.81; 7 3.81,-3.81; 8 6.35,-3.81; 9 8.89,-3.81; 10 11.43,-3.81; 11 11.43,3.81; 12 8.89,3.81; 13 6.35,3.81; 14 3.81,3.81; 15 1.27,3.81; 16 -1.27,3.81; 17 -3.81,3.81; 18 -6.35,3.81; 19 -8.89,3.81; 20 -11.43,3.81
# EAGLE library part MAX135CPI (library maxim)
ANALOG/DIGITAL CONVERTER

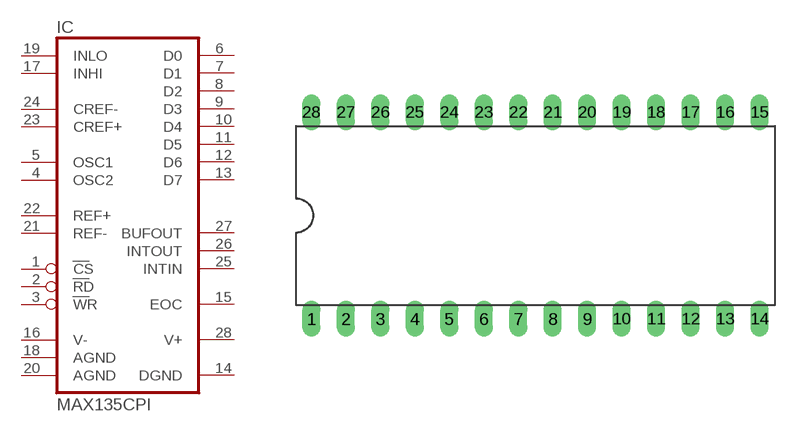
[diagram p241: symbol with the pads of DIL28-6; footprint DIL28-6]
Designator prefix IC

## MAX135CPI (MPN: MAX135CPI+; OC_FARNELL: unknown; OC_NEWARK: 99K2909)  [DIL28-6]
1  CS  in
2  RD  in
3  WR  in
4  OSC2  pas
5  OSC1  pas
6  D0  out
7  D1  out
8  D2  out
9  D3  out
10  D4  out
11  D5  out
12  D6  out
13  D7  out
14  DGND  pwr
15  EOC  out
16  V-  pwr
17  INHI  in
18  AGND  pwr
19  INLO  in
20  AGND  pwr
21  REF-  in
22  REF+  in
23  CREF+  pas
24  CREF-  pas
25  INTIN  in
26  INTOUT  out
27  BUFOUT  out
28  V+  pwr

## Footprint DIL28-6 (pad centres in mm)
Dual In Line Package 0.6 inch
drill 0.813 long: 1 -16.51,-7.62; 2 -13.97,-7.62; 3 -11.43,-7.62; 4 -8.89,-7.62; 5 -6.35,-7.62; 6 -3.81,-7.62; 7 -1.27,-7.62; 8 1.27,-7.62; 9 3.81,-7.62; 10 6.35,-7.62; 11 8.89,-7.62; 12 11.43,-7.62; 13 13.97,-7.62; 14 16.51,-7.62; 15 16.51,7.62; 16 13.97,7.62; 17 11.43,7.62; 18 8.89,7.62; 19 6.35,7.62; 20 3.81,7.62; 21 1.27,7.62; 22 -1.27,7.62; 23 -3.81,7.62; 24 -6.35,7.62; 25 -8.89,7.62; 26 -11.43,7.62; 27 -13.97,7.62; 28 -16.51,7.62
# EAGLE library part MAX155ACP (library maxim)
ANALOG/DIGITAL CONVERTER

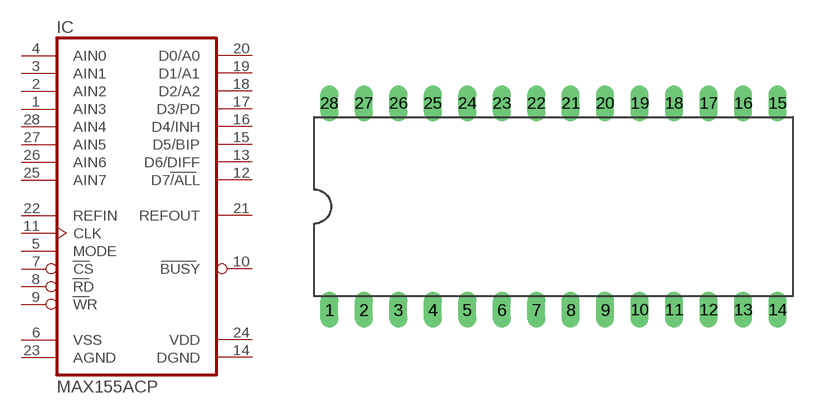
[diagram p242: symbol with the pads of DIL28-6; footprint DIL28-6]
Designator prefix IC

## MAX155ACP (MPN: MAX155ACPI+; OC_FARNELL: unknown; OC_NEWARK: 58M8459)  [DIL28-6]
1  AIN3  in
2  AIN2  in
3  AIN1  in
4  AIN0  in
5  MODE  in
6  VSS  pwr
7  CS  in
8  RD  in
9  WR  in
10  BUSY  out
11  CLK  in
12  D7/ALL  out
13  D6/DIFF  out
14  DGND  pwr
15  D5/BIP  out
16  D4/INH  out
17  D3/PD  out
18  D2/A2  out
19  D1/A1  out
20  D0/A0  out
21  REFOUT  out
22  REFIN  in
23  AGND  pwr
24  VDD  pwr
25  AIN7  in
26  AIN6  in
27  AIN5  in
28  AIN4  in

## Footprint DIL28-6 (pad centres in mm)
Dual In Line Package 0.6 inch
drill 0.813 long: 1 -16.51,-7.62; 2 -13.97,-7.62; 3 -11.43,-7.62; 4 -8.89,-7.62; 5 -6.35,-7.62; 6 -3.81,-7.62; 7 -1.27,-7.62; 8 1.27,-7.62; 9 3.81,-7.62; 10 6.35,-7.62; 11 8.89,-7.62; 12 11.43,-7.62; 13 13.97,-7.62; 14 16.51,-7.62; 15 16.51,7.62; 16 13.97,7.62; 17 11.43,7.62; 18 8.89,7.62; 19 6.35,7.62; 20 3.81,7.62; 21 1.27,7.62; 22 -1.27,7.62; 23 -3.81,7.62; 24 -6.35,7.62; 25 -8.89,7.62; 26 -11.43,7.62; 27 -13.97,7.62; 28 -16.51,7.62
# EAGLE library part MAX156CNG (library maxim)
ANALOG/DIGITAL CONVERTER

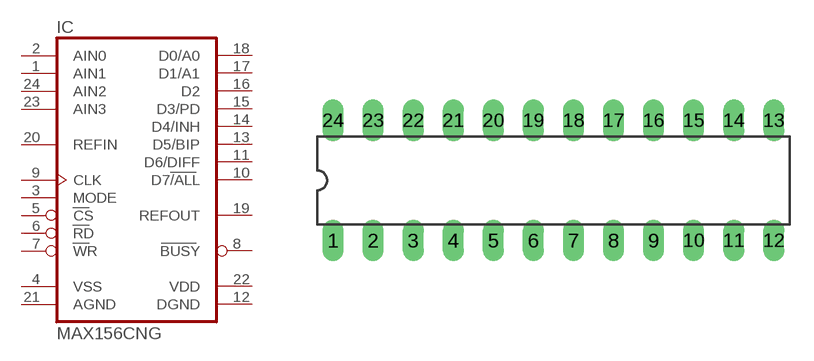
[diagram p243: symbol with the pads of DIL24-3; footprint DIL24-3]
Designator prefix IC

## MAX156CNG (OC_FARNELL: unknown; OC_NEWARK: unknown)  [DIL24-3]
1  AIN1  in
2  AIN0  in
3  MODE  in
4  VSS  pwr
5  CS  in
6  RD  in
7  WR  in
8  BUSY  out
9  CLK  in
10  D7/ALL  out
11  D6/DIFF  out
12  DGND  pwr
13  D5/BIP  out
14  D4/INH  out
15  D3/PD  out
16  D2  out
17  D1/A1  out
18  D0/A0  out
19  REFOUT  out
20  REFIN  in
21  AGND  pwr
22  VDD  pwr
23  AIN3  in
24  AIN2  in

## Footprint DIL24-3 (pad centres in mm)
Dual In Line Package 0.3 inch
drill 0.813 long: 1 -13.97,-3.81; 2 -11.43,-3.81; 3 -8.89,-3.81; 4 -6.35,-3.81; 5 -3.81,-3.81; 6 -1.27,-3.81; 7 1.27,-3.81; 8 3.81,-3.81; 9 6.35,-3.81; 10 8.89,-3.81; 11 11.43,-3.81; 12 13.97,-3.81; 13 13.97,3.81; 14 11.43,3.81; 15 8.89,3.81; 16 6.35,3.81; 17 3.81,3.81; 18 1.27,3.81; 19 -1.27,3.81; 20 -3.81,3.81; 21 -6.35,3.81; 22 -8.89,3.81; 23 -11.43,3.81; 24 -13.97,3.81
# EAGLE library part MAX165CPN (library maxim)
ANALOG/DIGITAL CONVERTER

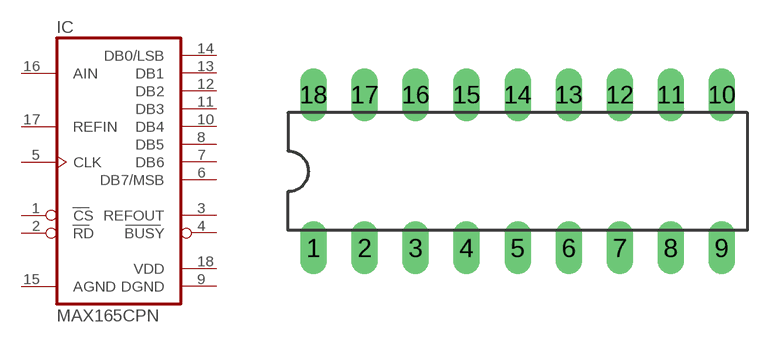
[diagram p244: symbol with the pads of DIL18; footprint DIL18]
Designator prefix IC

## MAX165CPN (OC_FARNELL: unknown; OC_NEWARK: unknown)  [DIL18]
1  CS  in
2  RD  in
3  REFOUT  out
4  BUSY  out
5  CLK  in
6  DB7/MSB  hiz
7  DB6  hiz
8  DB5  hiz
9  DGND  pwr
10  DB4  hiz
11  DB3  hiz
12  DB2  hiz
13  DB1  hiz
14  DB0/LSB  hiz
15  AGND  pwr
16  AIN  in
17  REFIN  in
18  VDD  pwr

## Footprint DIL18 (pad centres in mm)
Dual In Line Package
drill 0.813 long: 1 -10.16,-3.81; 2 -7.62,-3.81; 3 -5.08,-3.81; 4 -2.54,-3.81; 5 0,-3.81; 6 2.54,-3.81; 7 5.08,-3.81; 8 7.62,-3.81; 9 10.16,-3.81; 10 10.16,3.81; 11 7.62,3.81; 12 5.08,3.81; 13 2.54,3.81; 14 0,3.81; 15 -2.54,3.81; 16 -5.08,3.81; 17 -7.62,3.81; 18 -10.16,3.81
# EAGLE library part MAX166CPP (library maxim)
ANALOG/DIGITAL CONVERTER

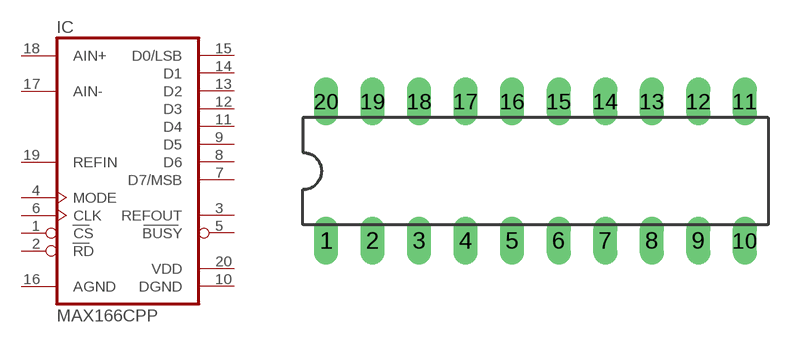
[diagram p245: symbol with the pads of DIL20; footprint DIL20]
Designator prefix IC

## MAX166CPP (OC_FARNELL: unknown; OC_NEWARK: unknown)  [DIL20]
1  CS  in
2  RD  in
3  REFOUT  out
4  MODE  in
5  BUSY  out
6  CLK  in
7  D7/MSB  hiz
8  D6  hiz
9  D5  hiz
10  DGND  pwr
11  D4  hiz
12  D3  hiz
13  D2  hiz
14  D1  hiz
15  D0/LSB  hiz
16  AGND  pwr
17  AIN-  in
18  AIN+  in
19  REFIN  in
20  VDD  pwr

## Footprint DIL20 (pad centres in mm)
Dual In Line Package
drill 0.813 long: 1 -11.43,-3.81; 2 -8.89,-3.81; 3 -6.35,-3.81; 4 -3.81,-3.81; 5 -1.27,-3.81; 6 1.27,-3.81; 7 3.81,-3.81; 8 6.35,-3.81; 9 8.89,-3.81; 10 11.43,-3.81; 11 11.43,3.81; 12 8.89,3.81; 13 6.35,3.81; 14 3.81,3.81; 15 1.27,3.81; 16 -1.27,3.81; 17 -3.81,3.81; 18 -6.35,3.81; 19 -8.89,3.81; 20 -11.43,3.81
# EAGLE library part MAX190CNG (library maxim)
ANALOG/DIGITAL CONVERTER

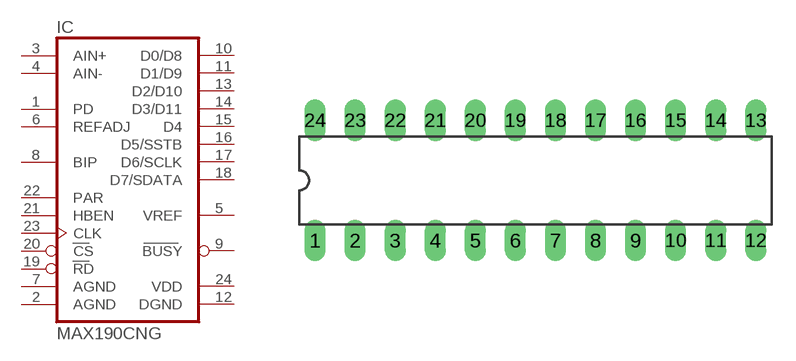
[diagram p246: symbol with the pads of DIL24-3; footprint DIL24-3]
Designator prefix IC

## MAX190CNG (OC_FARNELL: unknown; OC_NEWARK: unknown)  [DIL24-3]
1  PD  in
2  AGND  pwr
3  AIN+  in
4  AIN-  in
5  VREF  out
6  REFADJ  in
7  AGND  pwr
8  BIP  in
9  BUSY  out
10  D0/D8  hiz
11  D1/D9  hiz
12  DGND  pwr
13  D2/D10  hiz
14  D3/D11  hiz
15  D4  hiz
16  D5/SSTB  hiz
17  D6/SCLK  hiz
18  D7/SDATA  hiz
19  RD  in
20  CS  in
21  HBEN  in
22  PAR  in
23  CLK  in
24  VDD  pwr

## Footprint DIL24-3 (pad centres in mm)
Dual In Line Package 0.3 inch
drill 0.813 long: 1 -13.97,-3.81; 2 -11.43,-3.81; 3 -8.89,-3.81; 4 -6.35,-3.81; 5 -3.81,-3.81; 6 -1.27,-3.81; 7 1.27,-3.81; 8 3.81,-3.81; 9 6.35,-3.81; 10 8.89,-3.81; 11 11.43,-3.81; 12 13.97,-3.81; 13 13.97,3.81; 14 11.43,3.81; 15 8.89,3.81; 16 6.35,3.81; 17 3.81,3.81; 18 1.27,3.81; 19 -1.27,3.81; 20 -3.81,3.81; 21 -6.35,3.81; 22 -8.89,3.81; 23 -11.43,3.81; 24 -13.97,3.81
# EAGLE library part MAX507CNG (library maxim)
DIGITAL/ANALOG CONVERTER

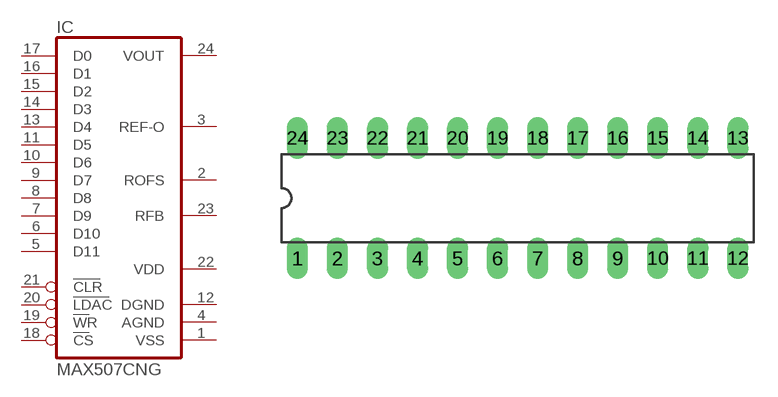
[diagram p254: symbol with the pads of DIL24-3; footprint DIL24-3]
Designator prefix IC

## MAX507CNG (OC_FARNELL: unknown; OC_NEWARK: unknown)  [DIL24-3]
1  VSS  pwr
2  ROFS  pas
3  REF-O  out
4  AGND  pwr
5  D11  in
6  D10  in
7  D9  in
8  D8  in
9  D7  in
10  D6  in
11  D5  in
12  DGND  pwr
13  D4  in
14  D3  in
15  D2  in
16  D1  in
17  D0  in
18  CS  in
19  WR  in
20  LDAC  in
21  CLR  in
22  VDD  pwr
23  RFB  pas
24  VOUT  out

## Footprint DIL24-3 (pad centres in mm)
Dual In Line Package 0.3 inch
drill 0.813 long: 1 -13.97,-3.81; 2 -11.43,-3.81; 3 -8.89,-3.81; 4 -6.35,-3.81; 5 -3.81,-3.81; 6 -1.27,-3.81; 7 1.27,-3.81; 8 3.81,-3.81; 9 6.35,-3.81; 10 8.89,-3.81; 11 11.43,-3.81; 12 13.97,-3.81; 13 13.97,3.81; 14 11.43,3.81; 15 8.89,3.81; 16 6.35,3.81; 17 3.81,3.81; 18 1.27,3.81; 19 -1.27,3.81; 20 -3.81,3.81; 21 -6.35,3.81; 22 -8.89,3.81; 23 -11.43,3.81; 24 -13.97,3.81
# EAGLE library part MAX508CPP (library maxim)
DIGITAL/ANALOG CONVERTER

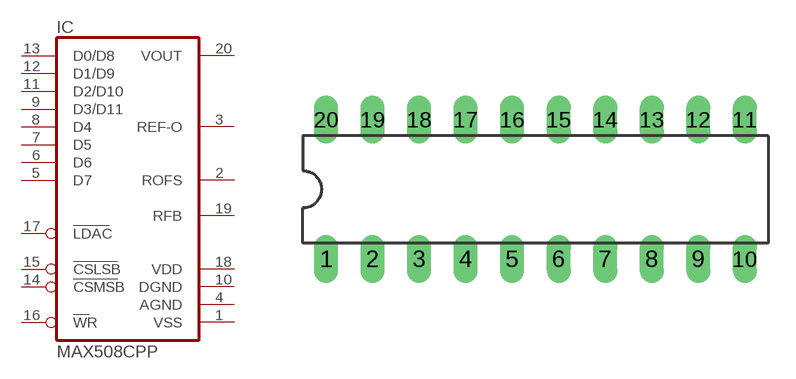
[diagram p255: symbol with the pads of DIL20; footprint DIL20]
Designator prefix IC

## MAX508CPP (OC_FARNELL: unknown; OC_NEWARK: unknown)  [DIL20]
1  VSS  pwr
2  ROFS  pas
3  REF-O  out
4  AGND  pwr
5  D7  in
6  D6  in
7  D5  in
8  D4  in
9  D3/D11  in
10  DGND  pwr
11  D2/D10  in
12  D1/D9  in
13  D0/D8  in
14  CSMSB  in
15  CSLSB  in
16  WR  in
17  LDAC  in
18  VDD  pwr
19  RFB  pas
20  VOUT  out

## Footprint DIL20 (pad centres in mm)
Dual In Line Package
drill 0.813 long: 1 -11.43,-3.81; 2 -8.89,-3.81; 3 -6.35,-3.81; 4 -3.81,-3.81; 5 -1.27,-3.81; 6 1.27,-3.81; 7 3.81,-3.81; 8 6.35,-3.81; 9 8.89,-3.81; 10 11.43,-3.81; 11 11.43,3.81; 12 8.89,3.81; 13 6.35,3.81; 14 3.81,3.81; 15 1.27,3.81; 16 -1.27,3.81; 17 -3.81,3.81; 18 -6.35,3.81; 19 -8.89,3.81; 20 -11.43,3.81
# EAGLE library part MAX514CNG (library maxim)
DIGITAL/ANALOG CONVERTER

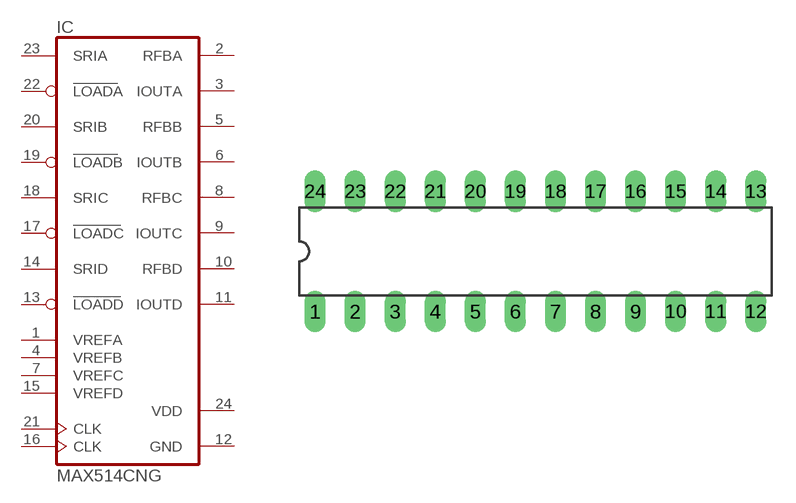
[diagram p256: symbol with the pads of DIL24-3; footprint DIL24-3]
Designator prefix IC

## MAX514CNG (OC_FARNELL: unknown; OC_NEWARK: unknown)  [DIL24-3]
1  VREFA  in
2  RFBA  pas
3  IOUTA  out
4  VREFB  in
5  RFBB  pas
6  IOUTB  out
7  VREFC  in
8  RFBC  pas
9  IOUTC  out
10  RFBD  pas
11  IOUTD  out
12  GND  pwr
13  LOADD  in
14  SRID  in
15  VREFD  in
16  CLK  pas
17  LOADC  in
18  SRIC  in
19  LOADB  in
20  SRIB  in
21  CLK  in
22  LOADA  in
23  SRIA  in
24  VDD  pwr

## Footprint DIL24-3 (pad centres in mm)
Dual In Line Package 0.3 inch
drill 0.813 long: 1 -13.97,-3.81; 2 -11.43,-3.81; 3 -8.89,-3.81; 4 -6.35,-3.81; 5 -3.81,-3.81; 6 -1.27,-3.81; 7 1.27,-3.81; 8 3.81,-3.81; 9 6.35,-3.81; 10 8.89,-3.81; 11 11.43,-3.81; 12 13.97,-3.81; 13 13.97,3.81; 14 11.43,3.81; 15 8.89,3.81; 16 6.35,3.81; 17 3.81,3.81; 18 1.27,3.81; 19 -1.27,3.81; 20 -3.81,3.81; 21 -6.35,3.81; 22 -8.89,3.81; 23 -11.43,3.81; 24 -13.97,3.81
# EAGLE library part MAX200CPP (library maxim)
RS232 TRANSMITTER

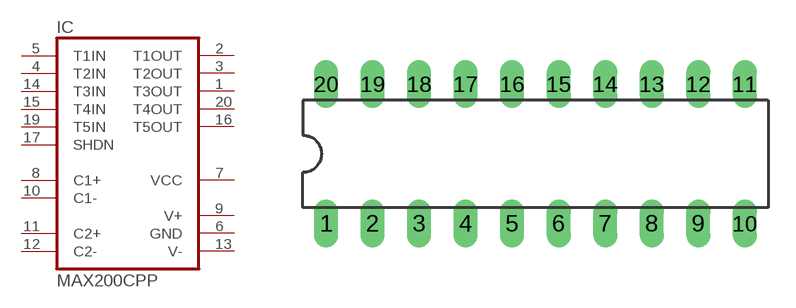
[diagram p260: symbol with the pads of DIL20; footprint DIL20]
Designator prefix IC

## MAX200CPP (OC_FARNELL: unknown; OC_NEWARK: unknown)  [DIL20]
1  T3OUT  out
2  T1OUT  out
3  T2OUT  out
4  T2IN  in
5  T1IN  in
6  GND  pwr
7  VCC  pwr
8  C1+  pas
9  V+  sup
10  C1-  pas
11  C2+  pas
12  C2-  pas
13  V-  sup
14  T3IN  in
15  T4IN  in
16  T5OUT  out
17  SHDN  in
19  T5IN  in
20  T4OUT  out

## Footprint DIL20 (pad centres in mm)
Dual In Line Package
drill 0.813 long: 1 -11.43,-3.81; 2 -8.89,-3.81; 3 -6.35,-3.81; 4 -3.81,-3.81; 5 -1.27,-3.81; 6 1.27,-3.81; 7 3.81,-3.81; 8 6.35,-3.81; 9 8.89,-3.81; 10 11.43,-3.81; 11 11.43,3.81; 12 8.89,3.81; 13 6.35,3.81; 14 3.81,3.81; 15 1.27,3.81; 16 -1.27,3.81; 17 -3.81,3.81; 18 -6.35,3.81; 19 -8.89,3.81; 20 -11.43,3.81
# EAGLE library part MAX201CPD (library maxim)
RS232 TRANSCEIVER

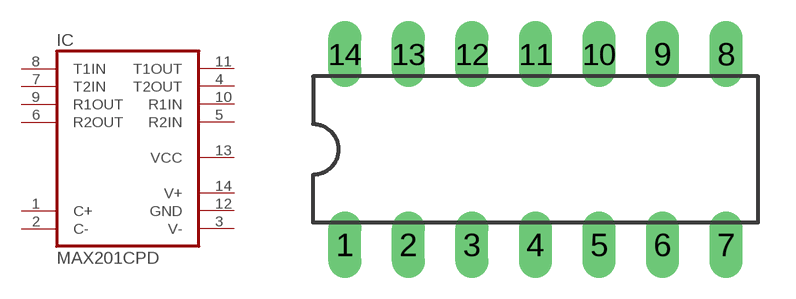
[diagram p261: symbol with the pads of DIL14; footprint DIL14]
Designator prefix IC

## MAX201CPD (MPN: MAX201CPD+; OC_FARNELL: unknown; OC_NEWARK: 89K3430)  [DIL14]
1  C+  pas
2  C-  pas
3  V-  sup
4  T2OUT  out
5  R2IN  in
6  R2OUT  out
7  T2IN  in
8  T1IN  in
9  R1OUT  out
10  R1IN  in
11  T1OUT  out
12  GND  pwr
13  VCC  pwr
14  V+  sup

## Footprint DIL14 (pad centres in mm)
Dual In Line Package
drill 0.813 long: 1 -7.62,-3.81; 2 -5.08,-3.81; 3 -2.54,-3.81; 4 0,-3.81; 5 2.54,-3.81; 6 5.08,-3.81; 7 7.62,-3.81; 8 7.62,3.81; 9 5.08,3.81; 10 2.54,3.81; 11 0,3.81; 12 -2.54,3.81; 13 -5.08,3.81; 14 -7.62,3.81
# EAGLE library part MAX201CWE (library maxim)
RS232 TRANSCEIVER

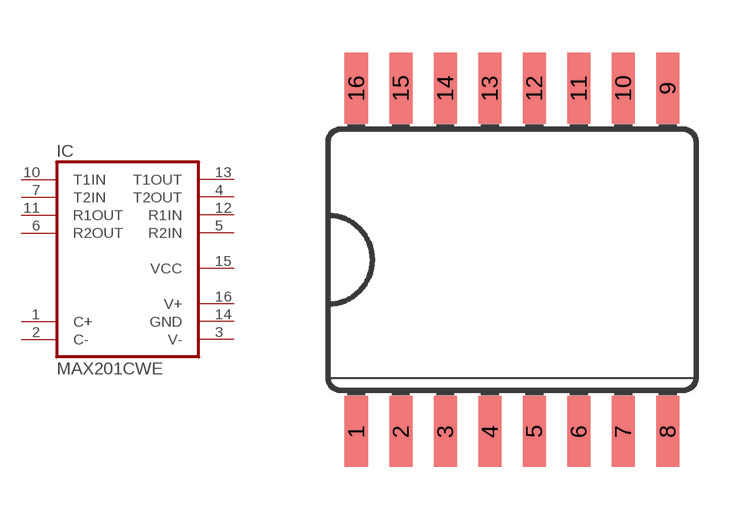
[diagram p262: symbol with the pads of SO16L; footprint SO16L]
Designator prefix IC

## MAX201CWE (MF: MAXIM; MPN: MAX201CWE+; OC_FARNELL: 1836338; OC_NEWARK: 23K5792)  [SO16L]
1  C+  pas
2  C-  pas
3  V-  sup
4  T2OUT  out
5  R2IN  in
6  R2OUT  out
7  T2IN  in
10  T1IN  in
11  R1OUT  out
12  R1IN  in
13  T1OUT  out
14  GND  pwr
15  VCC  pwr
16  V+  sup

## Footprint SO16L (pad centres in mm)
Small Outline Package .300 SIOC Source: http://www.maxim-ic.com/cgi-bin/packages?pkg=16%2FSOIC%2E300&Type=Max
smd 0.66 x 2.032: 1 -4.445,-4.902; 2 -3.175,-4.902; 3 -1.905,-4.902; 4 -0.635,-4.902; 5 0.635,-4.902; 6 1.905,-4.902; 7 3.175,-4.902; 8 4.445,-4.902; 9 4.445,4.902; 10 3.175,4.902; 11 1.905,4.902; 12 0.635,4.902; 13 -0.635,4.902; 14 -1.905,4.902; 15 -3.175,4.902; 16 -4.445,4.902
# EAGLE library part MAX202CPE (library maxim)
RS232 TRANSCEIVER

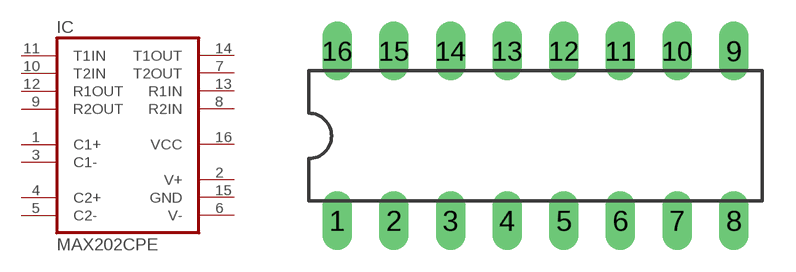
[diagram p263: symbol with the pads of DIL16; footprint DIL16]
Designator prefix IC

## MAX202CPE (MF: MAXIM; MPN: MAX202CPE+; OC_FARNELL: 9723803; OC_NEWARK: 68K4531)  [DIL16]
1  C1+  pas
2  V+  sup
3  C1-  pas
4  C2+  pas
5  C2-  pas
6  V-  sup
7  T2OUT  out
8  R2IN  in
9  R2OUT  out
10  T2IN  in
11  T1IN  in
12  R1OUT  out
13  R1IN  in
14  T1OUT  out
15  GND  pwr
16  VCC  pwr

## Footprint DIL16 (pad centres in mm)
Dual In Line Package
drill 0.813 long: 1 -8.89,-3.81; 2 -6.35,-3.81; 3 -3.81,-3.81; 4 -1.27,-3.81; 5 1.27,-3.81; 6 3.81,-3.81; 7 6.35,-3.81; 8 8.89,-3.81; 9 8.89,3.81; 10 6.35,3.81; 11 3.81,3.81; 12 1.27,3.81; 13 -1.27,3.81; 14 -3.81,3.81; 15 -6.35,3.81; 16 -8.89,3.81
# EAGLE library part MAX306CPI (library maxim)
MULTIPLEXER

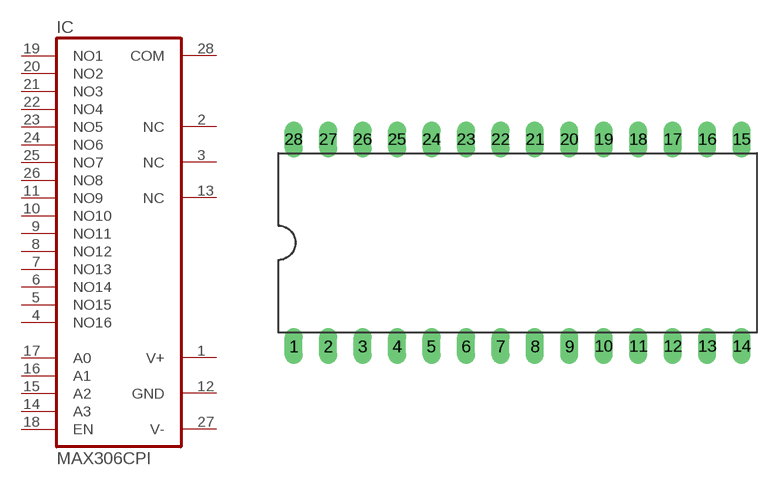
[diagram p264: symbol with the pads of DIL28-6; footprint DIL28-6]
Designator prefix IC

## MAX306CPI (MPN: MAX306CPI; OC_FARNELL: unknown; OC_NEWARK: 90C2554)  [DIL28-6]
1  V+  pwr
2  NC  nc
3  NC  nc
4  NO16  pas
5  NO15  pas
6  NO14  pas
7  NO13  pas
8  NO12  pas
9  NO11  pas
10  NO10  pas
11  NO9  pas
12  GND  pwr
13  NC  nc
14  A3  in
15  A2  in
16  A1  in
17  A0  in
18  EN  in
19  NO1  pas
20  NO2  pas
21  NO3  pas
22  NO4  pas
23  NO5  pas
24  NO6  pas
25  NO7  pas
26  NO8  pas
27  V-  pwr
28  COM  pas

## Footprint DIL28-6 (pad centres in mm)
Dual In Line Package 0.6 inch
drill 0.813 long: 1 -16.51,-7.62; 2 -13.97,-7.62; 3 -11.43,-7.62; 4 -8.89,-7.62; 5 -6.35,-7.62; 6 -3.81,-7.62; 7 -1.27,-7.62; 8 1.27,-7.62; 9 3.81,-7.62; 10 6.35,-7.62; 11 8.89,-7.62; 12 11.43,-7.62; 13 13.97,-7.62; 14 16.51,-7.62; 15 16.51,7.62; 16 13.97,7.62; 17 11.43,7.62; 18 8.89,7.62; 19 6.35,7.62; 20 3.81,7.62; 21 1.27,7.62; 22 -1.27,7.62; 23 -3.81,7.62; 24 -6.35,7.62; 25 -8.89,7.62; 26 -11.43,7.62; 27 -13.97,7.62; 28 -16.51,7.62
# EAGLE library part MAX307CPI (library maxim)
MULTIPLEXER

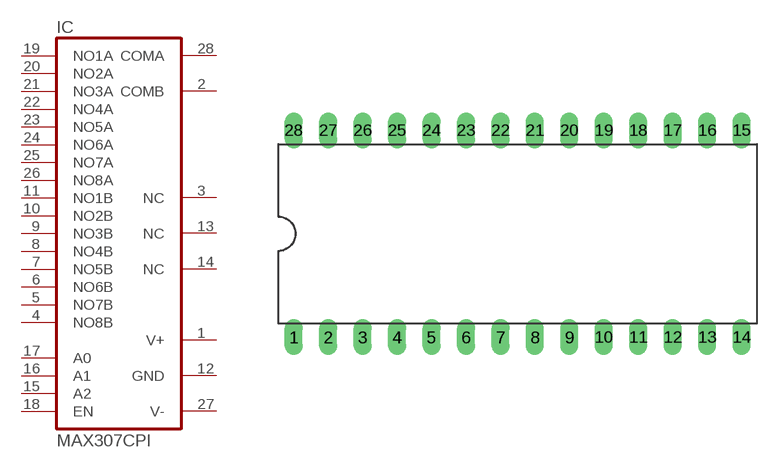
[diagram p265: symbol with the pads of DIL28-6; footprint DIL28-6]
Designator prefix IC

## MAX307CPI (MPN: MAX307CPI+; OC_FARNELL: unknown; OC_NEWARK: 68K4580)  [DIL28-6]
1  V+  pwr
2  COMB  pas
3  NC  nc
4  NO8B  pas
5  NO7B  pas
6  NO6B  pas
7  NO5B  pas
8  NO4B  pas
9  NO3B  pas
10  NO2B  pas
11  NO1B  pas
12  GND  pwr
13  NC  nc
14  NC  nc
15  A2  in
16  A1  in
17  A0  in
18  EN  in
19  NO1A  pas
20  NO2A  pas
21  NO3A  pas
22  NO4A  pas
23  NO5A  pas
24  NO6A  pas
25  NO7A  pas
26  NO8A  pas
27  V-  pwr
28  COMA  pas

## Footprint DIL28-6 (pad centres in mm)
Dual In Line Package 0.6 inch
drill 0.813 long: 1 -16.51,-7.62; 2 -13.97,-7.62; 3 -11.43,-7.62; 4 -8.89,-7.62; 5 -6.35,-7.62; 6 -3.81,-7.62; 7 -1.27,-7.62; 8 1.27,-7.62; 9 3.81,-7.62; 10 6.35,-7.62; 11 8.89,-7.62; 12 11.43,-7.62; 13 13.97,-7.62; 14 16.51,-7.62; 15 16.51,7.62; 16 13.97,7.62; 17 11.43,7.62; 18 8.89,7.62; 19 6.35,7.62; 20 3.81,7.62; 21 1.27,7.62; 22 -1.27,7.62; 23 -3.81,7.62; 24 -6.35,7.62; 25 -8.89,7.62; 26 -11.43,7.62; 27 -13.97,7.62; 28 -16.51,7.62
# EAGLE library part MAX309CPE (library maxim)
MULTIPLEXER

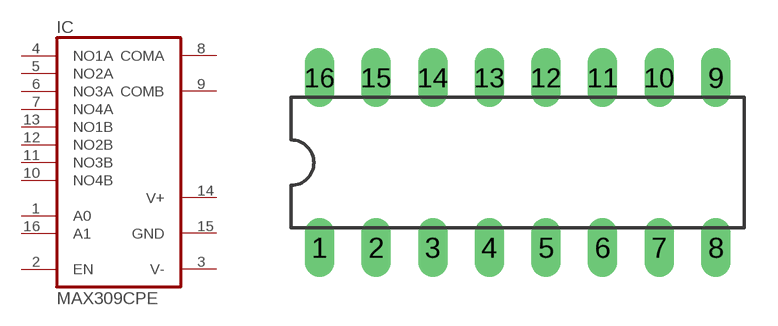
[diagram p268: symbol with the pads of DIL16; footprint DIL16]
Designator prefix IC

## MAX309CPE (MPN: MAX309CPE+; OC_FARNELL: unknown; OC_NEWARK: 76K6682)  [DIL16]
1  A0  in
2  EN  in
3  V-  pwr
4  NO1A  pas
5  NO2A  pas
6  NO3A  pas
7  NO4A  pas
8  COMA  pas
9  COMB  pas
10  NO4B  pas
11  NO3B  pas
12  NO2B  pas
13  NO1B  pas
14  V+  pwr
15  GND  pwr
16  A1  in

## Footprint DIL16 (pad centres in mm)
Dual In Line Package
drill 0.813 long: 1 -8.89,-3.81; 2 -6.35,-3.81; 3 -3.81,-3.81; 4 -1.27,-3.81; 5 1.27,-3.81; 6 3.81,-3.81; 7 6.35,-3.81; 8 8.89,-3.81; 9 8.89,3.81; 10 6.35,3.81; 11 3.81,3.81; 12 1.27,3.81; 13 -1.27,3.81; 14 -3.81,3.81; 15 -6.35,3.81; 16 -8.89,3.81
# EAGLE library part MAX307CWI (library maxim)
MULTIPLEXER

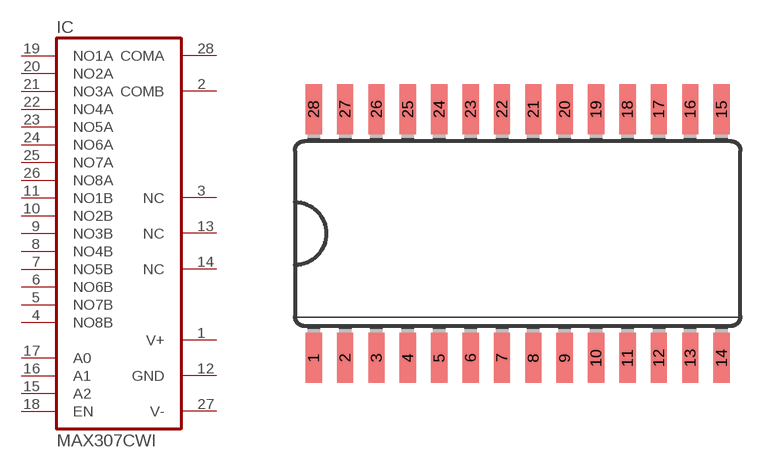
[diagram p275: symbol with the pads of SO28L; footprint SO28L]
Designator prefix IC

## MAX307CWI (MF: MAXIM; MPN: MAX307CWI; OC_FARNELL: 1379788; OC_NEWARK: 77C8953)  [SO28L]
1  V+  pwr
2  COMB  pas
3  NC  nc
4  NO8B  pas
5  NO7B  pas
6  NO6B  pas
7  NO5B  pas
8  NO4B  pas
9  NO3B  pas
10  NO2B  pas
11  NO1B  pas
12  GND  pwr
13  NC  nc
14  NC  nc
15  A2  in
16  A1  in
17  A0  in
18  EN  in
19  NO1A  pas
20  NO2A  pas
21  NO3A  pas
22  NO4A  pas
23  NO5A  pas
24  NO6A  pas
25  NO7A  pas
26  NO8A  pas
27  V-  pwr
28  COMA  pas

## Footprint SO28L (pad centres in mm)
Small Outline Package MAX3221-MAX3243.pdf; SO28W
smd 0.66 x 2.032: 1 -8.255,-5.029; 2 -6.985,-5.029; 3 -5.715,-5.029; 4 -4.445,-5.029; 5 -3.175,-5.029; 6 -1.905,-5.029; 7 -0.635,-5.029; 8 0.635,-5.029; 9 1.905,-5.029; 10 3.175,-5.029; 11 4.445,-5.029; 12 5.715,-5.029; 13 6.985,-5.029; 14 8.255,-5.029; 15 8.255,5.029; 16 6.985,5.029; 17 5.715,5.029; 18 4.445,5.029; 19 3.175,5.029; 20 1.905,5.029; 21 0.635,5.029; 22 -0.635,5.029; 23 -1.905,5.029; 24 -3.175,5.029; 25 -4.445,5.029; 26 -5.715,5.029; 27 -6.985,5.029; 28 -8.255,5.029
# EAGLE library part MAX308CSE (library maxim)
MULTIPLEXER

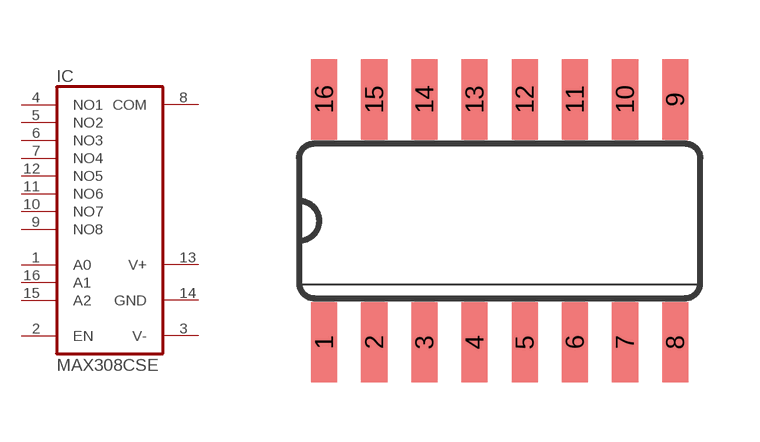
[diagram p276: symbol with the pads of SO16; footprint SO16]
Designator prefix IC

## MAX308CSE (MF: MAXIM; MPN: MAX308CSE+; OC_FARNELL: 9724699; OC_NEWARK: 67K4640)  [SO16]
1  A0  in
2  EN  in
3  V-  pwr
4  NO1  pas
5  NO2  pas
6  NO3  pas
7  NO4  pas
8  COM  pas
9  NO8  pas
10  NO7  pas
11  NO6  pas
12  NO5  pas
13  V+  pwr
14  GND  pwr
15  A2  in
16  A1  in

## Footprint SO16 (pad centres in mm)
Small Outline Package .150 SIOC Source: http://www.maxim-ic.com/package_drawings/21-0041B.pdf
smd 0.66 x 2.032: 1 -4.445,-3.073; 2 -3.175,-3.073; 3 -1.905,-3.073; 4 -0.635,-3.073; 5 0.635,-3.073; 6 1.905,-3.073; 7 3.175,-3.073; 8 4.445,-3.073; 9 4.445,3.073; 10 3.175,3.073; 11 1.905,3.073; 12 0.635,3.073; 13 -0.635,3.073; 14 -1.905,3.073; 15 -3.175,3.073; 16 -4.445,3.073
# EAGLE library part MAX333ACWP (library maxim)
ANALOG SWITCH

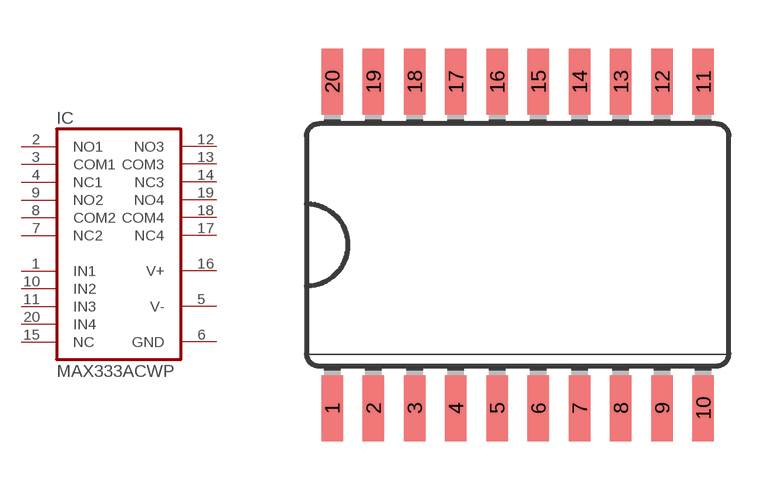
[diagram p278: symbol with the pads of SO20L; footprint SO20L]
Designator prefix IC

## MAX333ACWP (MF: MAXIM; MPN: MAX333ACWP+; OC_FARNELL: 9725547; OC_NEWARK: 28K3302)  [SO20L]
1  IN1  in
2  NO1  pas
3  COM1  pas
4  NC1  pas
5  V-  pwr
6  GND  pwr
7  NC2  pas
8  COM2  pas
9  NO2  pas
10  IN2  in
11  IN3  in
12  NO3  pas
13  COM3  pas
14  NC3  pas
15  NC  nc
16  V+  pwr
17  NC4  pas
18  COM4  pas
19  NO4  pas
20  IN4  in

## Footprint SO20L (pad centres in mm)
Small Outline Package
smd 0.66 x 2.032: 1 -5.715,-5.029; 2 -4.445,-5.029; 3 -3.175,-5.029; 4 -1.905,-5.029; 5 -0.635,-5.029; 6 0.635,-5.029; 7 1.905,-5.029; 8 3.175,-5.029; 9 4.445,-5.029; 10 5.715,-5.029; 11 5.715,5.029; 12 4.445,5.029; 13 3.175,5.029; 14 1.905,5.029; 15 0.635,5.029; 16 -0.635,5.029; 17 -1.905,5.029; 18 -3.175,5.029; 19 -4.445,5.029; 20 -5.715,5.029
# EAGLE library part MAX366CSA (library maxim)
Signal-line CIRCUIT PROTECTOR

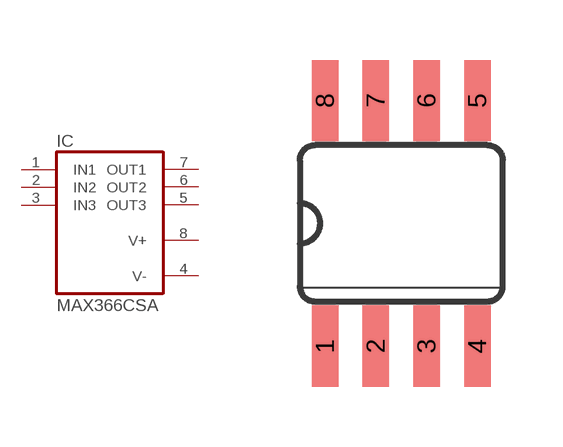
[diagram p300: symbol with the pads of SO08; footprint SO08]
Designator prefix IC

## MAX366CSA (MPN: MAX366CSA+; OC_FARNELL: unknown; OC_NEWARK: 68K4674)  [SO08]
1  IN1  pas
2  IN2  pas
3  IN3  pas
4  V-  pwr
5  OUT3  pas
6  OUT2  pas
7  OUT1  pas
8  V+  pwr

## Footprint SO08 (pad centres in mm)
Small Outline Package SOIC 150 mil
smd 0.66 x 2.032: 1 -1.905,-3.073; 2 -0.635,-3.073; 3 0.635,-3.073; 4 1.905,-3.073; 5 1.905,3.073; 6 0.635,3.073; 7 -0.635,3.073; 8 -1.905,3.073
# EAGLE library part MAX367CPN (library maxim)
Signal-line CIRCUIT PROTECTOR

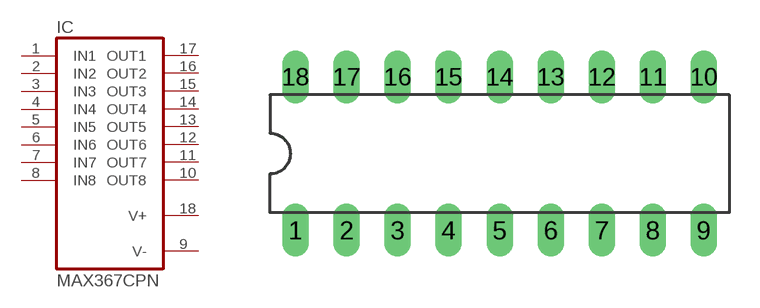
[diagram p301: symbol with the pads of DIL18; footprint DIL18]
Designator prefix IC

## MAX367CPN (MPN: MAX367CPN+; OC_FARNELL: unknown; OC_NEWARK: 89K3625)  [DIL18]
1  IN1  pas
2  IN2  pas
3  IN3  pas
4  IN4  pas
5  IN5  pas
6  IN6  pas
7  IN7  pas
8  IN8  pas
9  V-  pwr
10  OUT8  pas
11  OUT7  pas
12  OUT6  pas
13  OUT5  pas
14  OUT4  pas
15  OUT3  pas
16  OUT2  pas
17  OUT1  pas
18  V+  pwr

## Footprint DIL18 (pad centres in mm)
Dual In Line Package
drill 0.813 long: 1 -10.16,-3.81; 2 -7.62,-3.81; 3 -5.08,-3.81; 4 -2.54,-3.81; 5 0,-3.81; 6 2.54,-3.81; 7 5.08,-3.81; 8 7.62,-3.81; 9 10.16,-3.81; 10 10.16,3.81; 11 7.62,3.81; 12 5.08,3.81; 13 2.54,3.81; 14 0,3.81; 15 -2.54,3.81; 16 -5.08,3.81; 17 -7.62,3.81; 18 -10.16,3.81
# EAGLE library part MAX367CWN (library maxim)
Signal-line CIRCUIT PROTECTORr

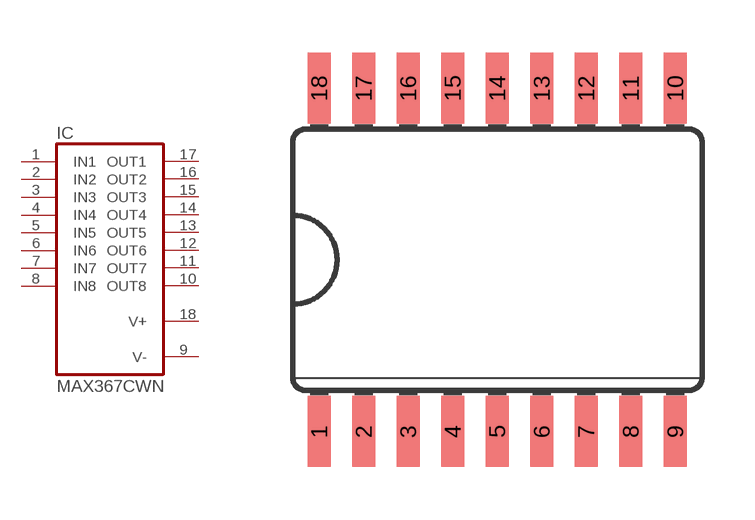
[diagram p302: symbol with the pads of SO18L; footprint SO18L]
Designator prefix IC

## MAX367CWN (MPN: MAX367CWN+; OC_FARNELL: unknown; OC_NEWARK: 89K3626)  [SO18L]
1  IN1  pas
2  IN2  pas
3  IN3  pas
4  IN4  pas
5  IN5  pas
6  IN6  pas
7  IN7  pas
8  IN8  pas
9  V-  pwr
10  OUT8  pas
11  OUT7  pas
12  OUT6  pas
13  OUT5  pas
14  OUT4  pas
15  OUT3  pas
16  OUT2  pas
17  OUT1  pas
18  V+  pwr

## Footprint SO18L (pad centres in mm)
Small Outline Package
smd 0.66 x 2.032: 1 -5.08,-4.902; 2 -3.81,-4.902; 3 -2.54,-4.902; 4 -1.27,-4.902; 5 0,-4.902; 6 1.27,-4.902; 7 2.54,-4.902; 8 3.81,-4.902; 9 5.08,-4.902; 10 5.08,4.902; 11 3.81,4.902; 12 2.54,4.902; 13 1.27,4.902; 14 0,4.902; 15 -1.27,4.902; 16 -2.54,4.902; 17 -3.81,4.902; 18 -5.08,4.902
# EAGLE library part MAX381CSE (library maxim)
ANALOG SWITCH

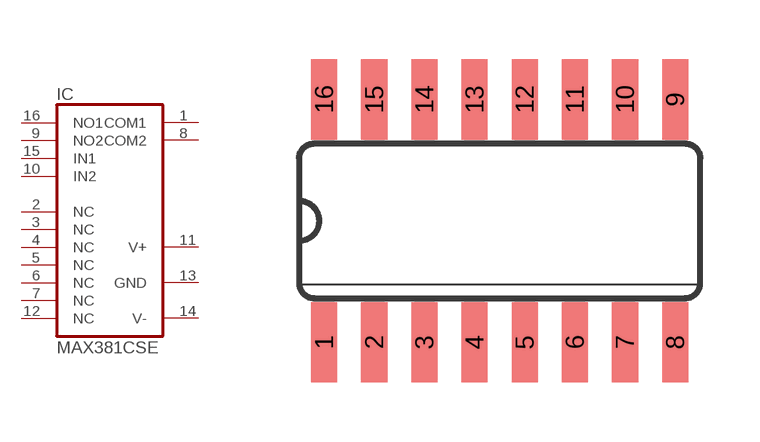
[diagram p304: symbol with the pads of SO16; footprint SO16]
Designator prefix IC

## MAX381CSE (MPN: MAX381CSE+; OC_FARNELL: unknown; OC_NEWARK: 02P7737)  [SO16]
1  COM1  pas
2  NC  nc
3  NC  nc
4  NC  nc
5  NC  nc
6  NC  nc
7  NC  nc
8  COM2  pas
9  NO2  pas
10  IN2  in
11  V+  pwr
12  NC  nc
13  GND  pwr
14  V-  pwr
15  IN1  in
16  NO1  pas

## Footprint SO16 (pad centres in mm)
Small Outline Package .150 SIOC Source: http://www.maxim-ic.com/package_drawings/21-0041B.pdf
smd 0.66 x 2.032: 1 -4.445,-3.073; 2 -3.175,-3.073; 3 -1.905,-3.073; 4 -0.635,-3.073; 5 0.635,-3.073; 6 1.905,-3.073; 7 3.175,-3.073; 8 4.445,-3.073; 9 4.445,3.073; 10 3.175,3.073; 11 1.905,3.073; 12 0.635,3.073; 13 -0.635,3.073; 14 -1.905,3.073; 15 -3.175,3.073; 16 -4.445,3.073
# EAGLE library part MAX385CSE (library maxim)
ANALOG SWITCH

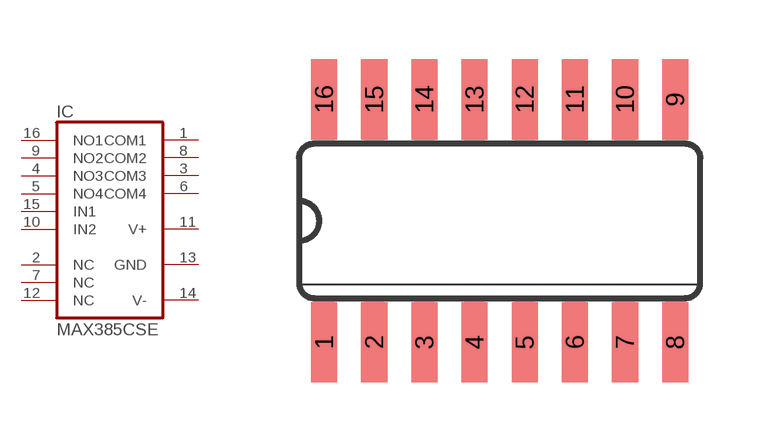
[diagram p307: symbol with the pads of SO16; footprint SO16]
Designator prefix IC

## MAX385CSE (MPN: MAX385CSE+; OC_FARNELL: unknown; OC_NEWARK: 76K6741)  [SO16]
1  COM1  pas
2  NC  nc
3  COM3  pas
4  NO3  pas
5  NO4  pas
6  COM4  pas
7  NC  nc
8  COM2  pas
9  NO2  pas
10  IN2  in
11  V+  pwr
12  NC  nc
13  GND  pwr
14  V-  pwr
15  IN1  in
16  NO1  pas

## Footprint SO16 (pad centres in mm)
Small Outline Package .150 SIOC Source: http://www.maxim-ic.com/package_drawings/21-0041B.pdf
smd 0.66 x 2.032: 1 -4.445,-3.073; 2 -3.175,-3.073; 3 -1.905,-3.073; 4 -0.635,-3.073; 5 0.635,-3.073; 6 1.905,-3.073; 7 3.175,-3.073; 8 4.445,-3.073; 9 4.445,3.073; 10 3.175,3.073; 11 1.905,3.073; 12 0.635,3.073; 13 -0.635,3.073; 14 -1.905,3.073; 15 -3.175,3.073; 16 -4.445,3.073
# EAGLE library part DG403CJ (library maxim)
ANALOG SWITCH

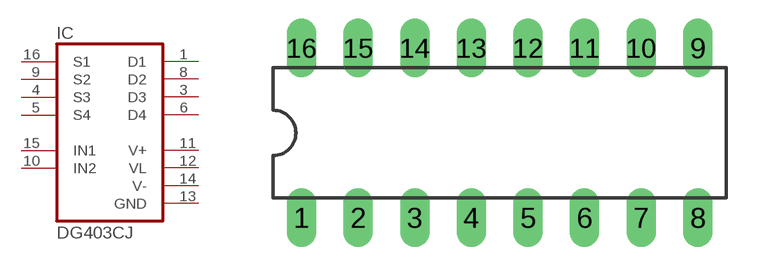
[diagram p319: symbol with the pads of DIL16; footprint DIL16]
Designator prefix IC

## DG403CJ (MPN: DG403CJ+; OC_FARNELL: unknown; OC_NEWARK: 89K2353)  [DIL16]
1  D1  pas
3  D3  pas
4  S3  pas
5  S4  pas
6  D4  pas
8  D2  pas
9  S2  pas
10  IN2  in
11  V+  pwr
12  VL  pwr
13  GND  pwr
14  V-  pwr
15  IN1  in
16  S1  pas

## Footprint DIL16 (pad centres in mm)
Dual In Line Package
drill 0.813 long: 1 -8.89,-3.81; 2 -6.35,-3.81; 3 -3.81,-3.81; 4 -1.27,-3.81; 5 1.27,-3.81; 6 3.81,-3.81; 7 6.35,-3.81; 8 8.89,-3.81; 9 8.89,3.81; 10 6.35,3.81; 11 3.81,3.81; 12 1.27,3.81; 13 -1.27,3.81; 14 -3.81,3.81; 15 -6.35,3.81; 16 -8.89,3.81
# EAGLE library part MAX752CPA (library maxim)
DC-DC CONVERTER

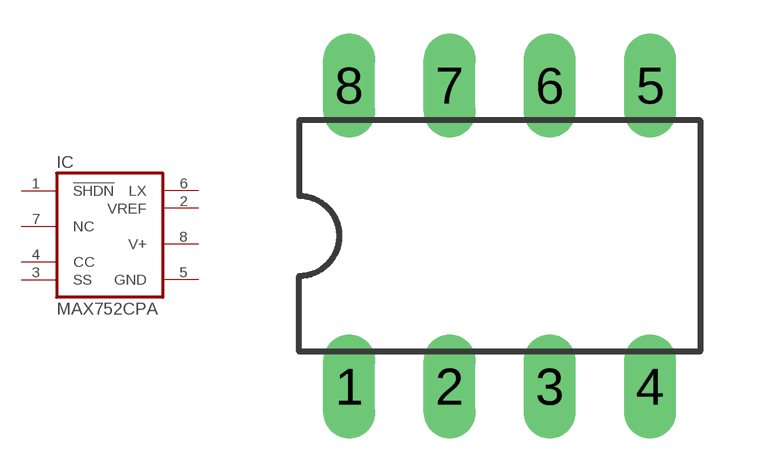
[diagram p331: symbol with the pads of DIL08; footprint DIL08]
Designator prefix IC

## MAX752CPA (MF: MAXIM; MPN: MAX752CPA; OC_FARNELL: unknown; OC_NEWARK: 79C2295)  [DIL08]
1  !SHDN  in
2  VREF  out
3  SS  pas
4  CC  in
5  GND  pwr
6  LX  out
7  NC  nc
8  V+  pwr

## Footprint DIL08 (pad centres in mm)
Dual In Line Package
drill 0.813 long: 1 -3.81,-3.81; 2 -1.27,-3.81; 3 1.27,-3.81; 4 3.81,-3.81; 5 3.81,3.81; 6 1.27,3.81; 7 -1.27,3.81; 8 -3.81,3.81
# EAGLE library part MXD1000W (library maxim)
DELAY LINE

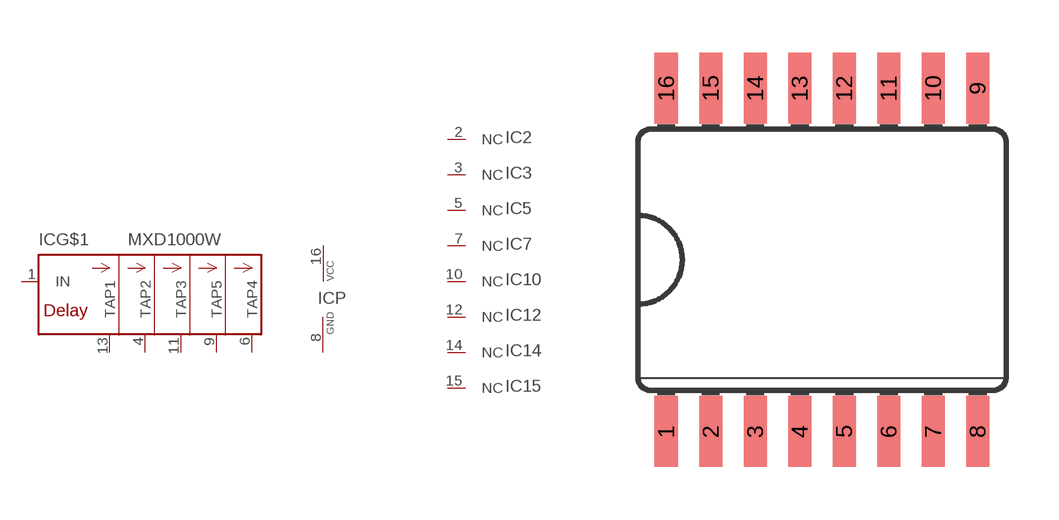
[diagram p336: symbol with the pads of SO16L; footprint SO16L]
Designator prefix IC; gates G$1=MXD1000 P=VCC-GND 2=NC 3=NC 5=NC 7=NC 10=NC 12=NC 14=NC 15=NC

## MXD1000W (OC_FARNELL: unknown; OC_NEWARK: unknown)  [SO16L]
1  G$1:IN  in
2  2:NC  nc
3  3:NC  nc
4  G$1:TAP2  out
5  5:NC  nc
6  G$1:TAP4  out
7  7:NC  nc
8  P:GND  pwr
9  G$1:TAP5  out
10  10:NC  nc
11  G$1:TAP3  out
12  12:NC  nc
13  G$1:TAP1  out
14  14:NC  nc
15  15:NC  nc
16  P:VCC  pwr

## Footprint SO16L (pad centres in mm)
Small Outline Package .300 SIOC Source: http://www.maxim-ic.com/cgi-bin/packages?pkg=16%2FSOIC%2E300&Type=Max
smd 0.66 x 2.032: 1 -4.445,-4.902; 2 -3.175,-4.902; 3 -1.905,-4.902; 4 -0.635,-4.902; 5 0.635,-4.902; 6 1.905,-4.902; 7 3.175,-4.902; 8 4.445,-4.902; 9 4.445,4.902; 10 3.175,4.902; 11 1.905,4.902; 12 0.635,4.902; 13 -0.635,4.902; 14 -1.905,4.902; 15 -3.175,4.902; 16 -4.445,4.902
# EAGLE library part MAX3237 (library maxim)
RS232 TRANSCEIVER

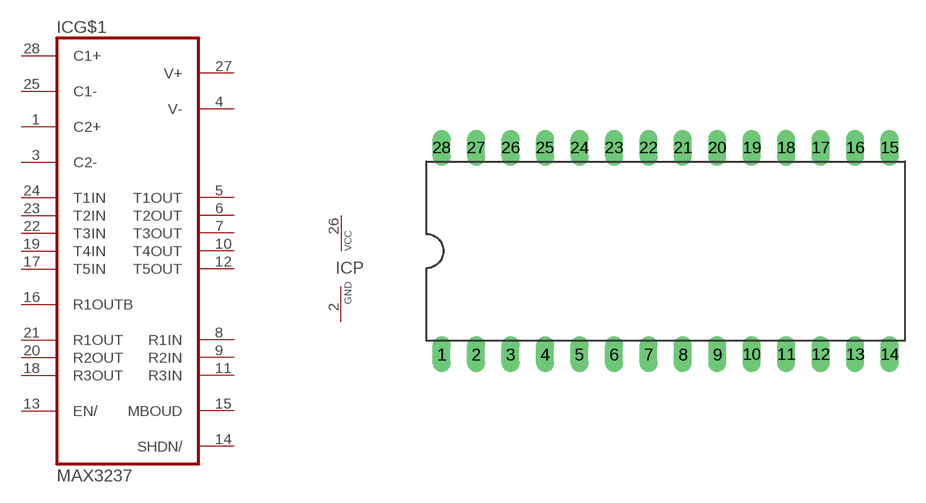
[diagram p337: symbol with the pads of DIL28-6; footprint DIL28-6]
Designator prefix IC; gates G$1=MAX3237 P=VCC-GND

## MAX3237 (OC_FARNELL: unknown; OC_NEWARK: unknown)  [DIL28-6]
1  G$1:C2+  pas
2  P:GND  pwr
3  G$1:C2-  pas
4  G$1:V-  pas
5  G$1:T1OUT  out
6  G$1:T2OUT  out
7  G$1:T3OUT  out
8  G$1:R1IN  in
9  G$1:R2IN  in
10  G$1:T4OUT  out
11  G$1:R3IN  in
12  G$1:T5OUT  out
13  G$1:EN/  in
14  G$1:SHDN/  in
15  G$1:MBOUD  in
16  G$1:R1OUTB  out
17  G$1:T5IN  in
18  G$1:R3OUT  out
19  G$1:T4IN  in
20  G$1:R2OUT  out
21  G$1:R1OUT  out
22  G$1:T3IN  in
23  G$1:T2IN  in
24  G$1:T1IN  in
25  G$1:C1-  pas
26  P:VCC  pwr
27  G$1:V+  pas
28  G$1:C1+  pas

## Footprint DIL28-6 (pad centres in mm)
Dual In Line Package 0.6 inch
drill 0.813 long: 1 -16.51,-7.62; 2 -13.97,-7.62; 3 -11.43,-7.62; 4 -8.89,-7.62; 5 -6.35,-7.62; 6 -3.81,-7.62; 7 -1.27,-7.62; 8 1.27,-7.62; 9 3.81,-7.62; 10 6.35,-7.62; 11 8.89,-7.62; 12 11.43,-7.62; 13 13.97,-7.62; 14 16.51,-7.62; 15 16.51,7.62; 16 13.97,7.62; 17 11.43,7.62; 18 8.89,7.62; 19 6.35,7.62; 20 3.81,7.62; 21 1.27,7.62; 22 -1.27,7.62; 23 -3.81,7.62; 24 -6.35,7.62; 25 -8.89,7.62; 26 -11.43,7.62; 27 -13.97,7.62; 28 -16.51,7.62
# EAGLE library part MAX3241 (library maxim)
RS232 TRANSCEIVER

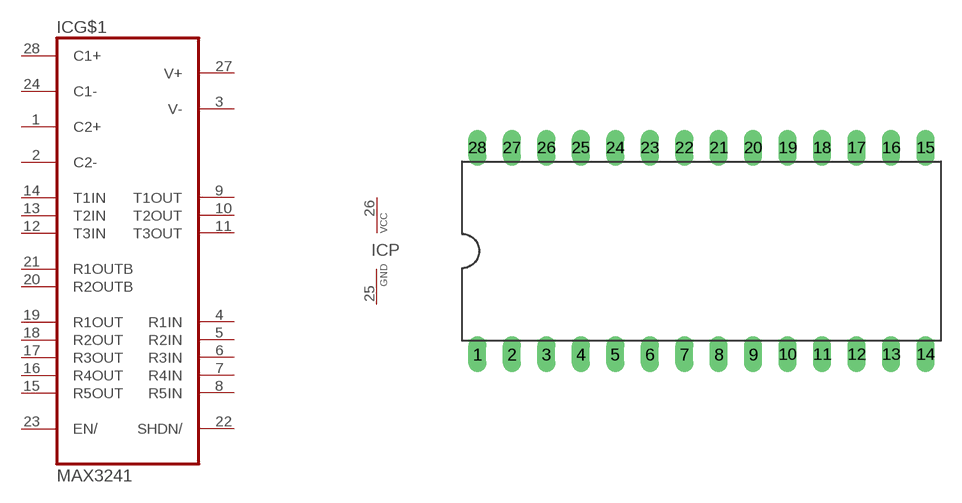
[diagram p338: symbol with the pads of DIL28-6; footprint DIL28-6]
Designator prefix IC; gates G$1=MAX3241 P=VCC-GND

## MAX3241 (OC_FARNELL: unknown; OC_NEWARK: unknown)  [DIL28-6]
1  G$1:C2+  pas
2  G$1:C2-  pas
3  G$1:V-  pas
4  G$1:R1IN  in
5  G$1:R2IN  in
6  G$1:R3IN  in
7  G$1:R4IN  in
8  G$1:R5IN  in
9  G$1:T1OUT  out
10  G$1:T2OUT  out
11  G$1:T3OUT  out
12  G$1:T3IN  in
13  G$1:T2IN  in
14  G$1:T1IN  in
15  G$1:R5OUT  out
16  G$1:R4OUT  out
17  G$1:R3OUT  out
18  G$1:R2OUT  out
19  G$1:R1OUT  out
20  G$1:R2OUTB  out
21  G$1:R1OUTB  out
22  G$1:SHDN/  in
23  G$1:EN/  in
24  G$1:C1-  pas
25  P:GND  pwr
26  P:VCC  pwr
27  G$1:V+  pas
28  G$1:C1+  pas

## Footprint DIL28-6 (pad centres in mm)
Dual In Line Package 0.6 inch
drill 0.813 long: 1 -16.51,-7.62; 2 -13.97,-7.62; 3 -11.43,-7.62; 4 -8.89,-7.62; 5 -6.35,-7.62; 6 -3.81,-7.62; 7 -1.27,-7.62; 8 1.27,-7.62; 9 3.81,-7.62; 10 6.35,-7.62; 11 8.89,-7.62; 12 11.43,-7.62; 13 13.97,-7.62; 14 16.51,-7.62; 15 16.51,7.62; 16 13.97,7.62; 17 11.43,7.62; 18 8.89,7.62; 19 6.35,7.62; 20 3.81,7.62; 21 1.27,7.62; 22 -1.27,7.62; 23 -3.81,7.62; 24 -6.35,7.62; 25 -8.89,7.62; 26 -11.43,7.62; 27 -13.97,7.62; 28 -16.51,7.62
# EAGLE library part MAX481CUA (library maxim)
RS485 TRANSEIVER

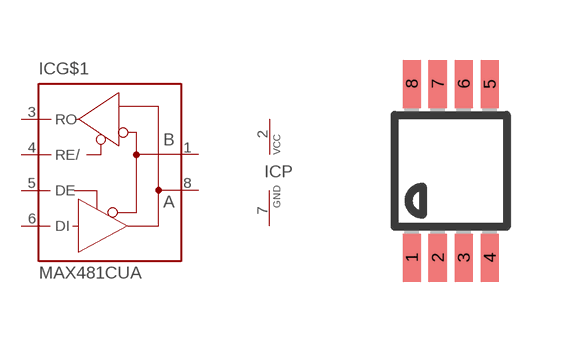
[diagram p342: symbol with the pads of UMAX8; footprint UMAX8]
Designator prefix IC; gates G$1=MAX481 P=VCC-GND

## MAX481CUA (MPN: MAX481CUA+; OC_FARNELL: unknown; OC_NEWARK: 71P2381)  [UMAX8]
1  G$1:B  pas
2  P:VCC  pwr
3  G$1:RO  out
4  G$1:RE/  in
5  G$1:DE  in
6  G$1:DI  in
7  P:GND  pwr
8  G$1:A  pas

## Footprint UMAX8 (pad centres in mm)
micro MAX Package
smd 0.45 x 1.2: 1 -0.975,-2.175; 2 -0.325,-2.175; 3 0.325,-2.175; 4 0.975,-2.175; 5 0.975,2.175; 6 0.325,2.175; 7 -0.325,2.175; 8 -0.975,2.175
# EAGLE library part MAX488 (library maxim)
RS485 TRANSEIVER Source: Data sheet

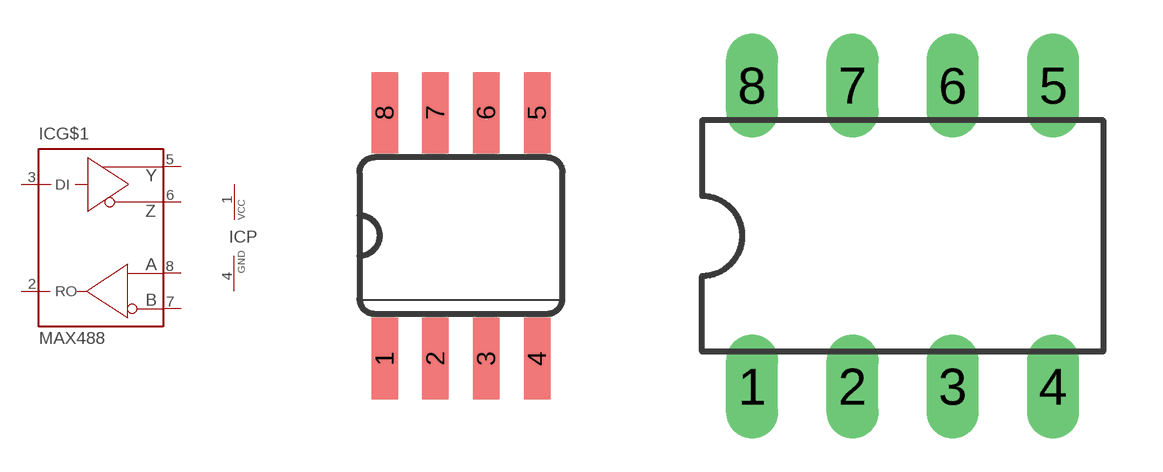
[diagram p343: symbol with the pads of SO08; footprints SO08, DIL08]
Designator prefix IC; gates G$1=MAX488 P=VCC-GND

## MAX488CSA (MF: MAXIM; MPN: MAX488CSA; OC_FARNELL: 3534170; OC_NEWARK: 34C3921)  [SO08]
1  P:VCC  pwr
2  G$1:RO  out
3  G$1:DI  in
4  P:GND  pwr
5  G$1:Y  out
6  G$1:Z  out
7  G$1:B  in
8  G$1:A  in

## MAX488CPD (OC_FARNELL: unknown; OC_NEWARK: unknown)  [DIL08]
Pads as for SO08

## MAX488CUA (MPN: MAX488CUA+; OC_FARNELL: unknown; OC_NEWARK: 99K3447)  [UMAX8]
1  G$1:B  in
2  G$1:A  in
3  P:VCC  pwr
4  G$1:RO  out
5  G$1:DI  in
6  P:GND  pwr
7  G$1:Y  out
8  G$1:Z  out

## Footprint SO08 (pad centres in mm)
Small Outline Package SOIC 150 mil
smd 0.66 x 2.032: 1 -1.905,-3.073; 2 -0.635,-3.073; 3 0.635,-3.073; 4 1.905,-3.073; 5 1.905,3.073; 6 0.635,3.073; 7 -0.635,3.073; 8 -1.905,3.073

## Footprint DIL08 (pad centres in mm)
Dual In Line Package
drill 0.813 long: 1 -3.81,-3.81; 2 -1.27,-3.81; 3 1.27,-3.81; 4 3.81,-3.81; 5 3.81,3.81; 6 1.27,3.81; 7 -1.27,3.81; 8 -3.81,3.81

## Footprint UMAX8 (pad centres in mm)
micro MAX Package
smd 0.45 x 1.2: 1 -0.975,-2.175; 2 -0.325,-2.175; 3 0.325,-2.175; 4 0.975,-2.175; 5 0.975,2.175; 6 0.325,2.175; 7 -0.325,2.175; 8 -0.975,2.175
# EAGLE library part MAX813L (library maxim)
WATCHDOG

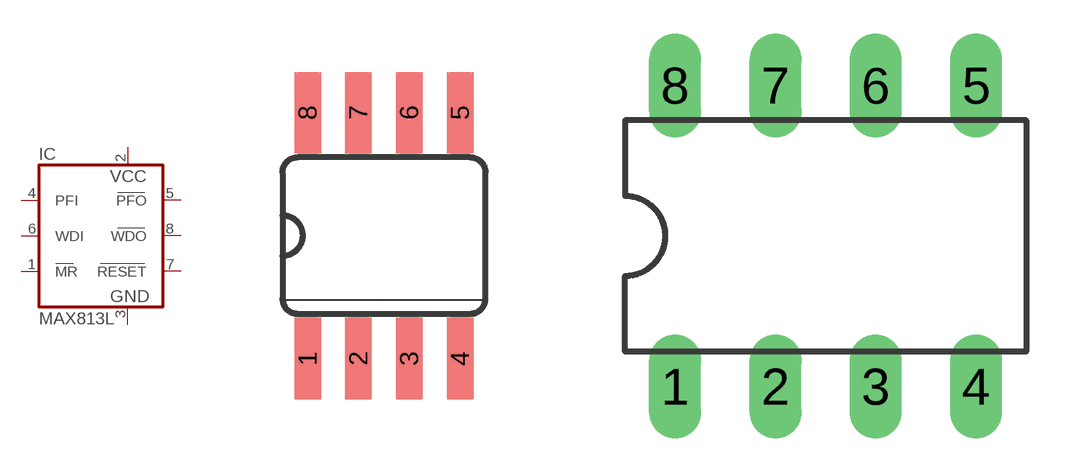
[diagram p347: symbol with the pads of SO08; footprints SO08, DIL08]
Designator prefix IC

## MAX813LCSA (MF: MAXIM; MPN: MAX813LCSA; OC_FARNELL: unknown; OC_NEWARK: 34C4031)  [SO08]
1  MR  in
2  VCC  pwr
3  GND  pwr
4  PFI  in
5  PFO  out
6  WDI  in
7  RESET  out
8  WDO  out

## MAX813LCUA (OC_FARNELL: unknown; OC_NEWARK: unknown)  [DIL08]
Pads as for SO08

## Footprint SO08 (pad centres in mm)
Small Outline Package SOIC 150 mil
smd 0.66 x 2.032: 1 -1.905,-3.073; 2 -0.635,-3.073; 3 0.635,-3.073; 4 1.905,-3.073; 5 1.905,3.073; 6 0.635,3.073; 7 -0.635,3.073; 8 -1.905,3.073

## Footprint DIL08 (pad centres in mm)
Dual In Line Package
drill 0.813 long: 1 -3.81,-3.81; 2 -1.27,-3.81; 3 1.27,-3.81; 4 3.81,-3.81; 5 3.81,3.81; 6 1.27,3.81; 7 -1.27,3.81; 8 -3.81,3.81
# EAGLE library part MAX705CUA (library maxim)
WATCHDOG

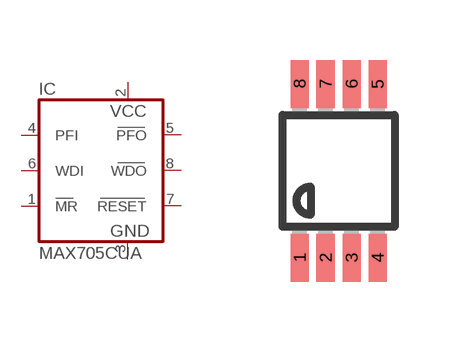
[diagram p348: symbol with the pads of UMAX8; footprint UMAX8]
Designator prefix IC

## MAX705CUA (MPN: MAX705CUA+; OC_FARNELL: unknown; OC_NEWARK: 13M2396)  [UMAX8]
1  MR  in
2  VCC  pwr
3  GND  pwr
4  PFI  in
5  PFO  out
6  WDI  in
7  RESET  out
8  WDO  out

## Footprint UMAX8 (pad centres in mm)
micro MAX Package
smd 0.45 x 1.2: 1 -0.975,-2.175; 2 -0.325,-2.175; 3 0.325,-2.175; 4 0.975,-2.175; 5 0.975,2.175; 6 0.325,2.175; 7 -0.325,2.175; 8 -0.975,2.175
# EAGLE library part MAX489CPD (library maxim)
RS485 TRANSEIVER

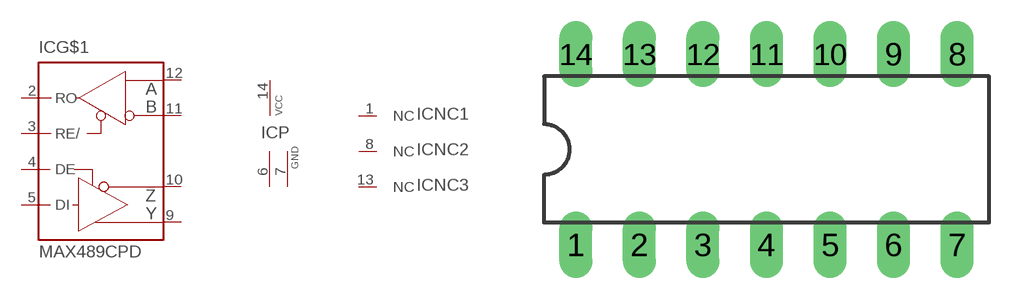
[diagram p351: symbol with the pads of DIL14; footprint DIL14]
Designator prefix IC; gates G$1=MAX489 NC1=NC NC2=NC NC3=NC P=PWR2GND

## MAX489CPD (MF: MAXIM; MPN: MAX489CPD; OC_FARNELL: 9725148; OC_NEWARK: 34C3922)  [DIL14]
1  NC1:NC  nc
2  G$1:RO  out
3  G$1:RE/  in
4  G$1:DE  in
5  G$1:DI  in
6  P:GND  pwr
7  P:GND  pwr
8  NC2:NC  nc
9  G$1:Y  pas
10  G$1:Z  pas
11  G$1:B  pas
12  G$1:A  pas
13  NC3:NC  nc
14  P:VCC  pwr

## Footprint DIL14 (pad centres in mm)
Dual In Line Package
drill 0.813 long: 1 -7.62,-3.81; 2 -5.08,-3.81; 3 -2.54,-3.81; 4 0,-3.81; 5 2.54,-3.81; 6 5.08,-3.81; 7 7.62,-3.81; 8 7.62,3.81; 9 5.08,3.81; 10 2.54,3.81; 11 0,3.81; 12 -2.54,3.81; 13 -5.08,3.81; 14 -7.62,3.81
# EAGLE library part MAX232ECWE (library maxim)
RS232 TRANSCEIVER

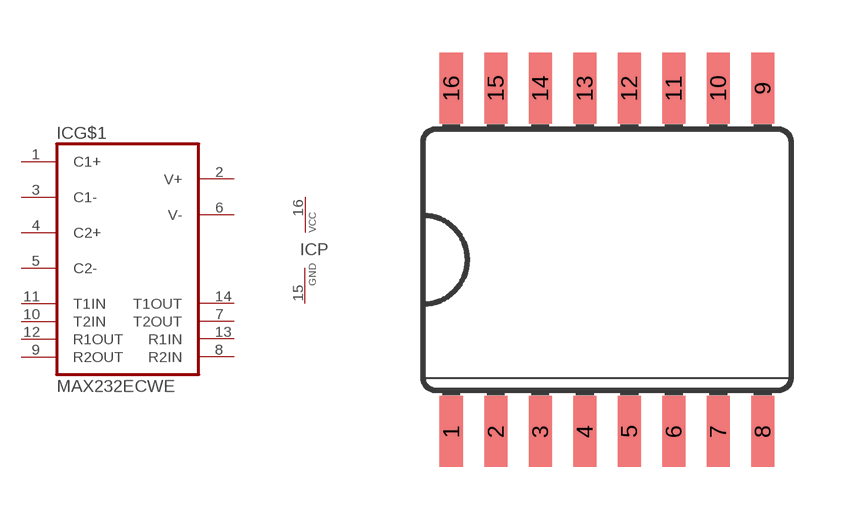
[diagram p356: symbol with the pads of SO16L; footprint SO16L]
Designator prefix IC; gates G$1=MAX232 P=VCC-GND

## MAX232ECWE (MF: MAXIM; MPN: MAX232ECWE+; OC_FARNELL: 9724435; OC_NEWARK: 67K4440)  [SO16L]
1  G$1:C1+
2  G$1:V+
3  G$1:C1-
4  G$1:C2+
5  G$1:C2-
6  G$1:V-
7  G$1:T2OUT  out
8  G$1:R2IN  in
9  G$1:R2OUT  out
10  G$1:T2IN  in
11  G$1:T1IN  in
12  G$1:R1OUT  out
13  G$1:R1IN  in
14  G$1:T1OUT  out
15  P:GND  pwr
16  P:VCC  pwr

## Footprint SO16L (pad centres in mm)
Small Outline Package .300 SIOC Source: http://www.maxim-ic.com/cgi-bin/packages?pkg=16%2FSOIC%2E300&Type=Max
smd 0.66 x 2.032: 1 -4.445,-4.902; 2 -3.175,-4.902; 3 -1.905,-4.902; 4 -0.635,-4.902; 5 0.635,-4.902; 6 1.905,-4.902; 7 3.175,-4.902; 8 4.445,-4.902; 9 4.445,4.902; 10 3.175,4.902; 11 1.905,4.902; 12 0.635,4.902; 13 -0.635,4.902; 14 -1.905,4.902; 15 -3.175,4.902; 16 -4.445,4.902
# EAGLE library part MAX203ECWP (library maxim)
RS232 TRANSCEIVER

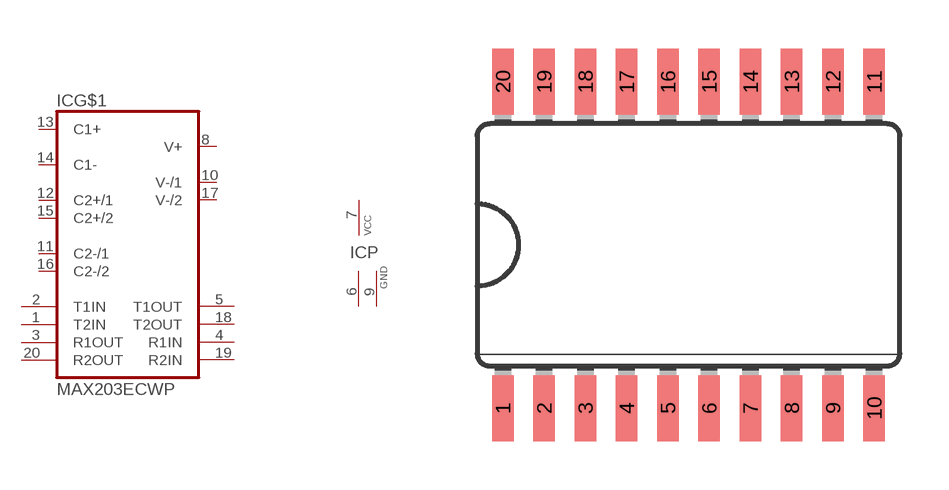
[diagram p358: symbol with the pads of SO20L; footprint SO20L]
Designator prefix IC; gates G$1=MAX203E P=PWR2GND

## MAX203ECWP (MPN: MAX203ECWP+G36; OC_FARNELL: 1224204; OC_NEWARK: 89K3435)  [SO20L]
1  G$1:T2IN  in
2  G$1:T1IN  in
3  G$1:R1OUT  out
4  G$1:R1IN  in
5  G$1:T1OUT  out
6  P:GND  pwr
7  P:VCC  pwr
8  G$1:V+  pas
9  P:GND  pwr
10  G$1:V-/1  pas
11  G$1:C2-/1  pas
12  G$1:C2+/1  pas
13  G$1:C1+  pas
14  G$1:C1-  pas
15  G$1:C2+/2  pas
16  G$1:C2-/2  pas
17  G$1:V-/2  pas
18  G$1:T2OUT  out
19  G$1:R2IN  in
20  G$1:R2OUT  out

## Footprint SO20L (pad centres in mm)
Small Outline Package
smd 0.66 x 2.032: 1 -5.715,-5.029; 2 -4.445,-5.029; 3 -3.175,-5.029; 4 -1.905,-5.029; 5 -0.635,-5.029; 6 0.635,-5.029; 7 1.905,-5.029; 8 3.175,-5.029; 9 4.445,-5.029; 10 5.715,-5.029; 11 5.715,5.029; 12 4.445,5.029; 13 3.175,5.029; 14 1.905,5.029; 15 0.635,5.029; 16 -0.635,5.029; 17 -1.905,5.029; 18 -3.175,5.029; 19 -4.445,5.029; 20 -5.715,5.029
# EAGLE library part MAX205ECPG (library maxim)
RS232 TRANSCEIVER

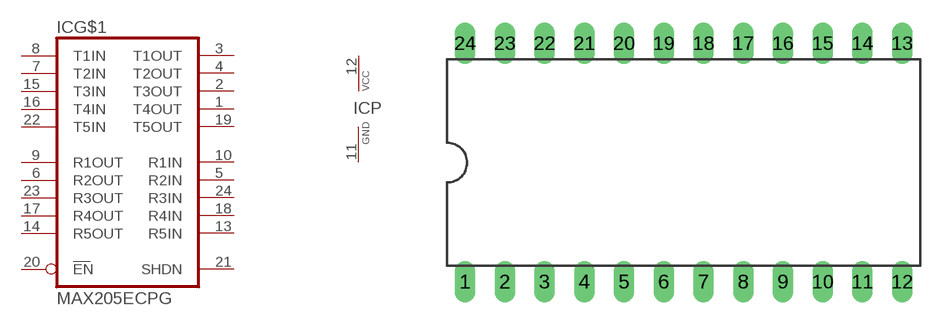
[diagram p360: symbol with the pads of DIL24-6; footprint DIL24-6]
Designator prefix IC; gates G$1=MAX235 P=VCC-GND

## MAX205ECPG (MPN: MAX205ECPG; OC_FARNELL: unknown; OC_NEWARK: 77C8455)  [DIL24-6]
1  G$1:T4OUT  out
2  G$1:T3OUT  out
3  G$1:T1OUT  out
4  G$1:T2OUT  out
5  G$1:R2IN  in
6  G$1:R2OUT  out
7  G$1:T2IN  in
8  G$1:T1IN  in
9  G$1:R1OUT  out
10  G$1:R1IN  in
11  P:GND  pwr
12  P:VCC  pwr
13  G$1:R5IN  in
14  G$1:R5OUT  out
15  G$1:T3IN  in
16  G$1:T4IN  in
17  G$1:R4OUT  out
18  G$1:R4IN  in
19  G$1:T5OUT  out
20  G$1:EN  pas
21  G$1:SHDN  pas
22  G$1:T5IN  in
23  G$1:R3OUT  out
24  G$1:R3IN  in

## Footprint DIL24-6 (pad centres in mm)
Dual In Line Package 0.6 inch
drill 0.813 long: 1 -13.97,-7.62; 2 -11.43,-7.62; 3 -8.89,-7.62; 4 -6.35,-7.62; 5 -3.81,-7.62; 6 -1.27,-7.62; 7 1.27,-7.62; 8 3.81,-7.62; 9 6.35,-7.62; 10 8.89,-7.62; 11 11.43,-7.62; 12 13.97,-7.62; 13 13.97,7.62; 14 11.43,7.62; 15 8.89,7.62; 16 6.35,7.62; 17 3.81,7.62; 18 1.27,7.62; 19 -1.27,7.62; 20 -3.81,7.62; 21 -6.35,7.62; 22 -8.89,7.62; 23 -11.43,7.62; 24 -13.97,7.62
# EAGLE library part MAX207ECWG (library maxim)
RS232 TRANSCEIVER

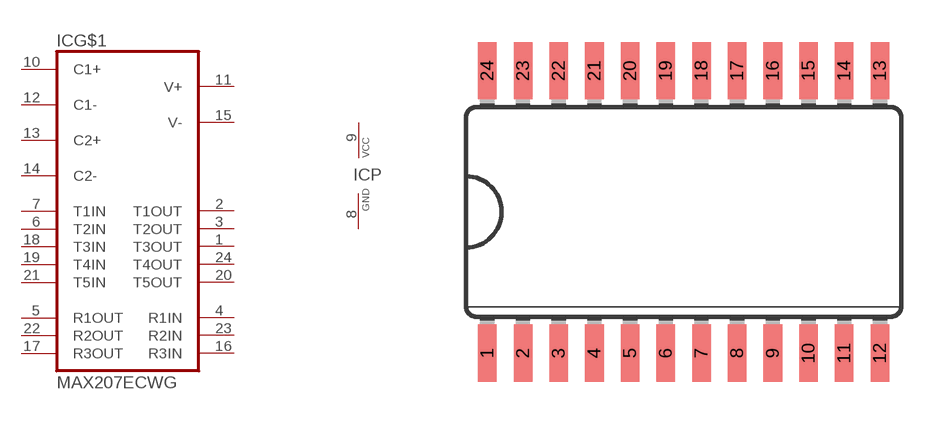
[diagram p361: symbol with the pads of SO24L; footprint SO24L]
Designator prefix IC; gates G$1=MAX237 P=VCC-GND

## MAX207ECWG (MF: MAXIM; MPN: MAX207ECWG+; OC_FARNELL: unknown; OC_NEWARK: 28K3258)  [SO24L]
1  G$1:T3OUT  out
2  G$1:T1OUT  out
3  G$1:T2OUT  out
4  G$1:R1IN  in
5  G$1:R1OUT  out
6  G$1:T2IN  in
7  G$1:T1IN  in
8  P:GND  pwr
9  P:VCC  pwr
10  G$1:C1+
11  G$1:V+
12  G$1:C1-
13  G$1:C2+
14  G$1:C2-
15  G$1:V-
16  G$1:R3IN  in
17  G$1:R3OUT  out
18  G$1:T3IN  in
19  G$1:T4IN  in
20  G$1:T5OUT  out
21  G$1:T5IN  in
22  G$1:R2OUT  out
23  G$1:R2IN  in
24  G$1:T4OUT  out

## Footprint SO24L (pad centres in mm)
Small Outline Package
smd 0.66 x 2.032: 1 -6.985,-5.029; 2 -5.715,-5.029; 3 -4.445,-5.029; 4 -3.175,-5.029; 5 -1.905,-5.029; 6 -0.635,-5.029; 7 0.635,-5.029; 8 1.905,-5.029; 9 3.175,-5.029; 10 4.445,-5.029; 11 5.715,-5.029; 12 6.985,-5.029; 13 6.985,5.029; 14 5.715,5.029; 15 4.445,5.029; 16 3.175,5.029; 17 1.905,5.029; 18 0.635,5.029; 19 -0.635,5.029; 20 -1.905,5.029; 21 -3.175,5.029; 22 -4.445,5.029; 23 -5.715,5.029; 24 -6.985,5.029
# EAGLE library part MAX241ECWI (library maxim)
RS232 TRANSCEIVER

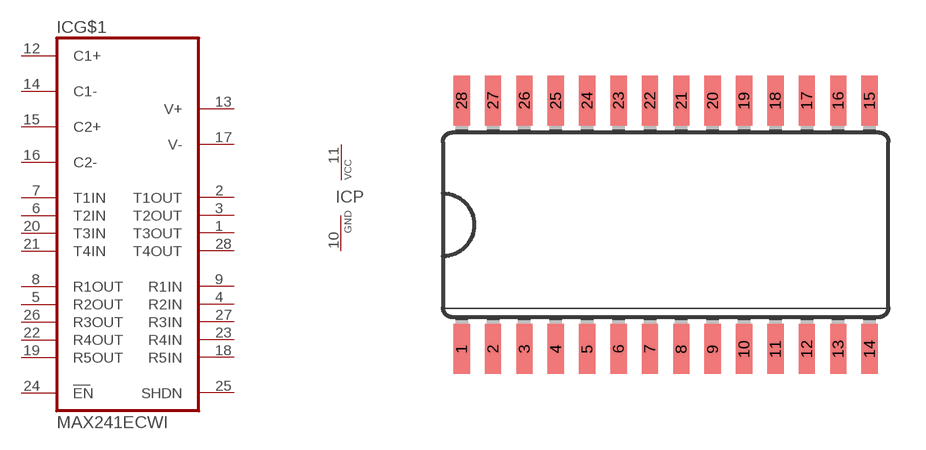
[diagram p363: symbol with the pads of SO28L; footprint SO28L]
Designator prefix IC; gates G$1=MAX211E P=VCC-GND

## MAX241ECWI (MF: MAXIM; MPN: MAX241ECWI+; OC_FARNELL: unknown; OC_NEWARK: 23K5839)  [SO28L]
1  G$1:T3OUT  out
2  G$1:T1OUT  out
3  G$1:T2OUT  out
4  G$1:R2IN  in
5  G$1:R2OUT  out
6  G$1:T2IN  in
7  G$1:T1IN  in
8  G$1:R1OUT  out
9  G$1:R1IN  in
10  P:GND  pwr
11  P:VCC  pwr
12  G$1:C1+  pas
13  G$1:V+  pas
14  G$1:C1-  pas
15  G$1:C2+  pas
16  G$1:C2-  pas
17  G$1:V-  pas
18  G$1:R5IN  in
19  G$1:R5OUT  out
20  G$1:T3IN  in
21  G$1:T4IN  in
22  G$1:R4OUT  out
23  G$1:R4IN  in
24  G$1:EN  in
25  G$1:SHDN  in
26  G$1:R3OUT  out
27  G$1:R3IN  in
28  G$1:T4OUT  out

## Footprint SO28L (pad centres in mm)
Small Outline Package MAX3221-MAX3243.pdf; SO28W
smd 0.66 x 2.032: 1 -8.255,-5.029; 2 -6.985,-5.029; 3 -5.715,-5.029; 4 -4.445,-5.029; 5 -3.175,-5.029; 6 -1.905,-5.029; 7 -0.635,-5.029; 8 0.635,-5.029; 9 1.905,-5.029; 10 3.175,-5.029; 11 4.445,-5.029; 12 5.715,-5.029; 13 6.985,-5.029; 14 8.255,-5.029; 15 8.255,5.029; 16 6.985,5.029; 17 5.715,5.029; 18 4.445,5.029; 19 3.175,5.029; 20 1.905,5.029; 21 0.635,5.029; 22 -0.635,5.029; 23 -1.905,5.029; 24 -3.175,5.029; 25 -4.445,5.029; 26 -5.715,5.029; 27 -6.985,5.029; 28 -8.255,5.029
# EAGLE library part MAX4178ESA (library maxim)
BUFFER

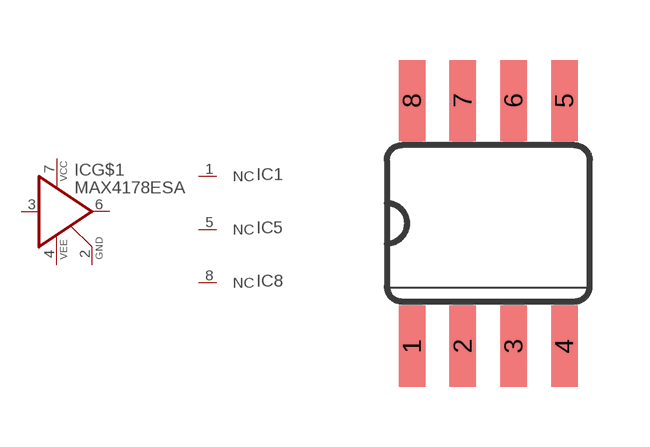
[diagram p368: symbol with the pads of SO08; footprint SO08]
Designator prefix IC; gates G$1=BUFF3P 1=NC 5=NC 8=NC

## MAX4178ESA (OC_FARNELL: unknown; OC_NEWARK: unknown)  [SO08]
1  1:NC  nc
2  G$1:GND  pwr
3  G$1:IN  in
4  G$1:VEE  pwr
5  5:NC  nc
6  G$1:OUT  out
7  G$1:VCC  pwr
8  8:NC  nc

## Footprint SO08 (pad centres in mm)
Small Outline Package SOIC 150 mil
smd 0.66 x 2.032: 1 -1.905,-3.073; 2 -0.635,-3.073; 3 0.635,-3.073; 4 1.905,-3.073; 5 1.905,3.073; 6 0.635,3.073; 7 -0.635,3.073; 8 -1.905,3.073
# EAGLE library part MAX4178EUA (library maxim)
BUFFER

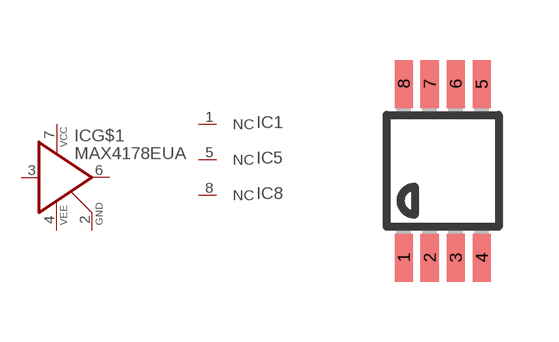
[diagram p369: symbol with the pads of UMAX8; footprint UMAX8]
Designator prefix IC; gates G$1=BUFF3P 1=NC 5=NC 8=NC

## MAX4178EUA (OC_FARNELL: unknown; OC_NEWARK: unknown)  [UMAX8]
1  1:NC  nc
2  G$1:GND  pwr
3  G$1:IN  in
4  G$1:VEE  pwr
5  5:NC  nc
6  G$1:OUT  out
7  G$1:VCC  pwr
8  8:NC  nc

## Footprint UMAX8 (pad centres in mm)
micro MAX Package
smd 0.45 x 1.2: 1 -0.975,-2.175; 2 -0.325,-2.175; 3 0.325,-2.175; 4 0.975,-2.175; 5 0.975,2.175; 6 0.325,2.175; 7 -0.325,2.175; 8 -0.975,2.175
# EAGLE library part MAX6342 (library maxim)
RESET CIRCUIT

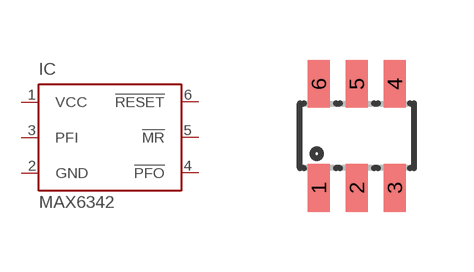
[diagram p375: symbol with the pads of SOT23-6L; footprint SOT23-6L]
Designator prefix IC

## MAX6342 (OC_FARNELL: unknown; OC_NEWARK: unknown)  [SOT23-6L]
1  VCC  pwr
2  GND  pwr
3  PFI  in
4  !PFO  out
5  !MR  in
6  !RESET  out

## Footprint SOT23-6L (pad centres in mm)
Small Outline Transistor
smd 0.55 x 1.2: 1 -0.95,-1.3; 2 0,-1.3; 3 0.95,-1.3; 4 0.95,1.3; 5 0,1.3; 6 -0.95,1.3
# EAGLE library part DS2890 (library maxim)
1-Wire Digital Potentiometer DALLAS Semiconductor; http://www.maxim-ic.com/

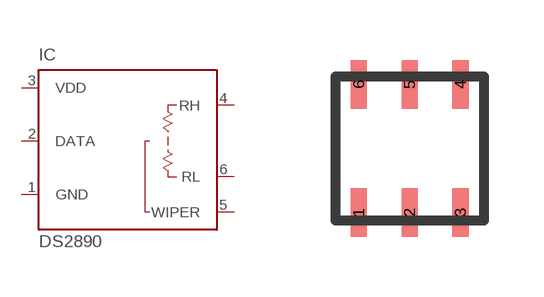
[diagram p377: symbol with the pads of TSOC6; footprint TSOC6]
Designator prefix IC

## DS2890P (OC_FARNELL: unknown; OC_NEWARK: unknown)  [TSOC6]
1  GND  pwr
2  DATA
3  VDD  pwr
4  RH  pas
5  WIPER  pas
6  RL  pas

## Footprint TSOC6 (pad centres in mm)
TSOC 6
smd 0.406 x 1.219: 1 -1.27,-1.6; 2 0,-1.6; 3 1.27,-1.6; 4 1.27,1.6; 5 0,1.6; 6 -1.27,1.6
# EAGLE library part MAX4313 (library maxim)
Video Multiplexer-Amplifier High-Speed, Low-Power, Single-Supply, Multichannel

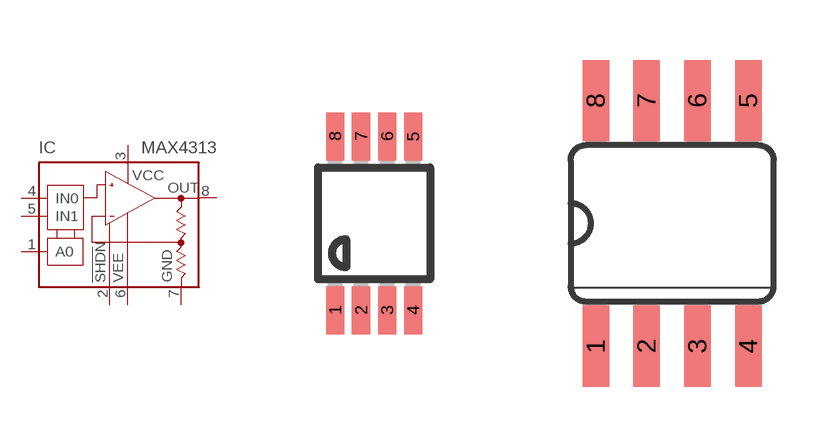
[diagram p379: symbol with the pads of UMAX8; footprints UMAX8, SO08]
Designator prefix IC

## MAX4313EUA (OC_FARNELL: unknown; OC_NEWARK: unknown)  [UMAX8]
1  A0  in
2  !SHDN  pas
3  V+  pwr
4  IN0  in
5  IN1  in
6  V-  pwr
7  GND  pwr
8  OUT  out

## MAX4313ESA (MF: MAXIM; MPN: MAX4313ESA+; OC_FARNELL: unknown; OC_NEWARK: 59J3144)  [SO08]
Pads as for UMAX8

## Footprint UMAX8 (pad centres in mm)
micro MAX Package
smd 0.45 x 1.2: 1 -0.975,-2.175; 2 -0.325,-2.175; 3 0.325,-2.175; 4 0.975,-2.175; 5 0.975,2.175; 6 0.325,2.175; 7 -0.325,2.175; 8 -0.975,2.175

## Footprint SO08 (pad centres in mm)
Small Outline Package SOIC 150 mil
smd 0.66 x 2.032: 1 -1.905,-3.073; 2 -0.635,-3.073; 3 0.635,-3.073; 4 1.905,-3.073; 5 1.905,3.073; 6 0.635,3.073; 7 -0.635,3.073; 8 -1.905,3.073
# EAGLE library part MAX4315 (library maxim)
Video Multiplexer-Amplifier High-Speed, Low-Power, Single-Supply, Multichannel

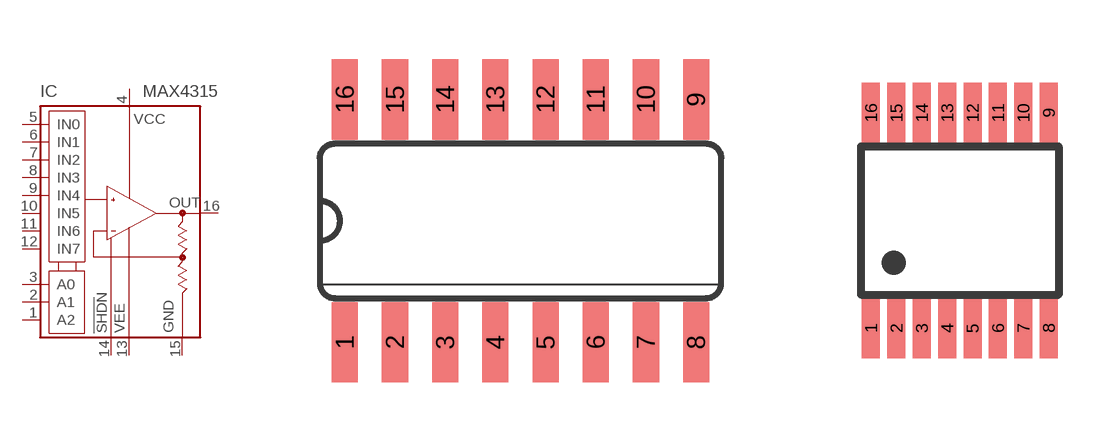
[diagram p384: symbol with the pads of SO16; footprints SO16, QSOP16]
Designator prefix IC

## MAX4315ESE (MF: MAXIM; MPN: MAX4315ESE+; OC_FARNELL: unknown; OC_NEWARK: 37K7967)  [SO16]
1  A2  in
2  A1  in
3  A0  in
4  V+  pwr
5  IN0  in
6  IN1  in
7  IN2  in
8  IN3  in
9  IN4  in
10  IN5  in
11  IN6  in
12  IN7  in
13  V-  pwr
14  !SHDN  pas
15  GND  pwr
16  OUT  out

## MAX4315EEE (MPN: MAX4315EEE+; OC_FARNELL: unknown; OC_NEWARK: 61K0445)  [QSOP16]
Pads as for SO16

## Footprint SO16 (pad centres in mm)
Small Outline Package .150 SIOC Source: http://www.maxim-ic.com/package_drawings/21-0041B.pdf
smd 0.66 x 2.032: 1 -4.445,-3.073; 2 -3.175,-3.073; 3 -1.905,-3.073; 4 -0.635,-3.073; 5 0.635,-3.073; 6 1.905,-3.073; 7 3.175,-3.073; 8 4.445,-3.073; 9 4.445,3.073; 10 3.175,3.073; 11 1.905,3.073; 12 0.635,3.073; 13 -0.635,3.073; 14 -1.905,3.073; 15 -3.175,3.073; 16 -4.445,3.073

## Footprint QSOP16 (pad centres in mm)
Small Outline Package
smd 0.45 x 1.5: 1 -2.223,-2.69; 2 -1.587,-2.69; 3 -0.953,-2.69; 4 -0.318,-2.69; 5 0.318,-2.69; 6 0.953,-2.69; 7 1.587,-2.69; 8 2.223,-2.69; 9 2.223,2.69; 10 1.587,2.69; 11 0.953,2.69; 12 0.318,2.69; 13 -0.318,2.69; 14 -0.953,2.69; 15 -1.587,2.69; 16 -2.223,2.69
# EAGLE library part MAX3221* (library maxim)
RS-232 Transceivers with AutoShutdown 1µA Supply-Current, True +3V to +5.5V http://dbserv.maxim-ic.com/

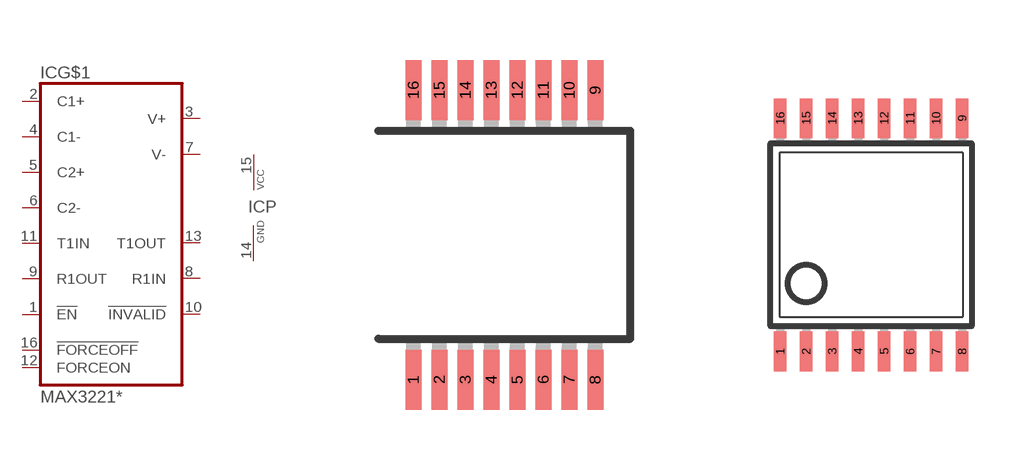
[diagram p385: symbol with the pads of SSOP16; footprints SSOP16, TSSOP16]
Designator prefix IC; gates G$1=MAX3221 P=VCC-GND

## MAX3221CAE (MF: MAXIM; MPN: MAX3221CAE+; OC_FARNELL: 9724508; OC_NEWARK: 53K7474), MAX3221EAE (MF: MAXIM; MPN: MAX3221EAE+; OC_FARNELL: 9725440; OC_NEWARK: 68K4609)  [SSOP16]
1  G$1:!EN  in
2  G$1:C1+  pas
3  G$1:V+  pas
4  G$1:C1-  pas
5  G$1:C2+  pas
6  G$1:C2-  pas
7  G$1:V-  pas
8  G$1:R1IN  in
9  G$1:R1OUT  out
10  G$1:!INVALID  in
11  G$1:T1IN  in
12  G$1:FORCEON  in
13  G$1:T1OUT  out
14  P:GND  pwr
15  P:VCC  pwr
16  G$1:!FORCEOFF  in

## MAX3221CUE (MF: MAXIM; MPN: MAX3221CUE+; OC_FARNELL: 1379915; OC_NEWARK: 68K4608), MAX3221EUE (MF: MAXIM; MPN: MAX3221EUE+; OC_FARNELL: 1379916; OC_NEWARK: 67K4827)  [TSSOP16]
Pads as for SSOP16

## Footprint SSOP16 (pad centres in mm)
Shrink Small Outline Package package type SS
smd 0.4 x 1.5: 1 -2.275,-3.625; 2 -1.625,-3.625; 3 -0.975,-3.625; 4 -0.325,-3.625; 5 0.325,-3.625; 6 0.975,-3.625; 7 1.625,-3.625; 8 2.275,-3.625; 9 2.275,3.625; 10 1.625,3.625; 11 0.975,3.625; 12 0.325,3.625; 13 -0.325,3.625; 14 -0.975,3.625; 15 -1.625,3.625; 16 -2.275,3.625

## Footprint TSSOP16 (pad centres in mm)
Thin Shrink Small Outline Plastic 16 http://www.maxim-ic.com .. MAX3223-MAX3243.pdf
smd 0.305 x 0.991: 1 -2.275,-2.918; 2 -1.625,-2.918; 3 -0.975,-2.918; 4 -0.325,-2.918; 5 0.325,-2.918; 6 0.975,-2.918; 7 1.625,-2.918; 8 2.275,-2.918; 9 2.275,2.918; 10 1.625,2.918; 11 0.975,2.918; 12 0.325,2.918; 13 -0.325,2.918; 14 -0.975,2.918; 15 -1.625,2.918; 16 -2.275,2.918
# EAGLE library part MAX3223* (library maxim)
RS-232 Transceivers with AutoShutdown 1µA Supply-Current, True +3V to +5.5V http://dbserv.maxim-ic.com/

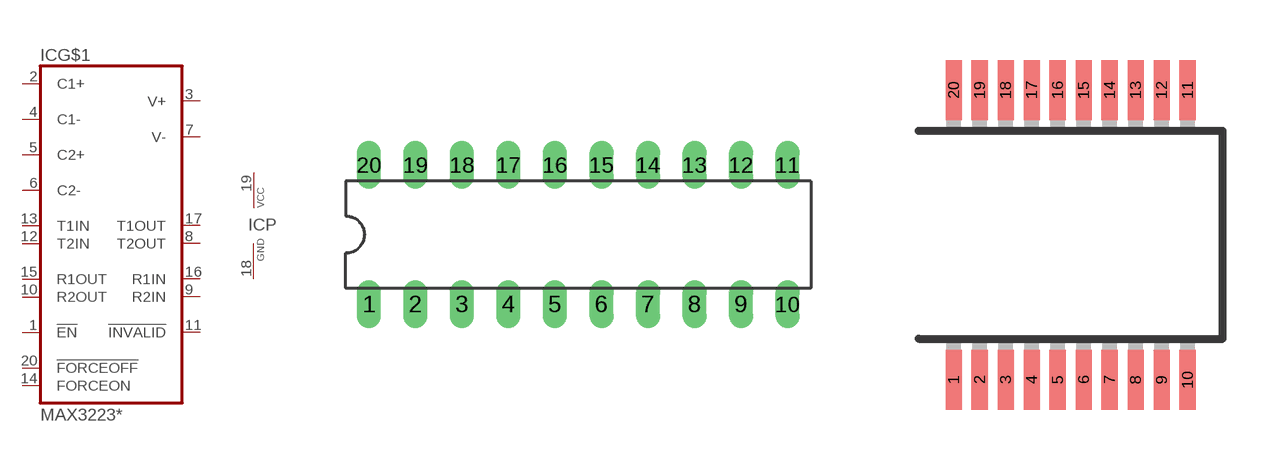
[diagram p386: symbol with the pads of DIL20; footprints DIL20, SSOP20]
Designator prefix IC; gates G$1=MAX3223 P=VCC-GND

## MAX3223CPP (MF: MAXIM; MPN: MAX3223CPP; OC_FARNELL: 1188043; OC_NEWARK: 34C3871), MAX3223EPP (MPN: MAX3223EPP+; OC_FARNELL: unknown; OC_NEWARK: 19M9596)  [DIL20]
1  G$1:!EN  in
2  G$1:C1+  pas
3  G$1:V+  pas
4  G$1:C1-  pas
5  G$1:C2+  pas
6  G$1:C2-  pas
7  G$1:V-  pas
8  G$1:T2OUT  out
9  G$1:R2IN  in
10  G$1:R2OUT  out
11  G$1:!INVALID  out
12  G$1:T2IN  in
13  G$1:T1IN  in
14  G$1:FORCEON  in
15  G$1:R1OUT  out
16  G$1:R1IN  in
17  G$1:T1OUT  out
18  P:GND  pwr
19  P:VCC  pwr
20  G$1:!FORCEOFF  in

## MAX3223CAP (MF: MAXIM; MPN: MAX3223CAP+; OC_FARNELL: 9725474; OC_NEWARK: 68K4615), MAX3223EAP (MF: MAXIM; MPN: MAX3223EAP+; OC_FARNELL: 9725482; OC_NEWARK: 68K4618)  [SSOP20]
Pads as for DIL20

## MAX3223CUP (MF: MAXIM; MPN: MAX3223CUP; OC_FARNELL: unknown; OC_NEWARK: 90C2820), MAX3223EUP (MF: MAXIM; MPN: MAX3223EUP+; OC_FARNELL: unknown; OC_NEWARK: 68K4621)  [TSSOP20]
Pads as for DIL20

## Footprint DIL20 (pad centres in mm)
Dual In Line Package
drill 0.813 long: 1 -11.43,-3.81; 2 -8.89,-3.81; 3 -6.35,-3.81; 4 -3.81,-3.81; 5 -1.27,-3.81; 6 1.27,-3.81; 7 3.81,-3.81; 8 6.35,-3.81; 9 8.89,-3.81; 10 11.43,-3.81; 11 11.43,3.81; 12 8.89,3.81; 13 6.35,3.81; 14 3.81,3.81; 15 1.27,3.81; 16 -1.27,3.81; 17 -3.81,3.81; 18 -6.35,3.81; 19 -8.89,3.81; 20 -11.43,3.81

## Footprint SSOP20 (pad centres in mm)
Shrink Small Outline Package package type SS
smd 0.4 x 1.5: 1 -2.925,-3.625; 2 -2.275,-3.625; 3 -1.625,-3.625; 4 -0.975,-3.625; 5 -0.325,-3.625; 6 0.325,-3.625; 7 0.975,-3.625; 8 1.625,-3.625; 9 2.275,-3.625; 10 2.925,-3.625; 11 2.925,3.625; 12 2.275,3.625; 13 1.625,3.625; 14 0.975,3.625; 15 0.325,3.625; 16 -0.325,3.625; 17 -0.975,3.625; 18 -1.625,3.625; 19 -2.275,3.625; 20 -2.925,3.625

## Footprint TSSOP20 (pad centres in mm)
Thin Shrink Small Outline Plastic 20 MAX3223-MAX3243.pdf
smd 0.305 x 0.991: 1 -2.925,-2.918; 2 -2.275,-2.918; 3 -1.625,-2.918; 4 -0.975,-2.918; 5 -0.325,-2.918; 6 0.325,-2.918; 7 0.975,-2.918; 8 1.625,-2.918; 9 2.275,-2.918; 10 2.925,-2.918; 11 2.925,2.918; 12 2.275,2.918; 13 1.625,2.918; 14 0.975,2.918; 15 0.325,2.918; 16 -0.325,2.918; 17 -0.975,2.918; 18 -1.625,2.918; 19 -2.275,2.918; 20 -2.925,2.918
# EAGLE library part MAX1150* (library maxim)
8-Bit, 500Msps Flash ADC Source: http://pdfserv.maxim-ic.com/en/ds/MAX1150.pdf

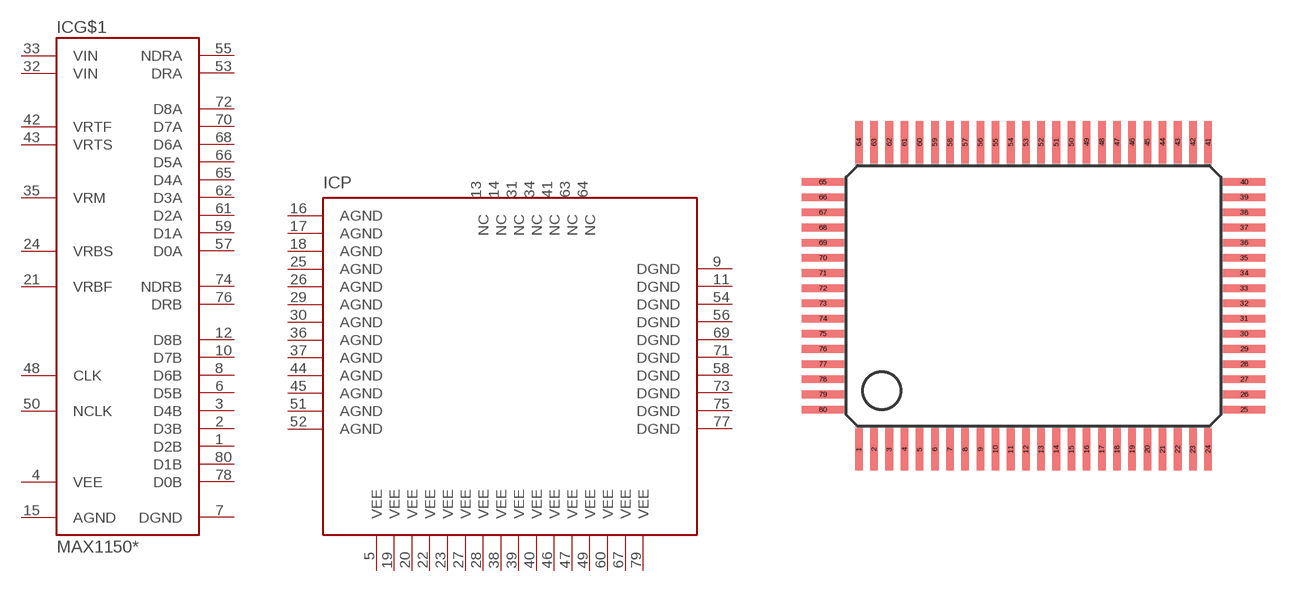
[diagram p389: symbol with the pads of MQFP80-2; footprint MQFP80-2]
Designator prefix IC; gates G$1=MAX1150 P=MAX1150-P

## MAX1150AIZS (OC_FARNELL: unknown; OC_NEWARK: unknown), MAX1150BIZS (OC_FARNELL: unknown; OC_NEWARK: unknown)  [MQFP80-2]
1  G$1:D2B  out
2  G$1:D3B  out
3  G$1:D4B  out
4  G$1:VEE  pwr
5  P:VEE  pwr
6  G$1:D5B  out
7  G$1:DGND  pwr
8  G$1:D6B  out
9  P:DGND  pwr
10  G$1:D7B  out
11  P:DGND  pwr
12  G$1:D8B  out
13  P:NC  nc
14  P:NC  nc
15  G$1:AGND  pwr
16  P:AGND  pwr
17  P:AGND  pwr
18  P:AGND  pwr
19  P:VEE  pwr
20  P:VEE  pwr
21  G$1:VRBF  in
22  P:VEE  pwr
23  P:VEE  pwr
24  G$1:VRBS  in
25  P:AGND  pwr
26  P:AGND  pwr
27  P:VEE  pwr
28  P:VEE  pwr
29  P:AGND  pwr
30  P:AGND  pwr
31  P:NC  nc
32  G$1:VIN  in
33  G$1:VIN  in
34  P:NC  nc
35  G$1:VRM  in
36  P:AGND  pwr
37  P:AGND  pwr
38  P:VEE  pwr
39  P:VEE  pwr
40  P:VEE  pwr
41  P:NC  nc
42  G$1:VRTF  in
43  G$1:VRTS  in
44  P:AGND  pwr
45  P:AGND  pwr
46  P:VEE  pwr
47  P:VEE  pwr
48  G$1:CLK  in
49  P:VEE  pwr
50  G$1:NCLK  in
51  P:AGND  pwr
52  P:AGND  pwr
53  G$1:DRA  out
54  P:DGND  pwr
55  G$1:NDRA  out
56  P:DGND  pwr
57  G$1:D0A  out
58  P:DGND  pwr
59  G$1:D1A  out
60  P:VEE  pwr
61  G$1:D2A  out
62  G$1:D3A  out
63  P:NC  nc
64  P:NC  nc
65  G$1:D4A  out
66  G$1:D5A  out
67  P:VEE  pwr
68  G$1:D6A  out
69  P:DGND  pwr
70  G$1:D7A  out
71  P:DGND  pwr
72  G$1:D8A  out
73  P:DGND  pwr
74  G$1:NDRB  out
75  P:DGND  pwr
76  G$1:DRB  out
77  P:DGND  pwr
78  G$1:D0B  out
79  P:VEE  pwr
80  G$1:D1B  out

## Footprint MQFP80-2 (pad centres in mm)
Metric Quad Flat Pack Source: refpackages.lbr
smd 0.4 x 2.2: 1 -9.2,-8.1; 2 -8.4,-8.1; 3 -7.6,-8.1; 4 -6.8,-8.1; 5 -6,-8.1; 6 -5.2,-8.1; 7 -4.4,-8.1; 8 -3.6,-8.1; 9 -2.8,-8.1; 10 -2,-8.1; 11 -1.2,-8.1; 12 -0.4,-8.1; 13 0.4,-8.1; 14 1.2,-8.1; 15 2,-8.1; 16 2.8,-8.1; 17 3.6,-8.1; 18 4.4,-8.1; 19 5.2,-8.1; 20 6,-8.1; 21 6.8,-8.1; 22 7.6,-8.1; 23 8.4,-8.1; 24 9.2,-8.1; 41 9.2,8.1; 42 8.4,8.1; 43 7.6,8.1; 44 6.8,8.1; 45 6,8.1; 46 5.2,8.1; 47 4.4,8.1; 48 3.6,8.1; 49 2.8,8.1; 50 2,8.1; 51 1.2,8.1; 52 0.4,8.1; 53 -0.4,8.1; 54 -1.2,8.1; 55 -2,8.1; 56 -2.8,8.1; 57 -3.6,8.1; 58 -4.4,8.1; 59 -5.2,8.1; 60 -6,8.1; 61 -6.8,8.1; 62 -7.6,8.1; 63 -8.4,8.1; 64 -9.2,8.1
smd 2.2 x 0.4: 25 11.1,-6; 26 11.1,-5.2; 27 11.1,-4.4; 28 11.1,-3.6; 29 11.1,-2.8; 30 11.1,-2; 31 11.1,-1.2; 32 11.1,-0.4; 33 11.1,0.4; 34 11.1,1.2; 35 11.1,2; 36 11.1,2.8; 37 11.1,3.6; 38 11.1,4.4; 39 11.1,5.2; 40 11.1,6; 65 -11.1,6; 66 -11.1,5.2; 67 -11.1,4.4; 68 -11.1,3.6; 69 -11.1,2.8; 70 -11.1,2; 71 -11.1,1.2; 72 -11.1,0.4; 73 -11.1,-0.4; 74 -11.1,-1.2; 75 -11.1,-2; 76 -11.1,-2.8; 77 -11.1,-3.6; 78 -11.1,-4.4; 79 -11.1,-5.2; 80 -11.1,-6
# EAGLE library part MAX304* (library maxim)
±10kV ESD-Protected, Quad 5V RS-485/422 Transmitters Source: MAX3040-MAX3045.pdf

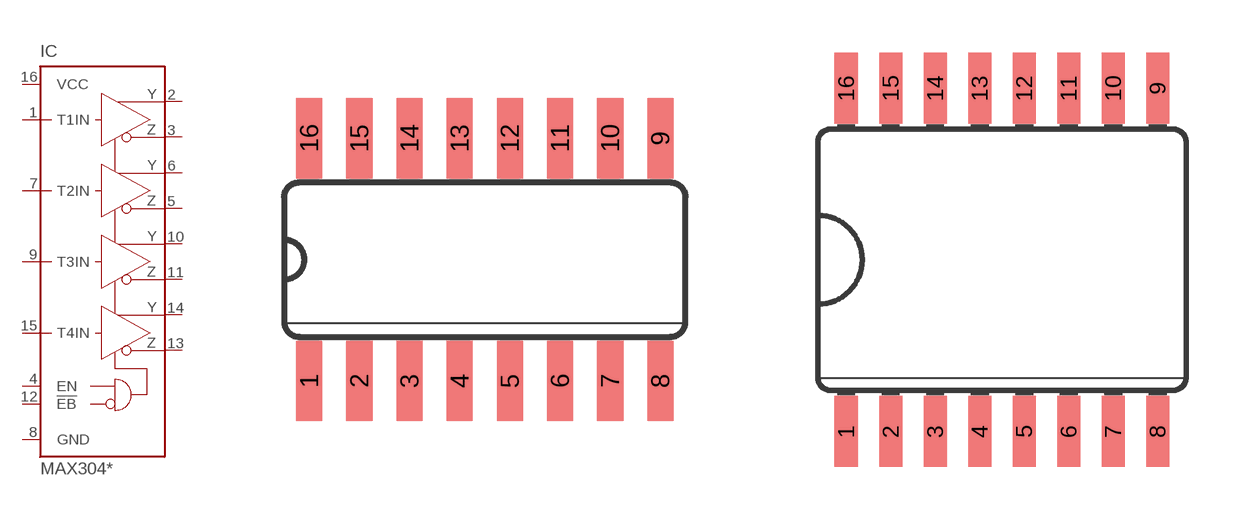
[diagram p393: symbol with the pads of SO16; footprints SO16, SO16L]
Designator prefix IC

## MAX3043CSE (MF: MAXIM; MPN: MAX3043CSE+; OC_FARNELL: unknown; OC_NEWARK: 37K7901), MAX3043ESE (MF: MAXIM; MPN: MAX3043ESE+; OC_FARNELL: unknown; OC_NEWARK: 37K7903), MAX3044CSE (MPN: MAX3044CSE+; OC_FARNELL: unknown; OC_NEWARK: 89K3569), MAX3044ESE (MPN: MAX3044ESE+; OC_FARNELL: unknown; OC_NEWARK: 65K6783), MAX3045BCSE (MPN: MAX3045BCSE+; OC_FARNELL: unknown; OC_NEWARK: 67K4570), MAX3045BESE (MPN: MAX3045BESE+; OC_FARNELL: unknown; OC_NEWARK: 67K4574)  [SO16]
1  T1IN  in
2  Y1  out
3  Z1  out
4  EN  in
5  Z2  out
6  Y2  out
7  T2IN  in
8  GND  pwr
9  T3IN  in
10  Y3  out
11  Z3  out
12  !EB  in
13  Z4  out
14  Y4  out
15  T4IN  in
16  VCC  pwr

## MAX3043CWE (OC_FARNELL: unknown; OC_NEWARK: unknown), MAX3043EWE (OC_FARNELL: unknown; OC_NEWARK: unknown), MAX3044CWE (OC_FARNELL: unknown; OC_NEWARK: unknown), MAX3044EWE (OC_FARNELL: unknown; OC_NEWARK: unknown), MAX3045BCWE (MPN: MAX3045BCWE+; OC_FARNELL: unknown; OC_NEWARK: 73K8529), MAX3045BEWE (MPN: MAX3045BEWE+; OC_FARNELL: unknown; OC_NEWARK: 73K8531)  [SO16L]
Pads as for SO16

## MAX3043CUE (MPN: MAX3043CUE+; OC_FARNELL: unknown; OC_NEWARK: 42M5431), MAX3043EUE (MF: MAXIM; MPN: MAX3043EUE+; OC_FARNELL: unknown; OC_NEWARK: 59J2979), MAX3044CUE (MPN: MAX3044CUE+; OC_FARNELL: unknown; OC_NEWARK: 53K6607), MAX3044EUE (MPN: MAX3044EUE+; OC_FARNELL: unknown; OC_NEWARK: 53K6609), MAX3045BCUE (MPN: MAX3045BCUE+; OC_FARNELL: unknown; OC_NEWARK: 67K4572), MAX3045BEUE (MPN: MAX3045BEUE+; OC_FARNELL: unknown; OC_NEWARK: 67K4576)  [TSSOP16]
Pads as for SO16

## Footprint SO16 (pad centres in mm)
Small Outline Package .150 SIOC Source: http://www.maxim-ic.com/package_drawings/21-0041B.pdf
smd 0.66 x 2.032: 1 -4.445,-3.073; 2 -3.175,-3.073; 3 -1.905,-3.073; 4 -0.635,-3.073; 5 0.635,-3.073; 6 1.905,-3.073; 7 3.175,-3.073; 8 4.445,-3.073; 9 4.445,3.073; 10 3.175,3.073; 11 1.905,3.073; 12 0.635,3.073; 13 -0.635,3.073; 14 -1.905,3.073; 15 -3.175,3.073; 16 -4.445,3.073

## Footprint SO16L (pad centres in mm)
Small Outline Package .300 SIOC Source: http://www.maxim-ic.com/cgi-bin/packages?pkg=16%2FSOIC%2E300&Type=Max
smd 0.66 x 2.032: 1 -4.445,-4.902; 2 -3.175,-4.902; 3 -1.905,-4.902; 4 -0.635,-4.902; 5 0.635,-4.902; 6 1.905,-4.902; 7 3.175,-4.902; 8 4.445,-4.902; 9 4.445,4.902; 10 3.175,4.902; 11 1.905,4.902; 12 0.635,4.902; 13 -0.635,4.902; 14 -1.905,4.902; 15 -3.175,4.902; 16 -4.445,4.902

## Footprint TSSOP16 (pad centres in mm)
Thin Shrink Small Outline Plastic 16 http://www.maxim-ic.com .. MAX3223-MAX3243.pdf
smd 0.305 x 0.991: 1 -2.275,-2.918; 2 -1.625,-2.918; 3 -0.975,-2.918; 4 -0.325,-2.918; 5 0.325,-2.918; 6 0.975,-2.918; 7 1.625,-2.918; 8 2.275,-2.918; 9 2.275,2.918; 10 1.625,2.918; 11 0.975,2.918; 12 0.325,2.918; 13 -0.325,2.918; 14 -0.975,2.918; 15 -1.625,2.918; 16 -2.275,2.918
